VERSION 5.8 ;
BUSBITCHARS "[]" ;
DIVIDERCHAR "/" ;
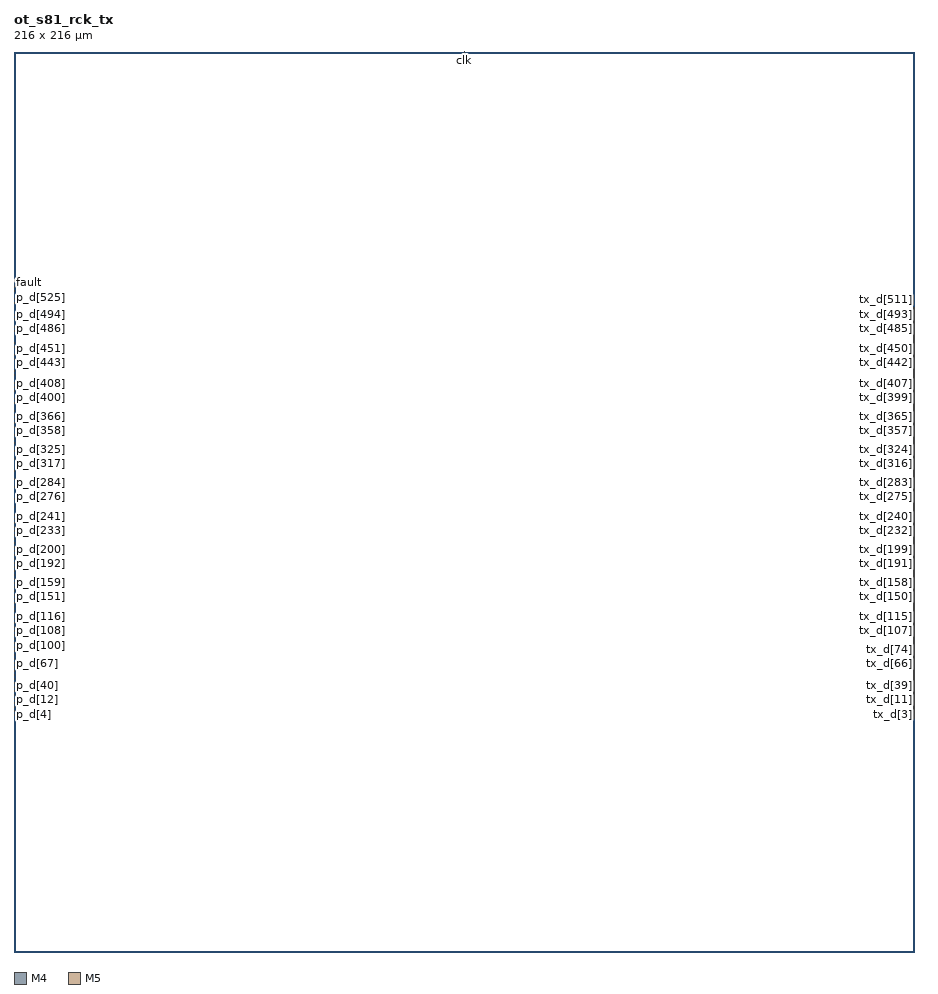
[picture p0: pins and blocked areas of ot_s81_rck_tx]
MACRO ot_s81_rck_tx
 CLASS BLOCK ;
 ORIGIN 0 0 ;
 SIZE 216.0 BY 216.0 ;
 SYMMETRY X Y ;
 PIN rst_n
  DIRECTION INPUT ;
  USE SIGNAL ;
  PORT
   LAYER M4 ;
   RECT 215.916 56.112 216.000 56.136 ;
  END
 END rst_n
 PIN tx_v
  DIRECTION INPUT ;
  USE SIGNAL ;
  PORT
   LAYER M4 ;
   RECT 215.916 56.304 216.000 56.328 ;
  END
 END tx_v
 PIN tx_d[0]
  DIRECTION INPUT ;
  USE SIGNAL ;
  PORT
   LAYER M4 ;
   RECT 215.916 56.496 216.000 56.520 ;
  END
 END tx_d[0]
 PIN tx_d[1]
  DIRECTION INPUT ;
  USE SIGNAL ;
  PORT
   LAYER M4 ;
   RECT 215.916 56.688 216.000 56.712 ;
  END
 END tx_d[1]
 PIN tx_d[2]
  DIRECTION INPUT ;
  USE SIGNAL ;
  PORT
   LAYER M4 ;
   RECT 215.916 56.880 216.000 56.904 ;
  END
 END tx_d[2]
 PIN tx_d[3]
  DIRECTION INPUT ;
  USE SIGNAL ;
  PORT
   LAYER M4 ;
   RECT 215.916 57.072 216.000 57.096 ;
  END
 END tx_d[3]
 PIN tx_d[4]
  DIRECTION INPUT ;
  USE SIGNAL ;
  PORT
   LAYER M4 ;
   RECT 215.916 57.264 216.000 57.288 ;
  END
 END tx_d[4]
 PIN tx_d[5]
  DIRECTION INPUT ;
  USE SIGNAL ;
  PORT
   LAYER M4 ;
   RECT 215.916 57.456 216.000 57.480 ;
  END
 END tx_d[5]
 PIN tx_d[6]
  DIRECTION INPUT ;
  USE SIGNAL ;
  PORT
   LAYER M4 ;
   RECT 215.916 57.648 216.000 57.672 ;
  END
 END tx_d[6]
 PIN tx_d[7]
  DIRECTION INPUT ;
  USE SIGNAL ;
  PORT
   LAYER M4 ;
   RECT 215.916 57.840 216.000 57.864 ;
  END
 END tx_d[7]
 PIN tx_d[8]
  DIRECTION INPUT ;
  USE SIGNAL ;
  PORT
   LAYER M4 ;
   RECT 215.916 58.032 216.000 58.056 ;
  END
 END tx_d[8]
 PIN tx_d[9]
  DIRECTION INPUT ;
  USE SIGNAL ;
  PORT
   LAYER M4 ;
   RECT 215.916 58.224 216.000 58.248 ;
  END
 END tx_d[9]
 PIN tx_d[10]
  DIRECTION INPUT ;
  USE SIGNAL ;
  PORT
   LAYER M4 ;
   RECT 215.916 58.416 216.000 58.440 ;
  END
 END tx_d[10]
 PIN tx_d[11]
  DIRECTION INPUT ;
  USE SIGNAL ;
  PORT
   LAYER M4 ;
   RECT 215.916 58.608 216.000 58.632 ;
  END
 END tx_d[11]
 PIN tx_d[12]
  DIRECTION INPUT ;
  USE SIGNAL ;
  PORT
   LAYER M4 ;
   RECT 215.916 58.800 216.000 58.824 ;
  END
 END tx_d[12]
 PIN tx_d[13]
  DIRECTION INPUT ;
  USE SIGNAL ;
  PORT
   LAYER M4 ;
   RECT 215.916 58.992 216.000 59.016 ;
  END
 END tx_d[13]
 PIN tx_d[14]
  DIRECTION INPUT ;
  USE SIGNAL ;
  PORT
   LAYER M4 ;
   RECT 215.916 59.184 216.000 59.208 ;
  END
 END tx_d[14]
 PIN tx_d[15]
  DIRECTION INPUT ;
  USE SIGNAL ;
  PORT
   LAYER M4 ;
   RECT 215.916 59.376 216.000 59.400 ;
  END
 END tx_d[15]
 PIN tx_d[16]
  DIRECTION INPUT ;
  USE SIGNAL ;
  PORT
   LAYER M4 ;
   RECT 215.916 59.568 216.000 59.592 ;
  END
 END tx_d[16]
 PIN tx_d[17]
  DIRECTION INPUT ;
  USE SIGNAL ;
  PORT
   LAYER M4 ;
   RECT 215.916 59.760 216.000 59.784 ;
  END
 END tx_d[17]
 PIN tx_d[18]
  DIRECTION INPUT ;
  USE SIGNAL ;
  PORT
   LAYER M4 ;
   RECT 215.916 59.952 216.000 59.976 ;
  END
 END tx_d[18]
 PIN tx_d[19]
  DIRECTION INPUT ;
  USE SIGNAL ;
  PORT
   LAYER M4 ;
   RECT 215.916 60.144 216.000 60.168 ;
  END
 END tx_d[19]
 PIN tx_d[20]
  DIRECTION INPUT ;
  USE SIGNAL ;
  PORT
   LAYER M4 ;
   RECT 215.916 60.336 216.000 60.360 ;
  END
 END tx_d[20]
 PIN tx_d[21]
  DIRECTION INPUT ;
  USE SIGNAL ;
  PORT
   LAYER M4 ;
   RECT 215.916 60.528 216.000 60.552 ;
  END
 END tx_d[21]
 PIN tx_d[22]
  DIRECTION INPUT ;
  USE SIGNAL ;
  PORT
   LAYER M4 ;
   RECT 215.916 60.720 216.000 60.744 ;
  END
 END tx_d[22]
 PIN tx_d[23]
  DIRECTION INPUT ;
  USE SIGNAL ;
  PORT
   LAYER M4 ;
   RECT 215.916 60.912 216.000 60.936 ;
  END
 END tx_d[23]
 PIN tx_d[24]
  DIRECTION INPUT ;
  USE SIGNAL ;
  PORT
   LAYER M4 ;
   RECT 215.916 61.104 216.000 61.128 ;
  END
 END tx_d[24]
 PIN tx_d[25]
  DIRECTION INPUT ;
  USE SIGNAL ;
  PORT
   LAYER M4 ;
   RECT 215.916 61.296 216.000 61.320 ;
  END
 END tx_d[25]
 PIN tx_d[26]
  DIRECTION INPUT ;
  USE SIGNAL ;
  PORT
   LAYER M4 ;
   RECT 215.916 61.488 216.000 61.512 ;
  END
 END tx_d[26]
 PIN tx_d[27]
  DIRECTION INPUT ;
  USE SIGNAL ;
  PORT
   LAYER M4 ;
   RECT 215.916 61.680 216.000 61.704 ;
  END
 END tx_d[27]
 PIN tx_d[28]
  DIRECTION INPUT ;
  USE SIGNAL ;
  PORT
   LAYER M4 ;
   RECT 215.916 61.872 216.000 61.896 ;
  END
 END tx_d[28]
 PIN tx_d[29]
  DIRECTION INPUT ;
  USE SIGNAL ;
  PORT
   LAYER M4 ;
   RECT 215.916 62.064 216.000 62.088 ;
  END
 END tx_d[29]
 PIN tx_d[30]
  DIRECTION INPUT ;
  USE SIGNAL ;
  PORT
   LAYER M4 ;
   RECT 215.916 62.256 216.000 62.280 ;
  END
 END tx_d[30]
 PIN tx_d[31]
  DIRECTION INPUT ;
  USE SIGNAL ;
  PORT
   LAYER M4 ;
   RECT 215.916 62.448 216.000 62.472 ;
  END
 END tx_d[31]
 PIN tx_d[32]
  DIRECTION INPUT ;
  USE SIGNAL ;
  PORT
   LAYER M4 ;
   RECT 215.916 62.640 216.000 62.664 ;
  END
 END tx_d[32]
 PIN tx_d[33]
  DIRECTION INPUT ;
  USE SIGNAL ;
  PORT
   LAYER M4 ;
   RECT 215.916 62.832 216.000 62.856 ;
  END
 END tx_d[33]
 PIN tx_d[34]
  DIRECTION INPUT ;
  USE SIGNAL ;
  PORT
   LAYER M4 ;
   RECT 215.916 63.024 216.000 63.048 ;
  END
 END tx_d[34]
 PIN tx_d[35]
  DIRECTION INPUT ;
  USE SIGNAL ;
  PORT
   LAYER M4 ;
   RECT 215.916 63.216 216.000 63.240 ;
  END
 END tx_d[35]
 PIN tx_d[36]
  DIRECTION INPUT ;
  USE SIGNAL ;
  PORT
   LAYER M4 ;
   RECT 215.916 63.408 216.000 63.432 ;
  END
 END tx_d[36]
 PIN tx_d[37]
  DIRECTION INPUT ;
  USE SIGNAL ;
  PORT
   LAYER M4 ;
   RECT 215.916 63.600 216.000 63.624 ;
  END
 END tx_d[37]
 PIN tx_d[38]
  DIRECTION INPUT ;
  USE SIGNAL ;
  PORT
   LAYER M4 ;
   RECT 215.916 63.792 216.000 63.816 ;
  END
 END tx_d[38]
 PIN tx_d[39]
  DIRECTION INPUT ;
  USE SIGNAL ;
  PORT
   LAYER M4 ;
   RECT 215.916 63.984 216.000 64.008 ;
  END
 END tx_d[39]
 PIN tx_d[40]
  DIRECTION INPUT ;
  USE SIGNAL ;
  PORT
   LAYER M4 ;
   RECT 215.916 64.176 216.000 64.200 ;
  END
 END tx_d[40]
 PIN tx_d[41]
  DIRECTION INPUT ;
  USE SIGNAL ;
  PORT
   LAYER M4 ;
   RECT 215.916 64.368 216.000 64.392 ;
  END
 END tx_d[41]
 PIN tx_d[42]
  DIRECTION INPUT ;
  USE SIGNAL ;
  PORT
   LAYER M4 ;
   RECT 215.916 64.560 216.000 64.584 ;
  END
 END tx_d[42]
 PIN tx_d[43]
  DIRECTION INPUT ;
  USE SIGNAL ;
  PORT
   LAYER M4 ;
   RECT 215.916 64.752 216.000 64.776 ;
  END
 END tx_d[43]
 PIN tx_d[44]
  DIRECTION INPUT ;
  USE SIGNAL ;
  PORT
   LAYER M4 ;
   RECT 215.916 64.944 216.000 64.968 ;
  END
 END tx_d[44]
 PIN tx_d[45]
  DIRECTION INPUT ;
  USE SIGNAL ;
  PORT
   LAYER M4 ;
   RECT 215.916 65.136 216.000 65.160 ;
  END
 END tx_d[45]
 PIN tx_d[46]
  DIRECTION INPUT ;
  USE SIGNAL ;
  PORT
   LAYER M4 ;
   RECT 215.916 65.328 216.000 65.352 ;
  END
 END tx_d[46]
 PIN tx_d[47]
  DIRECTION INPUT ;
  USE SIGNAL ;
  PORT
   LAYER M4 ;
   RECT 215.916 65.520 216.000 65.544 ;
  END
 END tx_d[47]
 PIN tx_d[48]
  DIRECTION INPUT ;
  USE SIGNAL ;
  PORT
   LAYER M4 ;
   RECT 215.916 65.712 216.000 65.736 ;
  END
 END tx_d[48]
 PIN tx_d[49]
  DIRECTION INPUT ;
  USE SIGNAL ;
  PORT
   LAYER M4 ;
   RECT 215.916 65.904 216.000 65.928 ;
  END
 END tx_d[49]
 PIN tx_d[50]
  DIRECTION INPUT ;
  USE SIGNAL ;
  PORT
   LAYER M4 ;
   RECT 215.916 66.096 216.000 66.120 ;
  END
 END tx_d[50]
 PIN tx_d[51]
  DIRECTION INPUT ;
  USE SIGNAL ;
  PORT
   LAYER M4 ;
   RECT 215.916 66.288 216.000 66.312 ;
  END
 END tx_d[51]
 PIN tx_d[52]
  DIRECTION INPUT ;
  USE SIGNAL ;
  PORT
   LAYER M4 ;
   RECT 215.916 66.480 216.000 66.504 ;
  END
 END tx_d[52]
 PIN tx_d[53]
  DIRECTION INPUT ;
  USE SIGNAL ;
  PORT
   LAYER M4 ;
   RECT 215.916 66.672 216.000 66.696 ;
  END
 END tx_d[53]
 PIN tx_d[54]
  DIRECTION INPUT ;
  USE SIGNAL ;
  PORT
   LAYER M4 ;
   RECT 215.916 66.864 216.000 66.888 ;
  END
 END tx_d[54]
 PIN tx_d[55]
  DIRECTION INPUT ;
  USE SIGNAL ;
  PORT
   LAYER M4 ;
   RECT 215.916 67.056 216.000 67.080 ;
  END
 END tx_d[55]
 PIN tx_d[56]
  DIRECTION INPUT ;
  USE SIGNAL ;
  PORT
   LAYER M4 ;
   RECT 215.916 67.248 216.000 67.272 ;
  END
 END tx_d[56]
 PIN tx_d[57]
  DIRECTION INPUT ;
  USE SIGNAL ;
  PORT
   LAYER M4 ;
   RECT 215.916 67.440 216.000 67.464 ;
  END
 END tx_d[57]
 PIN tx_d[58]
  DIRECTION INPUT ;
  USE SIGNAL ;
  PORT
   LAYER M4 ;
   RECT 215.916 67.632 216.000 67.656 ;
  END
 END tx_d[58]
 PIN tx_d[59]
  DIRECTION INPUT ;
  USE SIGNAL ;
  PORT
   LAYER M4 ;
   RECT 215.916 67.824 216.000 67.848 ;
  END
 END tx_d[59]
 PIN tx_d[60]
  DIRECTION INPUT ;
  USE SIGNAL ;
  PORT
   LAYER M4 ;
   RECT 215.916 68.016 216.000 68.040 ;
  END
 END tx_d[60]
 PIN tx_d[61]
  DIRECTION INPUT ;
  USE SIGNAL ;
  PORT
   LAYER M4 ;
   RECT 215.916 68.208 216.000 68.232 ;
  END
 END tx_d[61]
 PIN tx_d[62]
  DIRECTION INPUT ;
  USE SIGNAL ;
  PORT
   LAYER M4 ;
   RECT 215.916 68.400 216.000 68.424 ;
  END
 END tx_d[62]
 PIN tx_d[63]
  DIRECTION INPUT ;
  USE SIGNAL ;
  PORT
   LAYER M4 ;
   RECT 215.916 68.592 216.000 68.616 ;
  END
 END tx_d[63]
 PIN tx_d[64]
  DIRECTION INPUT ;
  USE SIGNAL ;
  PORT
   LAYER M4 ;
   RECT 215.916 68.784 216.000 68.808 ;
  END
 END tx_d[64]
 PIN tx_d[65]
  DIRECTION INPUT ;
  USE SIGNAL ;
  PORT
   LAYER M4 ;
   RECT 215.916 68.976 216.000 69.000 ;
  END
 END tx_d[65]
 PIN tx_d[66]
  DIRECTION INPUT ;
  USE SIGNAL ;
  PORT
   LAYER M4 ;
   RECT 215.916 69.168 216.000 69.192 ;
  END
 END tx_d[66]
 PIN tx_d[67]
  DIRECTION INPUT ;
  USE SIGNAL ;
  PORT
   LAYER M4 ;
   RECT 215.916 69.360 216.000 69.384 ;
  END
 END tx_d[67]
 PIN tx_d[68]
  DIRECTION INPUT ;
  USE SIGNAL ;
  PORT
   LAYER M4 ;
   RECT 215.916 69.552 216.000 69.576 ;
  END
 END tx_d[68]
 PIN tx_d[69]
  DIRECTION INPUT ;
  USE SIGNAL ;
  PORT
   LAYER M4 ;
   RECT 215.916 69.744 216.000 69.768 ;
  END
 END tx_d[69]
 PIN tx_d[70]
  DIRECTION INPUT ;
  USE SIGNAL ;
  PORT
   LAYER M4 ;
   RECT 215.916 69.936 216.000 69.960 ;
  END
 END tx_d[70]
 PIN tx_d[71]
  DIRECTION INPUT ;
  USE SIGNAL ;
  PORT
   LAYER M4 ;
   RECT 215.916 70.128 216.000 70.152 ;
  END
 END tx_d[71]
 PIN tx_d[72]
  DIRECTION INPUT ;
  USE SIGNAL ;
  PORT
   LAYER M4 ;
   RECT 215.916 70.320 216.000 70.344 ;
  END
 END tx_d[72]
 PIN tx_d[73]
  DIRECTION INPUT ;
  USE SIGNAL ;
  PORT
   LAYER M4 ;
   RECT 215.916 70.512 216.000 70.536 ;
  END
 END tx_d[73]
 PIN tx_d[74]
  DIRECTION INPUT ;
  USE SIGNAL ;
  PORT
   LAYER M4 ;
   RECT 215.916 70.704 216.000 70.728 ;
  END
 END tx_d[74]
 PIN tx_d[75]
  DIRECTION INPUT ;
  USE SIGNAL ;
  PORT
   LAYER M4 ;
   RECT 215.916 70.896 216.000 70.920 ;
  END
 END tx_d[75]
 PIN tx_d[76]
  DIRECTION INPUT ;
  USE SIGNAL ;
  PORT
   LAYER M4 ;
   RECT 215.916 71.088 216.000 71.112 ;
  END
 END tx_d[76]
 PIN tx_d[77]
  DIRECTION INPUT ;
  USE SIGNAL ;
  PORT
   LAYER M4 ;
   RECT 215.916 71.280 216.000 71.304 ;
  END
 END tx_d[77]
 PIN tx_d[78]
  DIRECTION INPUT ;
  USE SIGNAL ;
  PORT
   LAYER M4 ;
   RECT 215.916 71.472 216.000 71.496 ;
  END
 END tx_d[78]
 PIN tx_d[79]
  DIRECTION INPUT ;
  USE SIGNAL ;
  PORT
   LAYER M4 ;
   RECT 215.916 71.664 216.000 71.688 ;
  END
 END tx_d[79]
 PIN tx_d[80]
  DIRECTION INPUT ;
  USE SIGNAL ;
  PORT
   LAYER M4 ;
   RECT 215.916 71.856 216.000 71.880 ;
  END
 END tx_d[80]
 PIN tx_d[81]
  DIRECTION INPUT ;
  USE SIGNAL ;
  PORT
   LAYER M4 ;
   RECT 215.916 72.048 216.000 72.072 ;
  END
 END tx_d[81]
 PIN tx_d[82]
  DIRECTION INPUT ;
  USE SIGNAL ;
  PORT
   LAYER M4 ;
   RECT 215.916 72.240 216.000 72.264 ;
  END
 END tx_d[82]
 PIN tx_d[83]
  DIRECTION INPUT ;
  USE SIGNAL ;
  PORT
   LAYER M4 ;
   RECT 215.916 72.432 216.000 72.456 ;
  END
 END tx_d[83]
 PIN tx_d[84]
  DIRECTION INPUT ;
  USE SIGNAL ;
  PORT
   LAYER M4 ;
   RECT 215.916 72.624 216.000 72.648 ;
  END
 END tx_d[84]
 PIN tx_d[85]
  DIRECTION INPUT ;
  USE SIGNAL ;
  PORT
   LAYER M4 ;
   RECT 215.916 72.816 216.000 72.840 ;
  END
 END tx_d[85]
 PIN tx_d[86]
  DIRECTION INPUT ;
  USE SIGNAL ;
  PORT
   LAYER M4 ;
   RECT 215.916 73.008 216.000 73.032 ;
  END
 END tx_d[86]
 PIN tx_d[87]
  DIRECTION INPUT ;
  USE SIGNAL ;
  PORT
   LAYER M4 ;
   RECT 215.916 73.200 216.000 73.224 ;
  END
 END tx_d[87]
 PIN tx_d[88]
  DIRECTION INPUT ;
  USE SIGNAL ;
  PORT
   LAYER M4 ;
   RECT 215.916 73.392 216.000 73.416 ;
  END
 END tx_d[88]
 PIN tx_d[89]
  DIRECTION INPUT ;
  USE SIGNAL ;
  PORT
   LAYER M4 ;
   RECT 215.916 73.584 216.000 73.608 ;
  END
 END tx_d[89]
 PIN tx_d[90]
  DIRECTION INPUT ;
  USE SIGNAL ;
  PORT
   LAYER M4 ;
   RECT 215.916 73.776 216.000 73.800 ;
  END
 END tx_d[90]
 PIN tx_d[91]
  DIRECTION INPUT ;
  USE SIGNAL ;
  PORT
   LAYER M4 ;
   RECT 215.916 73.968 216.000 73.992 ;
  END
 END tx_d[91]
 PIN tx_d[92]
  DIRECTION INPUT ;
  USE SIGNAL ;
  PORT
   LAYER M4 ;
   RECT 215.916 74.160 216.000 74.184 ;
  END
 END tx_d[92]
 PIN tx_d[93]
  DIRECTION INPUT ;
  USE SIGNAL ;
  PORT
   LAYER M4 ;
   RECT 215.916 74.352 216.000 74.376 ;
  END
 END tx_d[93]
 PIN tx_d[94]
  DIRECTION INPUT ;
  USE SIGNAL ;
  PORT
   LAYER M4 ;
   RECT 215.916 74.544 216.000 74.568 ;
  END
 END tx_d[94]
 PIN tx_d[95]
  DIRECTION INPUT ;
  USE SIGNAL ;
  PORT
   LAYER M4 ;
   RECT 215.916 74.736 216.000 74.760 ;
  END
 END tx_d[95]
 PIN tx_d[96]
  DIRECTION INPUT ;
  USE SIGNAL ;
  PORT
   LAYER M4 ;
   RECT 215.916 74.928 216.000 74.952 ;
  END
 END tx_d[96]
 PIN tx_d[97]
  DIRECTION INPUT ;
  USE SIGNAL ;
  PORT
   LAYER M4 ;
   RECT 215.916 75.120 216.000 75.144 ;
  END
 END tx_d[97]
 PIN tx_d[98]
  DIRECTION INPUT ;
  USE SIGNAL ;
  PORT
   LAYER M4 ;
   RECT 215.916 75.312 216.000 75.336 ;
  END
 END tx_d[98]
 PIN tx_d[99]
  DIRECTION INPUT ;
  USE SIGNAL ;
  PORT
   LAYER M4 ;
   RECT 215.916 75.504 216.000 75.528 ;
  END
 END tx_d[99]
 PIN tx_d[100]
  DIRECTION INPUT ;
  USE SIGNAL ;
  PORT
   LAYER M4 ;
   RECT 215.916 75.696 216.000 75.720 ;
  END
 END tx_d[100]
 PIN tx_d[101]
  DIRECTION INPUT ;
  USE SIGNAL ;
  PORT
   LAYER M4 ;
   RECT 215.916 75.888 216.000 75.912 ;
  END
 END tx_d[101]
 PIN tx_d[102]
  DIRECTION INPUT ;
  USE SIGNAL ;
  PORT
   LAYER M4 ;
   RECT 215.916 76.080 216.000 76.104 ;
  END
 END tx_d[102]
 PIN tx_d[103]
  DIRECTION INPUT ;
  USE SIGNAL ;
  PORT
   LAYER M4 ;
   RECT 215.916 76.272 216.000 76.296 ;
  END
 END tx_d[103]
 PIN tx_d[104]
  DIRECTION INPUT ;
  USE SIGNAL ;
  PORT
   LAYER M4 ;
   RECT 215.916 76.464 216.000 76.488 ;
  END
 END tx_d[104]
 PIN tx_d[105]
  DIRECTION INPUT ;
  USE SIGNAL ;
  PORT
   LAYER M4 ;
   RECT 215.916 76.656 216.000 76.680 ;
  END
 END tx_d[105]
 PIN tx_d[106]
  DIRECTION INPUT ;
  USE SIGNAL ;
  PORT
   LAYER M4 ;
   RECT 215.916 76.848 216.000 76.872 ;
  END
 END tx_d[106]
 PIN tx_d[107]
  DIRECTION INPUT ;
  USE SIGNAL ;
  PORT
   LAYER M4 ;
   RECT 215.916 77.040 216.000 77.064 ;
  END
 END tx_d[107]
 PIN tx_d[108]
  DIRECTION INPUT ;
  USE SIGNAL ;
  PORT
   LAYER M4 ;
   RECT 215.916 77.232 216.000 77.256 ;
  END
 END tx_d[108]
 PIN tx_d[109]
  DIRECTION INPUT ;
  USE SIGNAL ;
  PORT
   LAYER M4 ;
   RECT 215.916 77.424 216.000 77.448 ;
  END
 END tx_d[109]
 PIN tx_d[110]
  DIRECTION INPUT ;
  USE SIGNAL ;
  PORT
   LAYER M4 ;
   RECT 215.916 77.616 216.000 77.640 ;
  END
 END tx_d[110]
 PIN tx_d[111]
  DIRECTION INPUT ;
  USE SIGNAL ;
  PORT
   LAYER M4 ;
   RECT 215.916 77.808 216.000 77.832 ;
  END
 END tx_d[111]
 PIN tx_d[112]
  DIRECTION INPUT ;
  USE SIGNAL ;
  PORT
   LAYER M4 ;
   RECT 215.916 78.000 216.000 78.024 ;
  END
 END tx_d[112]
 PIN tx_d[113]
  DIRECTION INPUT ;
  USE SIGNAL ;
  PORT
   LAYER M4 ;
   RECT 215.916 78.192 216.000 78.216 ;
  END
 END tx_d[113]
 PIN tx_d[114]
  DIRECTION INPUT ;
  USE SIGNAL ;
  PORT
   LAYER M4 ;
   RECT 215.916 78.384 216.000 78.408 ;
  END
 END tx_d[114]
 PIN tx_d[115]
  DIRECTION INPUT ;
  USE SIGNAL ;
  PORT
   LAYER M4 ;
   RECT 215.916 78.576 216.000 78.600 ;
  END
 END tx_d[115]
 PIN tx_d[116]
  DIRECTION INPUT ;
  USE SIGNAL ;
  PORT
   LAYER M4 ;
   RECT 215.916 78.768 216.000 78.792 ;
  END
 END tx_d[116]
 PIN tx_d[117]
  DIRECTION INPUT ;
  USE SIGNAL ;
  PORT
   LAYER M4 ;
   RECT 215.916 78.960 216.000 78.984 ;
  END
 END tx_d[117]
 PIN tx_d[118]
  DIRECTION INPUT ;
  USE SIGNAL ;
  PORT
   LAYER M4 ;
   RECT 215.916 79.152 216.000 79.176 ;
  END
 END tx_d[118]
 PIN tx_d[119]
  DIRECTION INPUT ;
  USE SIGNAL ;
  PORT
   LAYER M4 ;
   RECT 215.916 79.344 216.000 79.368 ;
  END
 END tx_d[119]
 PIN tx_d[120]
  DIRECTION INPUT ;
  USE SIGNAL ;
  PORT
   LAYER M4 ;
   RECT 215.916 79.536 216.000 79.560 ;
  END
 END tx_d[120]
 PIN tx_d[121]
  DIRECTION INPUT ;
  USE SIGNAL ;
  PORT
   LAYER M4 ;
   RECT 215.916 79.728 216.000 79.752 ;
  END
 END tx_d[121]
 PIN tx_d[122]
  DIRECTION INPUT ;
  USE SIGNAL ;
  PORT
   LAYER M4 ;
   RECT 215.916 79.920 216.000 79.944 ;
  END
 END tx_d[122]
 PIN tx_d[123]
  DIRECTION INPUT ;
  USE SIGNAL ;
  PORT
   LAYER M4 ;
   RECT 215.916 80.112 216.000 80.136 ;
  END
 END tx_d[123]
 PIN tx_d[124]
  DIRECTION INPUT ;
  USE SIGNAL ;
  PORT
   LAYER M4 ;
   RECT 215.916 80.304 216.000 80.328 ;
  END
 END tx_d[124]
 PIN tx_d[125]
  DIRECTION INPUT ;
  USE SIGNAL ;
  PORT
   LAYER M4 ;
   RECT 215.916 80.496 216.000 80.520 ;
  END
 END tx_d[125]
 PIN tx_d[126]
  DIRECTION INPUT ;
  USE SIGNAL ;
  PORT
   LAYER M4 ;
   RECT 215.916 80.688 216.000 80.712 ;
  END
 END tx_d[126]
 PIN tx_d[127]
  DIRECTION INPUT ;
  USE SIGNAL ;
  PORT
   LAYER M4 ;
   RECT 215.916 80.880 216.000 80.904 ;
  END
 END tx_d[127]
 PIN tx_d[128]
  DIRECTION INPUT ;
  USE SIGNAL ;
  PORT
   LAYER M4 ;
   RECT 215.916 81.072 216.000 81.096 ;
  END
 END tx_d[128]
 PIN tx_d[129]
  DIRECTION INPUT ;
  USE SIGNAL ;
  PORT
   LAYER M4 ;
   RECT 215.916 81.264 216.000 81.288 ;
  END
 END tx_d[129]
 PIN tx_d[130]
  DIRECTION INPUT ;
  USE SIGNAL ;
  PORT
   LAYER M4 ;
   RECT 215.916 81.456 216.000 81.480 ;
  END
 END tx_d[130]
 PIN tx_d[131]
  DIRECTION INPUT ;
  USE SIGNAL ;
  PORT
   LAYER M4 ;
   RECT 215.916 81.648 216.000 81.672 ;
  END
 END tx_d[131]
 PIN tx_d[132]
  DIRECTION INPUT ;
  USE SIGNAL ;
  PORT
   LAYER M4 ;
   RECT 215.916 81.840 216.000 81.864 ;
  END
 END tx_d[132]
 PIN tx_d[133]
  DIRECTION INPUT ;
  USE SIGNAL ;
  PORT
   LAYER M4 ;
   RECT 215.916 82.032 216.000 82.056 ;
  END
 END tx_d[133]
 PIN tx_d[134]
  DIRECTION INPUT ;
  USE SIGNAL ;
  PORT
   LAYER M4 ;
   RECT 215.916 82.224 216.000 82.248 ;
  END
 END tx_d[134]
 PIN tx_d[135]
  DIRECTION INPUT ;
  USE SIGNAL ;
  PORT
   LAYER M4 ;
   RECT 215.916 82.416 216.000 82.440 ;
  END
 END tx_d[135]
 PIN tx_d[136]
  DIRECTION INPUT ;
  USE SIGNAL ;
  PORT
   LAYER M4 ;
   RECT 215.916 82.608 216.000 82.632 ;
  END
 END tx_d[136]
 PIN tx_d[137]
  DIRECTION INPUT ;
  USE SIGNAL ;
  PORT
   LAYER M4 ;
   RECT 215.916 82.800 216.000 82.824 ;
  END
 END tx_d[137]
 PIN tx_d[138]
  DIRECTION INPUT ;
  USE SIGNAL ;
  PORT
   LAYER M4 ;
   RECT 215.916 82.992 216.000 83.016 ;
  END
 END tx_d[138]
 PIN tx_d[139]
  DIRECTION INPUT ;
  USE SIGNAL ;
  PORT
   LAYER M4 ;
   RECT 215.916 83.184 216.000 83.208 ;
  END
 END tx_d[139]
 PIN tx_d[140]
  DIRECTION INPUT ;
  USE SIGNAL ;
  PORT
   LAYER M4 ;
   RECT 215.916 83.376 216.000 83.400 ;
  END
 END tx_d[140]
 PIN tx_d[141]
  DIRECTION INPUT ;
  USE SIGNAL ;
  PORT
   LAYER M4 ;
   RECT 215.916 83.568 216.000 83.592 ;
  END
 END tx_d[141]
 PIN tx_d[142]
  DIRECTION INPUT ;
  USE SIGNAL ;
  PORT
   LAYER M4 ;
   RECT 215.916 83.760 216.000 83.784 ;
  END
 END tx_d[142]
 PIN tx_d[143]
  DIRECTION INPUT ;
  USE SIGNAL ;
  PORT
   LAYER M4 ;
   RECT 215.916 83.952 216.000 83.976 ;
  END
 END tx_d[143]
 PIN tx_d[144]
  DIRECTION INPUT ;
  USE SIGNAL ;
  PORT
   LAYER M4 ;
   RECT 215.916 84.144 216.000 84.168 ;
  END
 END tx_d[144]
 PIN tx_d[145]
  DIRECTION INPUT ;
  USE SIGNAL ;
  PORT
   LAYER M4 ;
   RECT 215.916 84.336 216.000 84.360 ;
  END
 END tx_d[145]
 PIN tx_d[146]
  DIRECTION INPUT ;
  USE SIGNAL ;
  PORT
   LAYER M4 ;
   RECT 215.916 84.528 216.000 84.552 ;
  END
 END tx_d[146]
 PIN tx_d[147]
  DIRECTION INPUT ;
  USE SIGNAL ;
  PORT
   LAYER M4 ;
   RECT 215.916 84.720 216.000 84.744 ;
  END
 END tx_d[147]
 PIN tx_d[148]
  DIRECTION INPUT ;
  USE SIGNAL ;
  PORT
   LAYER M4 ;
   RECT 215.916 84.912 216.000 84.936 ;
  END
 END tx_d[148]
 PIN tx_d[149]
  DIRECTION INPUT ;
  USE SIGNAL ;
  PORT
   LAYER M4 ;
   RECT 215.916 85.104 216.000 85.128 ;
  END
 END tx_d[149]
 PIN tx_d[150]
  DIRECTION INPUT ;
  USE SIGNAL ;
  PORT
   LAYER M4 ;
   RECT 215.916 85.296 216.000 85.320 ;
  END
 END tx_d[150]
 PIN tx_d[151]
  DIRECTION INPUT ;
  USE SIGNAL ;
  PORT
   LAYER M4 ;
   RECT 215.916 85.488 216.000 85.512 ;
  END
 END tx_d[151]
 PIN tx_d[152]
  DIRECTION INPUT ;
  USE SIGNAL ;
  PORT
   LAYER M4 ;
   RECT 215.916 85.680 216.000 85.704 ;
  END
 END tx_d[152]
 PIN tx_d[153]
  DIRECTION INPUT ;
  USE SIGNAL ;
  PORT
   LAYER M4 ;
   RECT 215.916 85.872 216.000 85.896 ;
  END
 END tx_d[153]
 PIN tx_d[154]
  DIRECTION INPUT ;
  USE SIGNAL ;
  PORT
   LAYER M4 ;
   RECT 215.916 86.064 216.000 86.088 ;
  END
 END tx_d[154]
 PIN tx_d[155]
  DIRECTION INPUT ;
  USE SIGNAL ;
  PORT
   LAYER M4 ;
   RECT 215.916 86.256 216.000 86.280 ;
  END
 END tx_d[155]
 PIN tx_d[156]
  DIRECTION INPUT ;
  USE SIGNAL ;
  PORT
   LAYER M4 ;
   RECT 215.916 86.448 216.000 86.472 ;
  END
 END tx_d[156]
 PIN tx_d[157]
  DIRECTION INPUT ;
  USE SIGNAL ;
  PORT
   LAYER M4 ;
   RECT 215.916 86.640 216.000 86.664 ;
  END
 END tx_d[157]
 PIN tx_d[158]
  DIRECTION INPUT ;
  USE SIGNAL ;
  PORT
   LAYER M4 ;
   RECT 215.916 86.832 216.000 86.856 ;
  END
 END tx_d[158]
 PIN tx_d[159]
  DIRECTION INPUT ;
  USE SIGNAL ;
  PORT
   LAYER M4 ;
   RECT 215.916 87.024 216.000 87.048 ;
  END
 END tx_d[159]
 PIN tx_d[160]
  DIRECTION INPUT ;
  USE SIGNAL ;
  PORT
   LAYER M4 ;
   RECT 215.916 87.216 216.000 87.240 ;
  END
 END tx_d[160]
 PIN tx_d[161]
  DIRECTION INPUT ;
  USE SIGNAL ;
  PORT
   LAYER M4 ;
   RECT 215.916 87.408 216.000 87.432 ;
  END
 END tx_d[161]
 PIN tx_d[162]
  DIRECTION INPUT ;
  USE SIGNAL ;
  PORT
   LAYER M4 ;
   RECT 215.916 87.600 216.000 87.624 ;
  END
 END tx_d[162]
 PIN tx_d[163]
  DIRECTION INPUT ;
  USE SIGNAL ;
  PORT
   LAYER M4 ;
   RECT 215.916 87.792 216.000 87.816 ;
  END
 END tx_d[163]
 PIN tx_d[164]
  DIRECTION INPUT ;
  USE SIGNAL ;
  PORT
   LAYER M4 ;
   RECT 215.916 87.984 216.000 88.008 ;
  END
 END tx_d[164]
 PIN tx_d[165]
  DIRECTION INPUT ;
  USE SIGNAL ;
  PORT
   LAYER M4 ;
   RECT 215.916 88.176 216.000 88.200 ;
  END
 END tx_d[165]
 PIN tx_d[166]
  DIRECTION INPUT ;
  USE SIGNAL ;
  PORT
   LAYER M4 ;
   RECT 215.916 88.368 216.000 88.392 ;
  END
 END tx_d[166]
 PIN tx_d[167]
  DIRECTION INPUT ;
  USE SIGNAL ;
  PORT
   LAYER M4 ;
   RECT 215.916 88.560 216.000 88.584 ;
  END
 END tx_d[167]
 PIN tx_d[168]
  DIRECTION INPUT ;
  USE SIGNAL ;
  PORT
   LAYER M4 ;
   RECT 215.916 88.752 216.000 88.776 ;
  END
 END tx_d[168]
 PIN tx_d[169]
  DIRECTION INPUT ;
  USE SIGNAL ;
  PORT
   LAYER M4 ;
   RECT 215.916 88.944 216.000 88.968 ;
  END
 END tx_d[169]
 PIN tx_d[170]
  DIRECTION INPUT ;
  USE SIGNAL ;
  PORT
   LAYER M4 ;
   RECT 215.916 89.136 216.000 89.160 ;
  END
 END tx_d[170]
 PIN tx_d[171]
  DIRECTION INPUT ;
  USE SIGNAL ;
  PORT
   LAYER M4 ;
   RECT 215.916 89.328 216.000 89.352 ;
  END
 END tx_d[171]
 PIN tx_d[172]
  DIRECTION INPUT ;
  USE SIGNAL ;
  PORT
   LAYER M4 ;
   RECT 215.916 89.520 216.000 89.544 ;
  END
 END tx_d[172]
 PIN tx_d[173]
  DIRECTION INPUT ;
  USE SIGNAL ;
  PORT
   LAYER M4 ;
   RECT 215.916 89.712 216.000 89.736 ;
  END
 END tx_d[173]
 PIN tx_d[174]
  DIRECTION INPUT ;
  USE SIGNAL ;
  PORT
   LAYER M4 ;
   RECT 215.916 89.904 216.000 89.928 ;
  END
 END tx_d[174]
 PIN tx_d[175]
  DIRECTION INPUT ;
  USE SIGNAL ;
  PORT
   LAYER M4 ;
   RECT 215.916 90.096 216.000 90.120 ;
  END
 END tx_d[175]
 PIN tx_d[176]
  DIRECTION INPUT ;
  USE SIGNAL ;
  PORT
   LAYER M4 ;
   RECT 215.916 90.288 216.000 90.312 ;
  END
 END tx_d[176]
 PIN tx_d[177]
  DIRECTION INPUT ;
  USE SIGNAL ;
  PORT
   LAYER M4 ;
   RECT 215.916 90.480 216.000 90.504 ;
  END
 END tx_d[177]
 PIN tx_d[178]
  DIRECTION INPUT ;
  USE SIGNAL ;
  PORT
   LAYER M4 ;
   RECT 215.916 90.672 216.000 90.696 ;
  END
 END tx_d[178]
 PIN tx_d[179]
  DIRECTION INPUT ;
  USE SIGNAL ;
  PORT
   LAYER M4 ;
   RECT 215.916 90.864 216.000 90.888 ;
  END
 END tx_d[179]
 PIN tx_d[180]
  DIRECTION INPUT ;
  USE SIGNAL ;
  PORT
   LAYER M4 ;
   RECT 215.916 91.056 216.000 91.080 ;
  END
 END tx_d[180]
 PIN tx_d[181]
  DIRECTION INPUT ;
  USE SIGNAL ;
  PORT
   LAYER M4 ;
   RECT 215.916 91.248 216.000 91.272 ;
  END
 END tx_d[181]
 PIN tx_d[182]
  DIRECTION INPUT ;
  USE SIGNAL ;
  PORT
   LAYER M4 ;
   RECT 215.916 91.440 216.000 91.464 ;
  END
 END tx_d[182]
 PIN tx_d[183]
  DIRECTION INPUT ;
  USE SIGNAL ;
  PORT
   LAYER M4 ;
   RECT 215.916 91.632 216.000 91.656 ;
  END
 END tx_d[183]
 PIN tx_d[184]
  DIRECTION INPUT ;
  USE SIGNAL ;
  PORT
   LAYER M4 ;
   RECT 215.916 91.824 216.000 91.848 ;
  END
 END tx_d[184]
 PIN tx_d[185]
  DIRECTION INPUT ;
  USE SIGNAL ;
  PORT
   LAYER M4 ;
   RECT 215.916 92.016 216.000 92.040 ;
  END
 END tx_d[185]
 PIN tx_d[186]
  DIRECTION INPUT ;
  USE SIGNAL ;
  PORT
   LAYER M4 ;
   RECT 215.916 92.208 216.000 92.232 ;
  END
 END tx_d[186]
 PIN tx_d[187]
  DIRECTION INPUT ;
  USE SIGNAL ;
  PORT
   LAYER M4 ;
   RECT 215.916 92.400 216.000 92.424 ;
  END
 END tx_d[187]
 PIN tx_d[188]
  DIRECTION INPUT ;
  USE SIGNAL ;
  PORT
   LAYER M4 ;
   RECT 215.916 92.592 216.000 92.616 ;
  END
 END tx_d[188]
 PIN tx_d[189]
  DIRECTION INPUT ;
  USE SIGNAL ;
  PORT
   LAYER M4 ;
   RECT 215.916 92.784 216.000 92.808 ;
  END
 END tx_d[189]
 PIN tx_d[190]
  DIRECTION INPUT ;
  USE SIGNAL ;
  PORT
   LAYER M4 ;
   RECT 215.916 92.976 216.000 93.000 ;
  END
 END tx_d[190]
 PIN tx_d[191]
  DIRECTION INPUT ;
  USE SIGNAL ;
  PORT
   LAYER M4 ;
   RECT 215.916 93.168 216.000 93.192 ;
  END
 END tx_d[191]
 PIN tx_d[192]
  DIRECTION INPUT ;
  USE SIGNAL ;
  PORT
   LAYER M4 ;
   RECT 215.916 93.360 216.000 93.384 ;
  END
 END tx_d[192]
 PIN tx_d[193]
  DIRECTION INPUT ;
  USE SIGNAL ;
  PORT
   LAYER M4 ;
   RECT 215.916 93.552 216.000 93.576 ;
  END
 END tx_d[193]
 PIN tx_d[194]
  DIRECTION INPUT ;
  USE SIGNAL ;
  PORT
   LAYER M4 ;
   RECT 215.916 93.744 216.000 93.768 ;
  END
 END tx_d[194]
 PIN tx_d[195]
  DIRECTION INPUT ;
  USE SIGNAL ;
  PORT
   LAYER M4 ;
   RECT 215.916 93.936 216.000 93.960 ;
  END
 END tx_d[195]
 PIN tx_d[196]
  DIRECTION INPUT ;
  USE SIGNAL ;
  PORT
   LAYER M4 ;
   RECT 215.916 94.128 216.000 94.152 ;
  END
 END tx_d[196]
 PIN tx_d[197]
  DIRECTION INPUT ;
  USE SIGNAL ;
  PORT
   LAYER M4 ;
   RECT 215.916 94.320 216.000 94.344 ;
  END
 END tx_d[197]
 PIN tx_d[198]
  DIRECTION INPUT ;
  USE SIGNAL ;
  PORT
   LAYER M4 ;
   RECT 215.916 94.512 216.000 94.536 ;
  END
 END tx_d[198]
 PIN tx_d[199]
  DIRECTION INPUT ;
  USE SIGNAL ;
  PORT
   LAYER M4 ;
   RECT 215.916 94.704 216.000 94.728 ;
  END
 END tx_d[199]
 PIN tx_d[200]
  DIRECTION INPUT ;
  USE SIGNAL ;
  PORT
   LAYER M4 ;
   RECT 215.916 94.896 216.000 94.920 ;
  END
 END tx_d[200]
 PIN tx_d[201]
  DIRECTION INPUT ;
  USE SIGNAL ;
  PORT
   LAYER M4 ;
   RECT 215.916 95.088 216.000 95.112 ;
  END
 END tx_d[201]
 PIN tx_d[202]
  DIRECTION INPUT ;
  USE SIGNAL ;
  PORT
   LAYER M4 ;
   RECT 215.916 95.280 216.000 95.304 ;
  END
 END tx_d[202]
 PIN tx_d[203]
  DIRECTION INPUT ;
  USE SIGNAL ;
  PORT
   LAYER M4 ;
   RECT 215.916 95.472 216.000 95.496 ;
  END
 END tx_d[203]
 PIN tx_d[204]
  DIRECTION INPUT ;
  USE SIGNAL ;
  PORT
   LAYER M4 ;
   RECT 215.916 95.664 216.000 95.688 ;
  END
 END tx_d[204]
 PIN tx_d[205]
  DIRECTION INPUT ;
  USE SIGNAL ;
  PORT
   LAYER M4 ;
   RECT 215.916 95.856 216.000 95.880 ;
  END
 END tx_d[205]
 PIN tx_d[206]
  DIRECTION INPUT ;
  USE SIGNAL ;
  PORT
   LAYER M4 ;
   RECT 215.916 96.048 216.000 96.072 ;
  END
 END tx_d[206]
 PIN tx_d[207]
  DIRECTION INPUT ;
  USE SIGNAL ;
  PORT
   LAYER M4 ;
   RECT 215.916 96.240 216.000 96.264 ;
  END
 END tx_d[207]
 PIN tx_d[208]
  DIRECTION INPUT ;
  USE SIGNAL ;
  PORT
   LAYER M4 ;
   RECT 215.916 96.432 216.000 96.456 ;
  END
 END tx_d[208]
 PIN tx_d[209]
  DIRECTION INPUT ;
  USE SIGNAL ;
  PORT
   LAYER M4 ;
   RECT 215.916 96.624 216.000 96.648 ;
  END
 END tx_d[209]
 PIN tx_d[210]
  DIRECTION INPUT ;
  USE SIGNAL ;
  PORT
   LAYER M4 ;
   RECT 215.916 96.816 216.000 96.840 ;
  END
 END tx_d[210]
 PIN tx_d[211]
  DIRECTION INPUT ;
  USE SIGNAL ;
  PORT
   LAYER M4 ;
   RECT 215.916 97.008 216.000 97.032 ;
  END
 END tx_d[211]
 PIN tx_d[212]
  DIRECTION INPUT ;
  USE SIGNAL ;
  PORT
   LAYER M4 ;
   RECT 215.916 97.200 216.000 97.224 ;
  END
 END tx_d[212]
 PIN tx_d[213]
  DIRECTION INPUT ;
  USE SIGNAL ;
  PORT
   LAYER M4 ;
   RECT 215.916 97.392 216.000 97.416 ;
  END
 END tx_d[213]
 PIN tx_d[214]
  DIRECTION INPUT ;
  USE SIGNAL ;
  PORT
   LAYER M4 ;
   RECT 215.916 97.584 216.000 97.608 ;
  END
 END tx_d[214]
 PIN tx_d[215]
  DIRECTION INPUT ;
  USE SIGNAL ;
  PORT
   LAYER M4 ;
   RECT 215.916 97.776 216.000 97.800 ;
  END
 END tx_d[215]
 PIN tx_d[216]
  DIRECTION INPUT ;
  USE SIGNAL ;
  PORT
   LAYER M4 ;
   RECT 215.916 97.968 216.000 97.992 ;
  END
 END tx_d[216]
 PIN tx_d[217]
  DIRECTION INPUT ;
  USE SIGNAL ;
  PORT
   LAYER M4 ;
   RECT 215.916 98.160 216.000 98.184 ;
  END
 END tx_d[217]
 PIN tx_d[218]
  DIRECTION INPUT ;
  USE SIGNAL ;
  PORT
   LAYER M4 ;
   RECT 215.916 98.352 216.000 98.376 ;
  END
 END tx_d[218]
 PIN tx_d[219]
  DIRECTION INPUT ;
  USE SIGNAL ;
  PORT
   LAYER M4 ;
   RECT 215.916 98.544 216.000 98.568 ;
  END
 END tx_d[219]
 PIN tx_d[220]
  DIRECTION INPUT ;
  USE SIGNAL ;
  PORT
   LAYER M4 ;
   RECT 215.916 98.736 216.000 98.760 ;
  END
 END tx_d[220]
 PIN tx_d[221]
  DIRECTION INPUT ;
  USE SIGNAL ;
  PORT
   LAYER M4 ;
   RECT 215.916 98.928 216.000 98.952 ;
  END
 END tx_d[221]
 PIN tx_d[222]
  DIRECTION INPUT ;
  USE SIGNAL ;
  PORT
   LAYER M4 ;
   RECT 215.916 99.120 216.000 99.144 ;
  END
 END tx_d[222]
 PIN tx_d[223]
  DIRECTION INPUT ;
  USE SIGNAL ;
  PORT
   LAYER M4 ;
   RECT 215.916 99.312 216.000 99.336 ;
  END
 END tx_d[223]
 PIN tx_d[224]
  DIRECTION INPUT ;
  USE SIGNAL ;
  PORT
   LAYER M4 ;
   RECT 215.916 99.504 216.000 99.528 ;
  END
 END tx_d[224]
 PIN tx_d[225]
  DIRECTION INPUT ;
  USE SIGNAL ;
  PORT
   LAYER M4 ;
   RECT 215.916 99.696 216.000 99.720 ;
  END
 END tx_d[225]
 PIN tx_d[226]
  DIRECTION INPUT ;
  USE SIGNAL ;
  PORT
   LAYER M4 ;
   RECT 215.916 99.888 216.000 99.912 ;
  END
 END tx_d[226]
 PIN tx_d[227]
  DIRECTION INPUT ;
  USE SIGNAL ;
  PORT
   LAYER M4 ;
   RECT 215.916 100.080 216.000 100.104 ;
  END
 END tx_d[227]
 PIN tx_d[228]
  DIRECTION INPUT ;
  USE SIGNAL ;
  PORT
   LAYER M4 ;
   RECT 215.916 100.272 216.000 100.296 ;
  END
 END tx_d[228]
 PIN tx_d[229]
  DIRECTION INPUT ;
  USE SIGNAL ;
  PORT
   LAYER M4 ;
   RECT 215.916 100.464 216.000 100.488 ;
  END
 END tx_d[229]
 PIN tx_d[230]
  DIRECTION INPUT ;
  USE SIGNAL ;
  PORT
   LAYER M4 ;
   RECT 215.916 100.656 216.000 100.680 ;
  END
 END tx_d[230]
 PIN tx_d[231]
  DIRECTION INPUT ;
  USE SIGNAL ;
  PORT
   LAYER M4 ;
   RECT 215.916 100.848 216.000 100.872 ;
  END
 END tx_d[231]
 PIN tx_d[232]
  DIRECTION INPUT ;
  USE SIGNAL ;
  PORT
   LAYER M4 ;
   RECT 215.916 101.040 216.000 101.064 ;
  END
 END tx_d[232]
 PIN tx_d[233]
  DIRECTION INPUT ;
  USE SIGNAL ;
  PORT
   LAYER M4 ;
   RECT 215.916 101.232 216.000 101.256 ;
  END
 END tx_d[233]
 PIN tx_d[234]
  DIRECTION INPUT ;
  USE SIGNAL ;
  PORT
   LAYER M4 ;
   RECT 215.916 101.424 216.000 101.448 ;
  END
 END tx_d[234]
 PIN tx_d[235]
  DIRECTION INPUT ;
  USE SIGNAL ;
  PORT
   LAYER M4 ;
   RECT 215.916 101.616 216.000 101.640 ;
  END
 END tx_d[235]
 PIN tx_d[236]
  DIRECTION INPUT ;
  USE SIGNAL ;
  PORT
   LAYER M4 ;
   RECT 215.916 101.808 216.000 101.832 ;
  END
 END tx_d[236]
 PIN tx_d[237]
  DIRECTION INPUT ;
  USE SIGNAL ;
  PORT
   LAYER M4 ;
   RECT 215.916 102.000 216.000 102.024 ;
  END
 END tx_d[237]
 PIN tx_d[238]
  DIRECTION INPUT ;
  USE SIGNAL ;
  PORT
   LAYER M4 ;
   RECT 215.916 102.192 216.000 102.216 ;
  END
 END tx_d[238]
 PIN tx_d[239]
  DIRECTION INPUT ;
  USE SIGNAL ;
  PORT
   LAYER M4 ;
   RECT 215.916 102.384 216.000 102.408 ;
  END
 END tx_d[239]
 PIN tx_d[240]
  DIRECTION INPUT ;
  USE SIGNAL ;
  PORT
   LAYER M4 ;
   RECT 215.916 102.576 216.000 102.600 ;
  END
 END tx_d[240]
 PIN tx_d[241]
  DIRECTION INPUT ;
  USE SIGNAL ;
  PORT
   LAYER M4 ;
   RECT 215.916 102.768 216.000 102.792 ;
  END
 END tx_d[241]
 PIN tx_d[242]
  DIRECTION INPUT ;
  USE SIGNAL ;
  PORT
   LAYER M4 ;
   RECT 215.916 102.960 216.000 102.984 ;
  END
 END tx_d[242]
 PIN tx_d[243]
  DIRECTION INPUT ;
  USE SIGNAL ;
  PORT
   LAYER M4 ;
   RECT 215.916 103.152 216.000 103.176 ;
  END
 END tx_d[243]
 PIN tx_d[244]
  DIRECTION INPUT ;
  USE SIGNAL ;
  PORT
   LAYER M4 ;
   RECT 215.916 103.344 216.000 103.368 ;
  END
 END tx_d[244]
 PIN tx_d[245]
  DIRECTION INPUT ;
  USE SIGNAL ;
  PORT
   LAYER M4 ;
   RECT 215.916 103.536 216.000 103.560 ;
  END
 END tx_d[245]
 PIN tx_d[246]
  DIRECTION INPUT ;
  USE SIGNAL ;
  PORT
   LAYER M4 ;
   RECT 215.916 103.728 216.000 103.752 ;
  END
 END tx_d[246]
 PIN tx_d[247]
  DIRECTION INPUT ;
  USE SIGNAL ;
  PORT
   LAYER M4 ;
   RECT 215.916 103.920 216.000 103.944 ;
  END
 END tx_d[247]
 PIN tx_d[248]
  DIRECTION INPUT ;
  USE SIGNAL ;
  PORT
   LAYER M4 ;
   RECT 215.916 104.112 216.000 104.136 ;
  END
 END tx_d[248]
 PIN tx_d[249]
  DIRECTION INPUT ;
  USE SIGNAL ;
  PORT
   LAYER M4 ;
   RECT 215.916 104.304 216.000 104.328 ;
  END
 END tx_d[249]
 PIN tx_d[250]
  DIRECTION INPUT ;
  USE SIGNAL ;
  PORT
   LAYER M4 ;
   RECT 215.916 104.496 216.000 104.520 ;
  END
 END tx_d[250]
 PIN tx_d[251]
  DIRECTION INPUT ;
  USE SIGNAL ;
  PORT
   LAYER M4 ;
   RECT 215.916 104.688 216.000 104.712 ;
  END
 END tx_d[251]
 PIN tx_d[252]
  DIRECTION INPUT ;
  USE SIGNAL ;
  PORT
   LAYER M4 ;
   RECT 215.916 104.880 216.000 104.904 ;
  END
 END tx_d[252]
 PIN tx_d[253]
  DIRECTION INPUT ;
  USE SIGNAL ;
  PORT
   LAYER M4 ;
   RECT 215.916 105.072 216.000 105.096 ;
  END
 END tx_d[253]
 PIN tx_d[254]
  DIRECTION INPUT ;
  USE SIGNAL ;
  PORT
   LAYER M4 ;
   RECT 215.916 105.264 216.000 105.288 ;
  END
 END tx_d[254]
 PIN tx_d[255]
  DIRECTION INPUT ;
  USE SIGNAL ;
  PORT
   LAYER M4 ;
   RECT 215.916 105.456 216.000 105.480 ;
  END
 END tx_d[255]
 PIN tx_d[256]
  DIRECTION INPUT ;
  USE SIGNAL ;
  PORT
   LAYER M4 ;
   RECT 215.916 105.648 216.000 105.672 ;
  END
 END tx_d[256]
 PIN tx_d[257]
  DIRECTION INPUT ;
  USE SIGNAL ;
  PORT
   LAYER M4 ;
   RECT 215.916 105.840 216.000 105.864 ;
  END
 END tx_d[257]
 PIN tx_d[258]
  DIRECTION INPUT ;
  USE SIGNAL ;
  PORT
   LAYER M4 ;
   RECT 215.916 106.032 216.000 106.056 ;
  END
 END tx_d[258]
 PIN tx_d[259]
  DIRECTION INPUT ;
  USE SIGNAL ;
  PORT
   LAYER M4 ;
   RECT 215.916 106.224 216.000 106.248 ;
  END
 END tx_d[259]
 PIN tx_d[260]
  DIRECTION INPUT ;
  USE SIGNAL ;
  PORT
   LAYER M4 ;
   RECT 215.916 106.416 216.000 106.440 ;
  END
 END tx_d[260]
 PIN tx_d[261]
  DIRECTION INPUT ;
  USE SIGNAL ;
  PORT
   LAYER M4 ;
   RECT 215.916 106.608 216.000 106.632 ;
  END
 END tx_d[261]
 PIN tx_d[262]
  DIRECTION INPUT ;
  USE SIGNAL ;
  PORT
   LAYER M4 ;
   RECT 215.916 106.800 216.000 106.824 ;
  END
 END tx_d[262]
 PIN tx_d[263]
  DIRECTION INPUT ;
  USE SIGNAL ;
  PORT
   LAYER M4 ;
   RECT 215.916 106.992 216.000 107.016 ;
  END
 END tx_d[263]
 PIN tx_d[264]
  DIRECTION INPUT ;
  USE SIGNAL ;
  PORT
   LAYER M4 ;
   RECT 215.916 107.184 216.000 107.208 ;
  END
 END tx_d[264]
 PIN tx_d[265]
  DIRECTION INPUT ;
  USE SIGNAL ;
  PORT
   LAYER M4 ;
   RECT 215.916 107.376 216.000 107.400 ;
  END
 END tx_d[265]
 PIN tx_d[266]
  DIRECTION INPUT ;
  USE SIGNAL ;
  PORT
   LAYER M4 ;
   RECT 215.916 107.568 216.000 107.592 ;
  END
 END tx_d[266]
 PIN tx_d[267]
  DIRECTION INPUT ;
  USE SIGNAL ;
  PORT
   LAYER M4 ;
   RECT 215.916 107.760 216.000 107.784 ;
  END
 END tx_d[267]
 PIN tx_d[268]
  DIRECTION INPUT ;
  USE SIGNAL ;
  PORT
   LAYER M4 ;
   RECT 215.916 107.952 216.000 107.976 ;
  END
 END tx_d[268]
 PIN tx_d[269]
  DIRECTION INPUT ;
  USE SIGNAL ;
  PORT
   LAYER M4 ;
   RECT 215.916 108.144 216.000 108.168 ;
  END
 END tx_d[269]
 PIN tx_d[270]
  DIRECTION INPUT ;
  USE SIGNAL ;
  PORT
   LAYER M4 ;
   RECT 215.916 108.336 216.000 108.360 ;
  END
 END tx_d[270]
 PIN tx_d[271]
  DIRECTION INPUT ;
  USE SIGNAL ;
  PORT
   LAYER M4 ;
   RECT 215.916 108.528 216.000 108.552 ;
  END
 END tx_d[271]
 PIN tx_d[272]
  DIRECTION INPUT ;
  USE SIGNAL ;
  PORT
   LAYER M4 ;
   RECT 215.916 108.720 216.000 108.744 ;
  END
 END tx_d[272]
 PIN tx_d[273]
  DIRECTION INPUT ;
  USE SIGNAL ;
  PORT
   LAYER M4 ;
   RECT 215.916 108.912 216.000 108.936 ;
  END
 END tx_d[273]
 PIN tx_d[274]
  DIRECTION INPUT ;
  USE SIGNAL ;
  PORT
   LAYER M4 ;
   RECT 215.916 109.104 216.000 109.128 ;
  END
 END tx_d[274]
 PIN tx_d[275]
  DIRECTION INPUT ;
  USE SIGNAL ;
  PORT
   LAYER M4 ;
   RECT 215.916 109.296 216.000 109.320 ;
  END
 END tx_d[275]
 PIN tx_d[276]
  DIRECTION INPUT ;
  USE SIGNAL ;
  PORT
   LAYER M4 ;
   RECT 215.916 109.488 216.000 109.512 ;
  END
 END tx_d[276]
 PIN tx_d[277]
  DIRECTION INPUT ;
  USE SIGNAL ;
  PORT
   LAYER M4 ;
   RECT 215.916 109.680 216.000 109.704 ;
  END
 END tx_d[277]
 PIN tx_d[278]
  DIRECTION INPUT ;
  USE SIGNAL ;
  PORT
   LAYER M4 ;
   RECT 215.916 109.872 216.000 109.896 ;
  END
 END tx_d[278]
 PIN tx_d[279]
  DIRECTION INPUT ;
  USE SIGNAL ;
  PORT
   LAYER M4 ;
   RECT 215.916 110.064 216.000 110.088 ;
  END
 END tx_d[279]
 PIN tx_d[280]
  DIRECTION INPUT ;
  USE SIGNAL ;
  PORT
   LAYER M4 ;
   RECT 215.916 110.256 216.000 110.280 ;
  END
 END tx_d[280]
 PIN tx_d[281]
  DIRECTION INPUT ;
  USE SIGNAL ;
  PORT
   LAYER M4 ;
   RECT 215.916 110.448 216.000 110.472 ;
  END
 END tx_d[281]
 PIN tx_d[282]
  DIRECTION INPUT ;
  USE SIGNAL ;
  PORT
   LAYER M4 ;
   RECT 215.916 110.640 216.000 110.664 ;
  END
 END tx_d[282]
 PIN tx_d[283]
  DIRECTION INPUT ;
  USE SIGNAL ;
  PORT
   LAYER M4 ;
   RECT 215.916 110.832 216.000 110.856 ;
  END
 END tx_d[283]
 PIN tx_d[284]
  DIRECTION INPUT ;
  USE SIGNAL ;
  PORT
   LAYER M4 ;
   RECT 215.916 111.024 216.000 111.048 ;
  END
 END tx_d[284]
 PIN tx_d[285]
  DIRECTION INPUT ;
  USE SIGNAL ;
  PORT
   LAYER M4 ;
   RECT 215.916 111.216 216.000 111.240 ;
  END
 END tx_d[285]
 PIN tx_d[286]
  DIRECTION INPUT ;
  USE SIGNAL ;
  PORT
   LAYER M4 ;
   RECT 215.916 111.408 216.000 111.432 ;
  END
 END tx_d[286]
 PIN tx_d[287]
  DIRECTION INPUT ;
  USE SIGNAL ;
  PORT
   LAYER M4 ;
   RECT 215.916 111.600 216.000 111.624 ;
  END
 END tx_d[287]
 PIN tx_d[288]
  DIRECTION INPUT ;
  USE SIGNAL ;
  PORT
   LAYER M4 ;
   RECT 215.916 111.792 216.000 111.816 ;
  END
 END tx_d[288]
 PIN tx_d[289]
  DIRECTION INPUT ;
  USE SIGNAL ;
  PORT
   LAYER M4 ;
   RECT 215.916 111.984 216.000 112.008 ;
  END
 END tx_d[289]
 PIN tx_d[290]
  DIRECTION INPUT ;
  USE SIGNAL ;
  PORT
   LAYER M4 ;
   RECT 215.916 112.176 216.000 112.200 ;
  END
 END tx_d[290]
 PIN tx_d[291]
  DIRECTION INPUT ;
  USE SIGNAL ;
  PORT
   LAYER M4 ;
   RECT 215.916 112.368 216.000 112.392 ;
  END
 END tx_d[291]
 PIN tx_d[292]
  DIRECTION INPUT ;
  USE SIGNAL ;
  PORT
   LAYER M4 ;
   RECT 215.916 112.560 216.000 112.584 ;
  END
 END tx_d[292]
 PIN tx_d[293]
  DIRECTION INPUT ;
  USE SIGNAL ;
  PORT
   LAYER M4 ;
   RECT 215.916 112.752 216.000 112.776 ;
  END
 END tx_d[293]
 PIN tx_d[294]
  DIRECTION INPUT ;
  USE SIGNAL ;
  PORT
   LAYER M4 ;
   RECT 215.916 112.944 216.000 112.968 ;
  END
 END tx_d[294]
 PIN tx_d[295]
  DIRECTION INPUT ;
  USE SIGNAL ;
  PORT
   LAYER M4 ;
   RECT 215.916 113.136 216.000 113.160 ;
  END
 END tx_d[295]
 PIN tx_d[296]
  DIRECTION INPUT ;
  USE SIGNAL ;
  PORT
   LAYER M4 ;
   RECT 215.916 113.328 216.000 113.352 ;
  END
 END tx_d[296]
 PIN tx_d[297]
  DIRECTION INPUT ;
  USE SIGNAL ;
  PORT
   LAYER M4 ;
   RECT 215.916 113.520 216.000 113.544 ;
  END
 END tx_d[297]
 PIN tx_d[298]
  DIRECTION INPUT ;
  USE SIGNAL ;
  PORT
   LAYER M4 ;
   RECT 215.916 113.712 216.000 113.736 ;
  END
 END tx_d[298]
 PIN tx_d[299]
  DIRECTION INPUT ;
  USE SIGNAL ;
  PORT
   LAYER M4 ;
   RECT 215.916 113.904 216.000 113.928 ;
  END
 END tx_d[299]
 PIN tx_d[300]
  DIRECTION INPUT ;
  USE SIGNAL ;
  PORT
   LAYER M4 ;
   RECT 215.916 114.096 216.000 114.120 ;
  END
 END tx_d[300]
 PIN tx_d[301]
  DIRECTION INPUT ;
  USE SIGNAL ;
  PORT
   LAYER M4 ;
   RECT 215.916 114.288 216.000 114.312 ;
  END
 END tx_d[301]
 PIN tx_d[302]
  DIRECTION INPUT ;
  USE SIGNAL ;
  PORT
   LAYER M4 ;
   RECT 215.916 114.480 216.000 114.504 ;
  END
 END tx_d[302]
 PIN tx_d[303]
  DIRECTION INPUT ;
  USE SIGNAL ;
  PORT
   LAYER M4 ;
   RECT 215.916 114.672 216.000 114.696 ;
  END
 END tx_d[303]
 PIN tx_d[304]
  DIRECTION INPUT ;
  USE SIGNAL ;
  PORT
   LAYER M4 ;
   RECT 215.916 114.864 216.000 114.888 ;
  END
 END tx_d[304]
 PIN tx_d[305]
  DIRECTION INPUT ;
  USE SIGNAL ;
  PORT
   LAYER M4 ;
   RECT 215.916 115.056 216.000 115.080 ;
  END
 END tx_d[305]
 PIN tx_d[306]
  DIRECTION INPUT ;
  USE SIGNAL ;
  PORT
   LAYER M4 ;
   RECT 215.916 115.248 216.000 115.272 ;
  END
 END tx_d[306]
 PIN tx_d[307]
  DIRECTION INPUT ;
  USE SIGNAL ;
  PORT
   LAYER M4 ;
   RECT 215.916 115.440 216.000 115.464 ;
  END
 END tx_d[307]
 PIN tx_d[308]
  DIRECTION INPUT ;
  USE SIGNAL ;
  PORT
   LAYER M4 ;
   RECT 215.916 115.632 216.000 115.656 ;
  END
 END tx_d[308]
 PIN tx_d[309]
  DIRECTION INPUT ;
  USE SIGNAL ;
  PORT
   LAYER M4 ;
   RECT 215.916 115.824 216.000 115.848 ;
  END
 END tx_d[309]
 PIN tx_d[310]
  DIRECTION INPUT ;
  USE SIGNAL ;
  PORT
   LAYER M4 ;
   RECT 215.916 116.016 216.000 116.040 ;
  END
 END tx_d[310]
 PIN tx_d[311]
  DIRECTION INPUT ;
  USE SIGNAL ;
  PORT
   LAYER M4 ;
   RECT 215.916 116.208 216.000 116.232 ;
  END
 END tx_d[311]
 PIN tx_d[312]
  DIRECTION INPUT ;
  USE SIGNAL ;
  PORT
   LAYER M4 ;
   RECT 215.916 116.400 216.000 116.424 ;
  END
 END tx_d[312]
 PIN tx_d[313]
  DIRECTION INPUT ;
  USE SIGNAL ;
  PORT
   LAYER M4 ;
   RECT 215.916 116.592 216.000 116.616 ;
  END
 END tx_d[313]
 PIN tx_d[314]
  DIRECTION INPUT ;
  USE SIGNAL ;
  PORT
   LAYER M4 ;
   RECT 215.916 116.784 216.000 116.808 ;
  END
 END tx_d[314]
 PIN tx_d[315]
  DIRECTION INPUT ;
  USE SIGNAL ;
  PORT
   LAYER M4 ;
   RECT 215.916 116.976 216.000 117.000 ;
  END
 END tx_d[315]
 PIN tx_d[316]
  DIRECTION INPUT ;
  USE SIGNAL ;
  PORT
   LAYER M4 ;
   RECT 215.916 117.168 216.000 117.192 ;
  END
 END tx_d[316]
 PIN tx_d[317]
  DIRECTION INPUT ;
  USE SIGNAL ;
  PORT
   LAYER M4 ;
   RECT 215.916 117.360 216.000 117.384 ;
  END
 END tx_d[317]
 PIN tx_d[318]
  DIRECTION INPUT ;
  USE SIGNAL ;
  PORT
   LAYER M4 ;
   RECT 215.916 117.552 216.000 117.576 ;
  END
 END tx_d[318]
 PIN tx_d[319]
  DIRECTION INPUT ;
  USE SIGNAL ;
  PORT
   LAYER M4 ;
   RECT 215.916 117.744 216.000 117.768 ;
  END
 END tx_d[319]
 PIN tx_d[320]
  DIRECTION INPUT ;
  USE SIGNAL ;
  PORT
   LAYER M4 ;
   RECT 215.916 117.936 216.000 117.960 ;
  END
 END tx_d[320]
 PIN tx_d[321]
  DIRECTION INPUT ;
  USE SIGNAL ;
  PORT
   LAYER M4 ;
   RECT 215.916 118.128 216.000 118.152 ;
  END
 END tx_d[321]
 PIN tx_d[322]
  DIRECTION INPUT ;
  USE SIGNAL ;
  PORT
   LAYER M4 ;
   RECT 215.916 118.320 216.000 118.344 ;
  END
 END tx_d[322]
 PIN tx_d[323]
  DIRECTION INPUT ;
  USE SIGNAL ;
  PORT
   LAYER M4 ;
   RECT 215.916 118.512 216.000 118.536 ;
  END
 END tx_d[323]
 PIN tx_d[324]
  DIRECTION INPUT ;
  USE SIGNAL ;
  PORT
   LAYER M4 ;
   RECT 215.916 118.704 216.000 118.728 ;
  END
 END tx_d[324]
 PIN tx_d[325]
  DIRECTION INPUT ;
  USE SIGNAL ;
  PORT
   LAYER M4 ;
   RECT 215.916 118.896 216.000 118.920 ;
  END
 END tx_d[325]
 PIN tx_d[326]
  DIRECTION INPUT ;
  USE SIGNAL ;
  PORT
   LAYER M4 ;
   RECT 215.916 119.088 216.000 119.112 ;
  END
 END tx_d[326]
 PIN tx_d[327]
  DIRECTION INPUT ;
  USE SIGNAL ;
  PORT
   LAYER M4 ;
   RECT 215.916 119.280 216.000 119.304 ;
  END
 END tx_d[327]
 PIN tx_d[328]
  DIRECTION INPUT ;
  USE SIGNAL ;
  PORT
   LAYER M4 ;
   RECT 215.916 119.472 216.000 119.496 ;
  END
 END tx_d[328]
 PIN tx_d[329]
  DIRECTION INPUT ;
  USE SIGNAL ;
  PORT
   LAYER M4 ;
   RECT 215.916 119.664 216.000 119.688 ;
  END
 END tx_d[329]
 PIN tx_d[330]
  DIRECTION INPUT ;
  USE SIGNAL ;
  PORT
   LAYER M4 ;
   RECT 215.916 119.856 216.000 119.880 ;
  END
 END tx_d[330]
 PIN tx_d[331]
  DIRECTION INPUT ;
  USE SIGNAL ;
  PORT
   LAYER M4 ;
   RECT 215.916 120.048 216.000 120.072 ;
  END
 END tx_d[331]
 PIN tx_d[332]
  DIRECTION INPUT ;
  USE SIGNAL ;
  PORT
   LAYER M4 ;
   RECT 215.916 120.240 216.000 120.264 ;
  END
 END tx_d[332]
 PIN tx_d[333]
  DIRECTION INPUT ;
  USE SIGNAL ;
  PORT
   LAYER M4 ;
   RECT 215.916 120.432 216.000 120.456 ;
  END
 END tx_d[333]
 PIN tx_d[334]
  DIRECTION INPUT ;
  USE SIGNAL ;
  PORT
   LAYER M4 ;
   RECT 215.916 120.624 216.000 120.648 ;
  END
 END tx_d[334]
 PIN tx_d[335]
  DIRECTION INPUT ;
  USE SIGNAL ;
  PORT
   LAYER M4 ;
   RECT 215.916 120.816 216.000 120.840 ;
  END
 END tx_d[335]
 PIN tx_d[336]
  DIRECTION INPUT ;
  USE SIGNAL ;
  PORT
   LAYER M4 ;
   RECT 215.916 121.008 216.000 121.032 ;
  END
 END tx_d[336]
 PIN tx_d[337]
  DIRECTION INPUT ;
  USE SIGNAL ;
  PORT
   LAYER M4 ;
   RECT 215.916 121.200 216.000 121.224 ;
  END
 END tx_d[337]
 PIN tx_d[338]
  DIRECTION INPUT ;
  USE SIGNAL ;
  PORT
   LAYER M4 ;
   RECT 215.916 121.392 216.000 121.416 ;
  END
 END tx_d[338]
 PIN tx_d[339]
  DIRECTION INPUT ;
  USE SIGNAL ;
  PORT
   LAYER M4 ;
   RECT 215.916 121.584 216.000 121.608 ;
  END
 END tx_d[339]
 PIN tx_d[340]
  DIRECTION INPUT ;
  USE SIGNAL ;
  PORT
   LAYER M4 ;
   RECT 215.916 121.776 216.000 121.800 ;
  END
 END tx_d[340]
 PIN tx_d[341]
  DIRECTION INPUT ;
  USE SIGNAL ;
  PORT
   LAYER M4 ;
   RECT 215.916 121.968 216.000 121.992 ;
  END
 END tx_d[341]
 PIN tx_d[342]
  DIRECTION INPUT ;
  USE SIGNAL ;
  PORT
   LAYER M4 ;
   RECT 215.916 122.160 216.000 122.184 ;
  END
 END tx_d[342]
 PIN tx_d[343]
  DIRECTION INPUT ;
  USE SIGNAL ;
  PORT
   LAYER M4 ;
   RECT 215.916 122.352 216.000 122.376 ;
  END
 END tx_d[343]
 PIN tx_d[344]
  DIRECTION INPUT ;
  USE SIGNAL ;
  PORT
   LAYER M4 ;
   RECT 215.916 122.544 216.000 122.568 ;
  END
 END tx_d[344]
 PIN tx_d[345]
  DIRECTION INPUT ;
  USE SIGNAL ;
  PORT
   LAYER M4 ;
   RECT 215.916 122.736 216.000 122.760 ;
  END
 END tx_d[345]
 PIN tx_d[346]
  DIRECTION INPUT ;
  USE SIGNAL ;
  PORT
   LAYER M4 ;
   RECT 215.916 122.928 216.000 122.952 ;
  END
 END tx_d[346]
 PIN tx_d[347]
  DIRECTION INPUT ;
  USE SIGNAL ;
  PORT
   LAYER M4 ;
   RECT 215.916 123.120 216.000 123.144 ;
  END
 END tx_d[347]
 PIN tx_d[348]
  DIRECTION INPUT ;
  USE SIGNAL ;
  PORT
   LAYER M4 ;
   RECT 215.916 123.312 216.000 123.336 ;
  END
 END tx_d[348]
 PIN tx_d[349]
  DIRECTION INPUT ;
  USE SIGNAL ;
  PORT
   LAYER M4 ;
   RECT 215.916 123.504 216.000 123.528 ;
  END
 END tx_d[349]
 PIN tx_d[350]
  DIRECTION INPUT ;
  USE SIGNAL ;
  PORT
   LAYER M4 ;
   RECT 215.916 123.696 216.000 123.720 ;
  END
 END tx_d[350]
 PIN tx_d[351]
  DIRECTION INPUT ;
  USE SIGNAL ;
  PORT
   LAYER M4 ;
   RECT 215.916 123.888 216.000 123.912 ;
  END
 END tx_d[351]
 PIN tx_d[352]
  DIRECTION INPUT ;
  USE SIGNAL ;
  PORT
   LAYER M4 ;
   RECT 215.916 124.080 216.000 124.104 ;
  END
 END tx_d[352]
 PIN tx_d[353]
  DIRECTION INPUT ;
  USE SIGNAL ;
  PORT
   LAYER M4 ;
   RECT 215.916 124.272 216.000 124.296 ;
  END
 END tx_d[353]
 PIN tx_d[354]
  DIRECTION INPUT ;
  USE SIGNAL ;
  PORT
   LAYER M4 ;
   RECT 215.916 124.464 216.000 124.488 ;
  END
 END tx_d[354]
 PIN tx_d[355]
  DIRECTION INPUT ;
  USE SIGNAL ;
  PORT
   LAYER M4 ;
   RECT 215.916 124.656 216.000 124.680 ;
  END
 END tx_d[355]
 PIN tx_d[356]
  DIRECTION INPUT ;
  USE SIGNAL ;
  PORT
   LAYER M4 ;
   RECT 215.916 124.848 216.000 124.872 ;
  END
 END tx_d[356]
 PIN tx_d[357]
  DIRECTION INPUT ;
  USE SIGNAL ;
  PORT
   LAYER M4 ;
   RECT 215.916 125.040 216.000 125.064 ;
  END
 END tx_d[357]
 PIN tx_d[358]
  DIRECTION INPUT ;
  USE SIGNAL ;
  PORT
   LAYER M4 ;
   RECT 215.916 125.232 216.000 125.256 ;
  END
 END tx_d[358]
 PIN tx_d[359]
  DIRECTION INPUT ;
  USE SIGNAL ;
  PORT
   LAYER M4 ;
   RECT 215.916 125.424 216.000 125.448 ;
  END
 END tx_d[359]
 PIN tx_d[360]
  DIRECTION INPUT ;
  USE SIGNAL ;
  PORT
   LAYER M4 ;
   RECT 215.916 125.616 216.000 125.640 ;
  END
 END tx_d[360]
 PIN tx_d[361]
  DIRECTION INPUT ;
  USE SIGNAL ;
  PORT
   LAYER M4 ;
   RECT 215.916 125.808 216.000 125.832 ;
  END
 END tx_d[361]
 PIN tx_d[362]
  DIRECTION INPUT ;
  USE SIGNAL ;
  PORT
   LAYER M4 ;
   RECT 215.916 126.000 216.000 126.024 ;
  END
 END tx_d[362]
 PIN tx_d[363]
  DIRECTION INPUT ;
  USE SIGNAL ;
  PORT
   LAYER M4 ;
   RECT 215.916 126.192 216.000 126.216 ;
  END
 END tx_d[363]
 PIN tx_d[364]
  DIRECTION INPUT ;
  USE SIGNAL ;
  PORT
   LAYER M4 ;
   RECT 215.916 126.384 216.000 126.408 ;
  END
 END tx_d[364]
 PIN tx_d[365]
  DIRECTION INPUT ;
  USE SIGNAL ;
  PORT
   LAYER M4 ;
   RECT 215.916 126.576 216.000 126.600 ;
  END
 END tx_d[365]
 PIN tx_d[366]
  DIRECTION INPUT ;
  USE SIGNAL ;
  PORT
   LAYER M4 ;
   RECT 215.916 126.768 216.000 126.792 ;
  END
 END tx_d[366]
 PIN tx_d[367]
  DIRECTION INPUT ;
  USE SIGNAL ;
  PORT
   LAYER M4 ;
   RECT 215.916 126.960 216.000 126.984 ;
  END
 END tx_d[367]
 PIN tx_d[368]
  DIRECTION INPUT ;
  USE SIGNAL ;
  PORT
   LAYER M4 ;
   RECT 215.916 127.152 216.000 127.176 ;
  END
 END tx_d[368]
 PIN tx_d[369]
  DIRECTION INPUT ;
  USE SIGNAL ;
  PORT
   LAYER M4 ;
   RECT 215.916 127.344 216.000 127.368 ;
  END
 END tx_d[369]
 PIN tx_d[370]
  DIRECTION INPUT ;
  USE SIGNAL ;
  PORT
   LAYER M4 ;
   RECT 215.916 127.536 216.000 127.560 ;
  END
 END tx_d[370]
 PIN tx_d[371]
  DIRECTION INPUT ;
  USE SIGNAL ;
  PORT
   LAYER M4 ;
   RECT 215.916 127.728 216.000 127.752 ;
  END
 END tx_d[371]
 PIN tx_d[372]
  DIRECTION INPUT ;
  USE SIGNAL ;
  PORT
   LAYER M4 ;
   RECT 215.916 127.920 216.000 127.944 ;
  END
 END tx_d[372]
 PIN tx_d[373]
  DIRECTION INPUT ;
  USE SIGNAL ;
  PORT
   LAYER M4 ;
   RECT 215.916 128.112 216.000 128.136 ;
  END
 END tx_d[373]
 PIN tx_d[374]
  DIRECTION INPUT ;
  USE SIGNAL ;
  PORT
   LAYER M4 ;
   RECT 215.916 128.304 216.000 128.328 ;
  END
 END tx_d[374]
 PIN tx_d[375]
  DIRECTION INPUT ;
  USE SIGNAL ;
  PORT
   LAYER M4 ;
   RECT 215.916 128.496 216.000 128.520 ;
  END
 END tx_d[375]
 PIN tx_d[376]
  DIRECTION INPUT ;
  USE SIGNAL ;
  PORT
   LAYER M4 ;
   RECT 215.916 128.688 216.000 128.712 ;
  END
 END tx_d[376]
 PIN tx_d[377]
  DIRECTION INPUT ;
  USE SIGNAL ;
  PORT
   LAYER M4 ;
   RECT 215.916 128.880 216.000 128.904 ;
  END
 END tx_d[377]
 PIN tx_d[378]
  DIRECTION INPUT ;
  USE SIGNAL ;
  PORT
   LAYER M4 ;
   RECT 215.916 129.072 216.000 129.096 ;
  END
 END tx_d[378]
 PIN tx_d[379]
  DIRECTION INPUT ;
  USE SIGNAL ;
  PORT
   LAYER M4 ;
   RECT 215.916 129.264 216.000 129.288 ;
  END
 END tx_d[379]
 PIN tx_d[380]
  DIRECTION INPUT ;
  USE SIGNAL ;
  PORT
   LAYER M4 ;
   RECT 215.916 129.456 216.000 129.480 ;
  END
 END tx_d[380]
 PIN tx_d[381]
  DIRECTION INPUT ;
  USE SIGNAL ;
  PORT
   LAYER M4 ;
   RECT 215.916 129.648 216.000 129.672 ;
  END
 END tx_d[381]
 PIN tx_d[382]
  DIRECTION INPUT ;
  USE SIGNAL ;
  PORT
   LAYER M4 ;
   RECT 215.916 129.840 216.000 129.864 ;
  END
 END tx_d[382]
 PIN tx_d[383]
  DIRECTION INPUT ;
  USE SIGNAL ;
  PORT
   LAYER M4 ;
   RECT 215.916 130.032 216.000 130.056 ;
  END
 END tx_d[383]
 PIN tx_d[384]
  DIRECTION INPUT ;
  USE SIGNAL ;
  PORT
   LAYER M4 ;
   RECT 215.916 130.224 216.000 130.248 ;
  END
 END tx_d[384]
 PIN tx_d[385]
  DIRECTION INPUT ;
  USE SIGNAL ;
  PORT
   LAYER M4 ;
   RECT 215.916 130.416 216.000 130.440 ;
  END
 END tx_d[385]
 PIN tx_d[386]
  DIRECTION INPUT ;
  USE SIGNAL ;
  PORT
   LAYER M4 ;
   RECT 215.916 130.608 216.000 130.632 ;
  END
 END tx_d[386]
 PIN tx_d[387]
  DIRECTION INPUT ;
  USE SIGNAL ;
  PORT
   LAYER M4 ;
   RECT 215.916 130.800 216.000 130.824 ;
  END
 END tx_d[387]
 PIN tx_d[388]
  DIRECTION INPUT ;
  USE SIGNAL ;
  PORT
   LAYER M4 ;
   RECT 215.916 130.992 216.000 131.016 ;
  END
 END tx_d[388]
 PIN tx_d[389]
  DIRECTION INPUT ;
  USE SIGNAL ;
  PORT
   LAYER M4 ;
   RECT 215.916 131.184 216.000 131.208 ;
  END
 END tx_d[389]
 PIN tx_d[390]
  DIRECTION INPUT ;
  USE SIGNAL ;
  PORT
   LAYER M4 ;
   RECT 215.916 131.376 216.000 131.400 ;
  END
 END tx_d[390]
 PIN tx_d[391]
  DIRECTION INPUT ;
  USE SIGNAL ;
  PORT
   LAYER M4 ;
   RECT 215.916 131.568 216.000 131.592 ;
  END
 END tx_d[391]
 PIN tx_d[392]
  DIRECTION INPUT ;
  USE SIGNAL ;
  PORT
   LAYER M4 ;
   RECT 215.916 131.760 216.000 131.784 ;
  END
 END tx_d[392]
 PIN tx_d[393]
  DIRECTION INPUT ;
  USE SIGNAL ;
  PORT
   LAYER M4 ;
   RECT 215.916 131.952 216.000 131.976 ;
  END
 END tx_d[393]
 PIN tx_d[394]
  DIRECTION INPUT ;
  USE SIGNAL ;
  PORT
   LAYER M4 ;
   RECT 215.916 132.144 216.000 132.168 ;
  END
 END tx_d[394]
 PIN tx_d[395]
  DIRECTION INPUT ;
  USE SIGNAL ;
  PORT
   LAYER M4 ;
   RECT 215.916 132.336 216.000 132.360 ;
  END
 END tx_d[395]
 PIN tx_d[396]
  DIRECTION INPUT ;
  USE SIGNAL ;
  PORT
   LAYER M4 ;
   RECT 215.916 132.528 216.000 132.552 ;
  END
 END tx_d[396]
 PIN tx_d[397]
  DIRECTION INPUT ;
  USE SIGNAL ;
  PORT
   LAYER M4 ;
   RECT 215.916 132.720 216.000 132.744 ;
  END
 END tx_d[397]
 PIN tx_d[398]
  DIRECTION INPUT ;
  USE SIGNAL ;
  PORT
   LAYER M4 ;
   RECT 215.916 132.912 216.000 132.936 ;
  END
 END tx_d[398]
 PIN tx_d[399]
  DIRECTION INPUT ;
  USE SIGNAL ;
  PORT
   LAYER M4 ;
   RECT 215.916 133.104 216.000 133.128 ;
  END
 END tx_d[399]
 PIN tx_d[400]
  DIRECTION INPUT ;
  USE SIGNAL ;
  PORT
   LAYER M4 ;
   RECT 215.916 133.296 216.000 133.320 ;
  END
 END tx_d[400]
 PIN tx_d[401]
  DIRECTION INPUT ;
  USE SIGNAL ;
  PORT
   LAYER M4 ;
   RECT 215.916 133.488 216.000 133.512 ;
  END
 END tx_d[401]
 PIN tx_d[402]
  DIRECTION INPUT ;
  USE SIGNAL ;
  PORT
   LAYER M4 ;
   RECT 215.916 133.680 216.000 133.704 ;
  END
 END tx_d[402]
 PIN tx_d[403]
  DIRECTION INPUT ;
  USE SIGNAL ;
  PORT
   LAYER M4 ;
   RECT 215.916 133.872 216.000 133.896 ;
  END
 END tx_d[403]
 PIN tx_d[404]
  DIRECTION INPUT ;
  USE SIGNAL ;
  PORT
   LAYER M4 ;
   RECT 215.916 134.064 216.000 134.088 ;
  END
 END tx_d[404]
 PIN tx_d[405]
  DIRECTION INPUT ;
  USE SIGNAL ;
  PORT
   LAYER M4 ;
   RECT 215.916 134.256 216.000 134.280 ;
  END
 END tx_d[405]
 PIN tx_d[406]
  DIRECTION INPUT ;
  USE SIGNAL ;
  PORT
   LAYER M4 ;
   RECT 215.916 134.448 216.000 134.472 ;
  END
 END tx_d[406]
 PIN tx_d[407]
  DIRECTION INPUT ;
  USE SIGNAL ;
  PORT
   LAYER M4 ;
   RECT 215.916 134.640 216.000 134.664 ;
  END
 END tx_d[407]
 PIN tx_d[408]
  DIRECTION INPUT ;
  USE SIGNAL ;
  PORT
   LAYER M4 ;
   RECT 215.916 134.832 216.000 134.856 ;
  END
 END tx_d[408]
 PIN tx_d[409]
  DIRECTION INPUT ;
  USE SIGNAL ;
  PORT
   LAYER M4 ;
   RECT 215.916 135.024 216.000 135.048 ;
  END
 END tx_d[409]
 PIN tx_d[410]
  DIRECTION INPUT ;
  USE SIGNAL ;
  PORT
   LAYER M4 ;
   RECT 215.916 135.216 216.000 135.240 ;
  END
 END tx_d[410]
 PIN tx_d[411]
  DIRECTION INPUT ;
  USE SIGNAL ;
  PORT
   LAYER M4 ;
   RECT 215.916 135.408 216.000 135.432 ;
  END
 END tx_d[411]
 PIN tx_d[412]
  DIRECTION INPUT ;
  USE SIGNAL ;
  PORT
   LAYER M4 ;
   RECT 215.916 135.600 216.000 135.624 ;
  END
 END tx_d[412]
 PIN tx_d[413]
  DIRECTION INPUT ;
  USE SIGNAL ;
  PORT
   LAYER M4 ;
   RECT 215.916 135.792 216.000 135.816 ;
  END
 END tx_d[413]
 PIN tx_d[414]
  DIRECTION INPUT ;
  USE SIGNAL ;
  PORT
   LAYER M4 ;
   RECT 215.916 135.984 216.000 136.008 ;
  END
 END tx_d[414]
 PIN tx_d[415]
  DIRECTION INPUT ;
  USE SIGNAL ;
  PORT
   LAYER M4 ;
   RECT 215.916 136.176 216.000 136.200 ;
  END
 END tx_d[415]
 PIN tx_d[416]
  DIRECTION INPUT ;
  USE SIGNAL ;
  PORT
   LAYER M4 ;
   RECT 215.916 136.368 216.000 136.392 ;
  END
 END tx_d[416]
 PIN tx_d[417]
  DIRECTION INPUT ;
  USE SIGNAL ;
  PORT
   LAYER M4 ;
   RECT 215.916 136.560 216.000 136.584 ;
  END
 END tx_d[417]
 PIN tx_d[418]
  DIRECTION INPUT ;
  USE SIGNAL ;
  PORT
   LAYER M4 ;
   RECT 215.916 136.752 216.000 136.776 ;
  END
 END tx_d[418]
 PIN tx_d[419]
  DIRECTION INPUT ;
  USE SIGNAL ;
  PORT
   LAYER M4 ;
   RECT 215.916 136.944 216.000 136.968 ;
  END
 END tx_d[419]
 PIN tx_d[420]
  DIRECTION INPUT ;
  USE SIGNAL ;
  PORT
   LAYER M4 ;
   RECT 215.916 137.136 216.000 137.160 ;
  END
 END tx_d[420]
 PIN tx_d[421]
  DIRECTION INPUT ;
  USE SIGNAL ;
  PORT
   LAYER M4 ;
   RECT 215.916 137.328 216.000 137.352 ;
  END
 END tx_d[421]
 PIN tx_d[422]
  DIRECTION INPUT ;
  USE SIGNAL ;
  PORT
   LAYER M4 ;
   RECT 215.916 137.520 216.000 137.544 ;
  END
 END tx_d[422]
 PIN tx_d[423]
  DIRECTION INPUT ;
  USE SIGNAL ;
  PORT
   LAYER M4 ;
   RECT 215.916 137.712 216.000 137.736 ;
  END
 END tx_d[423]
 PIN tx_d[424]
  DIRECTION INPUT ;
  USE SIGNAL ;
  PORT
   LAYER M4 ;
   RECT 215.916 137.904 216.000 137.928 ;
  END
 END tx_d[424]
 PIN tx_d[425]
  DIRECTION INPUT ;
  USE SIGNAL ;
  PORT
   LAYER M4 ;
   RECT 215.916 138.096 216.000 138.120 ;
  END
 END tx_d[425]
 PIN tx_d[426]
  DIRECTION INPUT ;
  USE SIGNAL ;
  PORT
   LAYER M4 ;
   RECT 215.916 138.288 216.000 138.312 ;
  END
 END tx_d[426]
 PIN tx_d[427]
  DIRECTION INPUT ;
  USE SIGNAL ;
  PORT
   LAYER M4 ;
   RECT 215.916 138.480 216.000 138.504 ;
  END
 END tx_d[427]
 PIN tx_d[428]
  DIRECTION INPUT ;
  USE SIGNAL ;
  PORT
   LAYER M4 ;
   RECT 215.916 138.672 216.000 138.696 ;
  END
 END tx_d[428]
 PIN tx_d[429]
  DIRECTION INPUT ;
  USE SIGNAL ;
  PORT
   LAYER M4 ;
   RECT 215.916 138.864 216.000 138.888 ;
  END
 END tx_d[429]
 PIN tx_d[430]
  DIRECTION INPUT ;
  USE SIGNAL ;
  PORT
   LAYER M4 ;
   RECT 215.916 139.056 216.000 139.080 ;
  END
 END tx_d[430]
 PIN tx_d[431]
  DIRECTION INPUT ;
  USE SIGNAL ;
  PORT
   LAYER M4 ;
   RECT 215.916 139.248 216.000 139.272 ;
  END
 END tx_d[431]
 PIN tx_d[432]
  DIRECTION INPUT ;
  USE SIGNAL ;
  PORT
   LAYER M4 ;
   RECT 215.916 139.440 216.000 139.464 ;
  END
 END tx_d[432]
 PIN tx_d[433]
  DIRECTION INPUT ;
  USE SIGNAL ;
  PORT
   LAYER M4 ;
   RECT 215.916 139.632 216.000 139.656 ;
  END
 END tx_d[433]
 PIN tx_d[434]
  DIRECTION INPUT ;
  USE SIGNAL ;
  PORT
   LAYER M4 ;
   RECT 215.916 139.824 216.000 139.848 ;
  END
 END tx_d[434]
 PIN tx_d[435]
  DIRECTION INPUT ;
  USE SIGNAL ;
  PORT
   LAYER M4 ;
   RECT 215.916 140.016 216.000 140.040 ;
  END
 END tx_d[435]
 PIN tx_d[436]
  DIRECTION INPUT ;
  USE SIGNAL ;
  PORT
   LAYER M4 ;
   RECT 215.916 140.208 216.000 140.232 ;
  END
 END tx_d[436]
 PIN tx_d[437]
  DIRECTION INPUT ;
  USE SIGNAL ;
  PORT
   LAYER M4 ;
   RECT 215.916 140.400 216.000 140.424 ;
  END
 END tx_d[437]
 PIN tx_d[438]
  DIRECTION INPUT ;
  USE SIGNAL ;
  PORT
   LAYER M4 ;
   RECT 215.916 140.592 216.000 140.616 ;
  END
 END tx_d[438]
 PIN tx_d[439]
  DIRECTION INPUT ;
  USE SIGNAL ;
  PORT
   LAYER M4 ;
   RECT 215.916 140.784 216.000 140.808 ;
  END
 END tx_d[439]
 PIN tx_d[440]
  DIRECTION INPUT ;
  USE SIGNAL ;
  PORT
   LAYER M4 ;
   RECT 215.916 140.976 216.000 141.000 ;
  END
 END tx_d[440]
 PIN tx_d[441]
  DIRECTION INPUT ;
  USE SIGNAL ;
  PORT
   LAYER M4 ;
   RECT 215.916 141.168 216.000 141.192 ;
  END
 END tx_d[441]
 PIN tx_d[442]
  DIRECTION INPUT ;
  USE SIGNAL ;
  PORT
   LAYER M4 ;
   RECT 215.916 141.360 216.000 141.384 ;
  END
 END tx_d[442]
 PIN tx_d[443]
  DIRECTION INPUT ;
  USE SIGNAL ;
  PORT
   LAYER M4 ;
   RECT 215.916 141.552 216.000 141.576 ;
  END
 END tx_d[443]
 PIN tx_d[444]
  DIRECTION INPUT ;
  USE SIGNAL ;
  PORT
   LAYER M4 ;
   RECT 215.916 141.744 216.000 141.768 ;
  END
 END tx_d[444]
 PIN tx_d[445]
  DIRECTION INPUT ;
  USE SIGNAL ;
  PORT
   LAYER M4 ;
   RECT 215.916 141.936 216.000 141.960 ;
  END
 END tx_d[445]
 PIN tx_d[446]
  DIRECTION INPUT ;
  USE SIGNAL ;
  PORT
   LAYER M4 ;
   RECT 215.916 142.128 216.000 142.152 ;
  END
 END tx_d[446]
 PIN tx_d[447]
  DIRECTION INPUT ;
  USE SIGNAL ;
  PORT
   LAYER M4 ;
   RECT 215.916 142.320 216.000 142.344 ;
  END
 END tx_d[447]
 PIN tx_d[448]
  DIRECTION INPUT ;
  USE SIGNAL ;
  PORT
   LAYER M4 ;
   RECT 215.916 142.512 216.000 142.536 ;
  END
 END tx_d[448]
 PIN tx_d[449]
  DIRECTION INPUT ;
  USE SIGNAL ;
  PORT
   LAYER M4 ;
   RECT 215.916 142.704 216.000 142.728 ;
  END
 END tx_d[449]
 PIN tx_d[450]
  DIRECTION INPUT ;
  USE SIGNAL ;
  PORT
   LAYER M4 ;
   RECT 215.916 142.896 216.000 142.920 ;
  END
 END tx_d[450]
 PIN tx_d[451]
  DIRECTION INPUT ;
  USE SIGNAL ;
  PORT
   LAYER M4 ;
   RECT 215.916 143.088 216.000 143.112 ;
  END
 END tx_d[451]
 PIN tx_d[452]
  DIRECTION INPUT ;
  USE SIGNAL ;
  PORT
   LAYER M4 ;
   RECT 215.916 143.280 216.000 143.304 ;
  END
 END tx_d[452]
 PIN tx_d[453]
  DIRECTION INPUT ;
  USE SIGNAL ;
  PORT
   LAYER M4 ;
   RECT 215.916 143.472 216.000 143.496 ;
  END
 END tx_d[453]
 PIN tx_d[454]
  DIRECTION INPUT ;
  USE SIGNAL ;
  PORT
   LAYER M4 ;
   RECT 215.916 143.664 216.000 143.688 ;
  END
 END tx_d[454]
 PIN tx_d[455]
  DIRECTION INPUT ;
  USE SIGNAL ;
  PORT
   LAYER M4 ;
   RECT 215.916 143.856 216.000 143.880 ;
  END
 END tx_d[455]
 PIN tx_d[456]
  DIRECTION INPUT ;
  USE SIGNAL ;
  PORT
   LAYER M4 ;
   RECT 215.916 144.048 216.000 144.072 ;
  END
 END tx_d[456]
 PIN tx_d[457]
  DIRECTION INPUT ;
  USE SIGNAL ;
  PORT
   LAYER M4 ;
   RECT 215.916 144.240 216.000 144.264 ;
  END
 END tx_d[457]
 PIN tx_d[458]
  DIRECTION INPUT ;
  USE SIGNAL ;
  PORT
   LAYER M4 ;
   RECT 215.916 144.432 216.000 144.456 ;
  END
 END tx_d[458]
 PIN tx_d[459]
  DIRECTION INPUT ;
  USE SIGNAL ;
  PORT
   LAYER M4 ;
   RECT 215.916 144.624 216.000 144.648 ;
  END
 END tx_d[459]
 PIN tx_d[460]
  DIRECTION INPUT ;
  USE SIGNAL ;
  PORT
   LAYER M4 ;
   RECT 215.916 144.816 216.000 144.840 ;
  END
 END tx_d[460]
 PIN tx_d[461]
  DIRECTION INPUT ;
  USE SIGNAL ;
  PORT
   LAYER M4 ;
   RECT 215.916 145.008 216.000 145.032 ;
  END
 END tx_d[461]
 PIN tx_d[462]
  DIRECTION INPUT ;
  USE SIGNAL ;
  PORT
   LAYER M4 ;
   RECT 215.916 145.200 216.000 145.224 ;
  END
 END tx_d[462]
 PIN tx_d[463]
  DIRECTION INPUT ;
  USE SIGNAL ;
  PORT
   LAYER M4 ;
   RECT 215.916 145.392 216.000 145.416 ;
  END
 END tx_d[463]
 PIN tx_d[464]
  DIRECTION INPUT ;
  USE SIGNAL ;
  PORT
   LAYER M4 ;
   RECT 215.916 145.584 216.000 145.608 ;
  END
 END tx_d[464]
 PIN tx_d[465]
  DIRECTION INPUT ;
  USE SIGNAL ;
  PORT
   LAYER M4 ;
   RECT 215.916 145.776 216.000 145.800 ;
  END
 END tx_d[465]
 PIN tx_d[466]
  DIRECTION INPUT ;
  USE SIGNAL ;
  PORT
   LAYER M4 ;
   RECT 215.916 145.968 216.000 145.992 ;
  END
 END tx_d[466]
 PIN tx_d[467]
  DIRECTION INPUT ;
  USE SIGNAL ;
  PORT
   LAYER M4 ;
   RECT 215.916 146.160 216.000 146.184 ;
  END
 END tx_d[467]
 PIN tx_d[468]
  DIRECTION INPUT ;
  USE SIGNAL ;
  PORT
   LAYER M4 ;
   RECT 215.916 146.352 216.000 146.376 ;
  END
 END tx_d[468]
 PIN tx_d[469]
  DIRECTION INPUT ;
  USE SIGNAL ;
  PORT
   LAYER M4 ;
   RECT 215.916 146.544 216.000 146.568 ;
  END
 END tx_d[469]
 PIN tx_d[470]
  DIRECTION INPUT ;
  USE SIGNAL ;
  PORT
   LAYER M4 ;
   RECT 215.916 146.736 216.000 146.760 ;
  END
 END tx_d[470]
 PIN tx_d[471]
  DIRECTION INPUT ;
  USE SIGNAL ;
  PORT
   LAYER M4 ;
   RECT 215.916 146.928 216.000 146.952 ;
  END
 END tx_d[471]
 PIN tx_d[472]
  DIRECTION INPUT ;
  USE SIGNAL ;
  PORT
   LAYER M4 ;
   RECT 215.916 147.120 216.000 147.144 ;
  END
 END tx_d[472]
 PIN tx_d[473]
  DIRECTION INPUT ;
  USE SIGNAL ;
  PORT
   LAYER M4 ;
   RECT 215.916 147.312 216.000 147.336 ;
  END
 END tx_d[473]
 PIN tx_d[474]
  DIRECTION INPUT ;
  USE SIGNAL ;
  PORT
   LAYER M4 ;
   RECT 215.916 147.504 216.000 147.528 ;
  END
 END tx_d[474]
 PIN tx_d[475]
  DIRECTION INPUT ;
  USE SIGNAL ;
  PORT
   LAYER M4 ;
   RECT 215.916 147.696 216.000 147.720 ;
  END
 END tx_d[475]
 PIN tx_d[476]
  DIRECTION INPUT ;
  USE SIGNAL ;
  PORT
   LAYER M4 ;
   RECT 215.916 147.888 216.000 147.912 ;
  END
 END tx_d[476]
 PIN tx_d[477]
  DIRECTION INPUT ;
  USE SIGNAL ;
  PORT
   LAYER M4 ;
   RECT 215.916 148.080 216.000 148.104 ;
  END
 END tx_d[477]
 PIN tx_d[478]
  DIRECTION INPUT ;
  USE SIGNAL ;
  PORT
   LAYER M4 ;
   RECT 215.916 148.272 216.000 148.296 ;
  END
 END tx_d[478]
 PIN tx_d[479]
  DIRECTION INPUT ;
  USE SIGNAL ;
  PORT
   LAYER M4 ;
   RECT 215.916 148.464 216.000 148.488 ;
  END
 END tx_d[479]
 PIN tx_d[480]
  DIRECTION INPUT ;
  USE SIGNAL ;
  PORT
   LAYER M4 ;
   RECT 215.916 148.656 216.000 148.680 ;
  END
 END tx_d[480]
 PIN tx_d[481]
  DIRECTION INPUT ;
  USE SIGNAL ;
  PORT
   LAYER M4 ;
   RECT 215.916 148.848 216.000 148.872 ;
  END
 END tx_d[481]
 PIN tx_d[482]
  DIRECTION INPUT ;
  USE SIGNAL ;
  PORT
   LAYER M4 ;
   RECT 215.916 149.040 216.000 149.064 ;
  END
 END tx_d[482]
 PIN tx_d[483]
  DIRECTION INPUT ;
  USE SIGNAL ;
  PORT
   LAYER M4 ;
   RECT 215.916 149.232 216.000 149.256 ;
  END
 END tx_d[483]
 PIN tx_d[484]
  DIRECTION INPUT ;
  USE SIGNAL ;
  PORT
   LAYER M4 ;
   RECT 215.916 149.424 216.000 149.448 ;
  END
 END tx_d[484]
 PIN tx_d[485]
  DIRECTION INPUT ;
  USE SIGNAL ;
  PORT
   LAYER M4 ;
   RECT 215.916 149.616 216.000 149.640 ;
  END
 END tx_d[485]
 PIN tx_d[486]
  DIRECTION INPUT ;
  USE SIGNAL ;
  PORT
   LAYER M4 ;
   RECT 215.916 149.808 216.000 149.832 ;
  END
 END tx_d[486]
 PIN tx_d[487]
  DIRECTION INPUT ;
  USE SIGNAL ;
  PORT
   LAYER M4 ;
   RECT 215.916 150.000 216.000 150.024 ;
  END
 END tx_d[487]
 PIN tx_d[488]
  DIRECTION INPUT ;
  USE SIGNAL ;
  PORT
   LAYER M4 ;
   RECT 215.916 150.192 216.000 150.216 ;
  END
 END tx_d[488]
 PIN tx_d[489]
  DIRECTION INPUT ;
  USE SIGNAL ;
  PORT
   LAYER M4 ;
   RECT 215.916 150.384 216.000 150.408 ;
  END
 END tx_d[489]
 PIN tx_d[490]
  DIRECTION INPUT ;
  USE SIGNAL ;
  PORT
   LAYER M4 ;
   RECT 215.916 150.576 216.000 150.600 ;
  END
 END tx_d[490]
 PIN tx_d[491]
  DIRECTION INPUT ;
  USE SIGNAL ;
  PORT
   LAYER M4 ;
   RECT 215.916 150.768 216.000 150.792 ;
  END
 END tx_d[491]
 PIN tx_d[492]
  DIRECTION INPUT ;
  USE SIGNAL ;
  PORT
   LAYER M4 ;
   RECT 215.916 150.960 216.000 150.984 ;
  END
 END tx_d[492]
 PIN tx_d[493]
  DIRECTION INPUT ;
  USE SIGNAL ;
  PORT
   LAYER M4 ;
   RECT 215.916 151.152 216.000 151.176 ;
  END
 END tx_d[493]
 PIN tx_d[494]
  DIRECTION INPUT ;
  USE SIGNAL ;
  PORT
   LAYER M4 ;
   RECT 215.916 151.344 216.000 151.368 ;
  END
 END tx_d[494]
 PIN tx_d[495]
  DIRECTION INPUT ;
  USE SIGNAL ;
  PORT
   LAYER M4 ;
   RECT 215.916 151.536 216.000 151.560 ;
  END
 END tx_d[495]
 PIN tx_d[496]
  DIRECTION INPUT ;
  USE SIGNAL ;
  PORT
   LAYER M4 ;
   RECT 215.916 151.728 216.000 151.752 ;
  END
 END tx_d[496]
 PIN tx_d[497]
  DIRECTION INPUT ;
  USE SIGNAL ;
  PORT
   LAYER M4 ;
   RECT 215.916 151.920 216.000 151.944 ;
  END
 END tx_d[497]
 PIN tx_d[498]
  DIRECTION INPUT ;
  USE SIGNAL ;
  PORT
   LAYER M4 ;
   RECT 215.916 152.112 216.000 152.136 ;
  END
 END tx_d[498]
 PIN tx_d[499]
  DIRECTION INPUT ;
  USE SIGNAL ;
  PORT
   LAYER M4 ;
   RECT 215.916 152.304 216.000 152.328 ;
  END
 END tx_d[499]
 PIN tx_d[500]
  DIRECTION INPUT ;
  USE SIGNAL ;
  PORT
   LAYER M4 ;
   RECT 215.916 152.496 216.000 152.520 ;
  END
 END tx_d[500]
 PIN tx_d[501]
  DIRECTION INPUT ;
  USE SIGNAL ;
  PORT
   LAYER M4 ;
   RECT 215.916 152.688 216.000 152.712 ;
  END
 END tx_d[501]
 PIN tx_d[502]
  DIRECTION INPUT ;
  USE SIGNAL ;
  PORT
   LAYER M4 ;
   RECT 215.916 152.880 216.000 152.904 ;
  END
 END tx_d[502]
 PIN tx_d[503]
  DIRECTION INPUT ;
  USE SIGNAL ;
  PORT
   LAYER M4 ;
   RECT 215.916 153.072 216.000 153.096 ;
  END
 END tx_d[503]
 PIN tx_d[504]
  DIRECTION INPUT ;
  USE SIGNAL ;
  PORT
   LAYER M4 ;
   RECT 215.916 153.264 216.000 153.288 ;
  END
 END tx_d[504]
 PIN tx_d[505]
  DIRECTION INPUT ;
  USE SIGNAL ;
  PORT
   LAYER M4 ;
   RECT 215.916 153.456 216.000 153.480 ;
  END
 END tx_d[505]
 PIN tx_d[506]
  DIRECTION INPUT ;
  USE SIGNAL ;
  PORT
   LAYER M4 ;
   RECT 215.916 153.648 216.000 153.672 ;
  END
 END tx_d[506]
 PIN tx_d[507]
  DIRECTION INPUT ;
  USE SIGNAL ;
  PORT
   LAYER M4 ;
   RECT 215.916 153.840 216.000 153.864 ;
  END
 END tx_d[507]
 PIN tx_d[508]
  DIRECTION INPUT ;
  USE SIGNAL ;
  PORT
   LAYER M4 ;
   RECT 215.916 154.032 216.000 154.056 ;
  END
 END tx_d[508]
 PIN tx_d[509]
  DIRECTION INPUT ;
  USE SIGNAL ;
  PORT
   LAYER M4 ;
   RECT 215.916 154.224 216.000 154.248 ;
  END
 END tx_d[509]
 PIN tx_d[510]
  DIRECTION INPUT ;
  USE SIGNAL ;
  PORT
   LAYER M4 ;
   RECT 215.916 154.416 216.000 154.440 ;
  END
 END tx_d[510]
 PIN tx_d[511]
  DIRECTION INPUT ;
  USE SIGNAL ;
  PORT
   LAYER M4 ;
   RECT 215.916 154.608 216.000 154.632 ;
  END
 END tx_d[511]
 PIN p_v
  DIRECTION OUTPUT ;
  USE SIGNAL ;
  PORT
   LAYER M4 ;
   RECT 0.000 56.112 0.084 56.136 ;
  END
 END p_v
 PIN p_d[0]
  DIRECTION OUTPUT ;
  USE SIGNAL ;
  PORT
   LAYER M4 ;
   RECT 0.000 56.304 0.084 56.328 ;
  END
 END p_d[0]
 PIN p_d[1]
  DIRECTION OUTPUT ;
  USE SIGNAL ;
  PORT
   LAYER M4 ;
   RECT 0.000 56.496 0.084 56.520 ;
  END
 END p_d[1]
 PIN p_d[2]
  DIRECTION OUTPUT ;
  USE SIGNAL ;
  PORT
   LAYER M4 ;
   RECT 0.000 56.688 0.084 56.712 ;
  END
 END p_d[2]
 PIN p_d[3]
  DIRECTION OUTPUT ;
  USE SIGNAL ;
  PORT
   LAYER M4 ;
   RECT 0.000 56.880 0.084 56.904 ;
  END
 END p_d[3]
 PIN p_d[4]
  DIRECTION OUTPUT ;
  USE SIGNAL ;
  PORT
   LAYER M4 ;
   RECT 0.000 57.072 0.084 57.096 ;
  END
 END p_d[4]
 PIN p_d[5]
  DIRECTION OUTPUT ;
  USE SIGNAL ;
  PORT
   LAYER M4 ;
   RECT 0.000 57.264 0.084 57.288 ;
  END
 END p_d[5]
 PIN p_d[6]
  DIRECTION OUTPUT ;
  USE SIGNAL ;
  PORT
   LAYER M4 ;
   RECT 0.000 57.456 0.084 57.480 ;
  END
 END p_d[6]
 PIN p_d[7]
  DIRECTION OUTPUT ;
  USE SIGNAL ;
  PORT
   LAYER M4 ;
   RECT 0.000 57.648 0.084 57.672 ;
  END
 END p_d[7]
 PIN p_d[8]
  DIRECTION OUTPUT ;
  USE SIGNAL ;
  PORT
   LAYER M4 ;
   RECT 0.000 57.840 0.084 57.864 ;
  END
 END p_d[8]
 PIN p_d[9]
  DIRECTION OUTPUT ;
  USE SIGNAL ;
  PORT
   LAYER M4 ;
   RECT 0.000 58.032 0.084 58.056 ;
  END
 END p_d[9]
 PIN p_d[10]
  DIRECTION OUTPUT ;
  USE SIGNAL ;
  PORT
   LAYER M4 ;
   RECT 0.000 58.224 0.084 58.248 ;
  END
 END p_d[10]
 PIN p_d[11]
  DIRECTION OUTPUT ;
  USE SIGNAL ;
  PORT
   LAYER M4 ;
   RECT 0.000 58.416 0.084 58.440 ;
  END
 END p_d[11]
 PIN p_d[12]
  DIRECTION OUTPUT ;
  USE SIGNAL ;
  PORT
   LAYER M4 ;
   RECT 0.000 58.608 0.084 58.632 ;
  END
 END p_d[12]
 PIN p_d[13]
  DIRECTION OUTPUT ;
  USE SIGNAL ;
  PORT
   LAYER M4 ;
   RECT 0.000 58.800 0.084 58.824 ;
  END
 END p_d[13]
 PIN p_d[14]
  DIRECTION OUTPUT ;
  USE SIGNAL ;
  PORT
   LAYER M4 ;
   RECT 0.000 58.992 0.084 59.016 ;
  END
 END p_d[14]
 PIN p_d[15]
  DIRECTION OUTPUT ;
  USE SIGNAL ;
  PORT
   LAYER M4 ;
   RECT 0.000 59.184 0.084 59.208 ;
  END
 END p_d[15]
 PIN p_d[16]
  DIRECTION OUTPUT ;
  USE SIGNAL ;
  PORT
   LAYER M4 ;
   RECT 0.000 59.376 0.084 59.400 ;
  END
 END p_d[16]
 PIN p_d[17]
  DIRECTION OUTPUT ;
  USE SIGNAL ;
  PORT
   LAYER M4 ;
   RECT 0.000 59.568 0.084 59.592 ;
  END
 END p_d[17]
 PIN p_d[18]
  DIRECTION OUTPUT ;
  USE SIGNAL ;
  PORT
   LAYER M4 ;
   RECT 0.000 59.760 0.084 59.784 ;
  END
 END p_d[18]
 PIN p_d[19]
  DIRECTION OUTPUT ;
  USE SIGNAL ;
  PORT
   LAYER M4 ;
   RECT 0.000 59.952 0.084 59.976 ;
  END
 END p_d[19]
 PIN p_d[20]
  DIRECTION OUTPUT ;
  USE SIGNAL ;
  PORT
   LAYER M4 ;
   RECT 0.000 60.144 0.084 60.168 ;
  END
 END p_d[20]
 PIN p_d[21]
  DIRECTION OUTPUT ;
  USE SIGNAL ;
  PORT
   LAYER M4 ;
   RECT 0.000 60.336 0.084 60.360 ;
  END
 END p_d[21]
 PIN p_d[22]
  DIRECTION OUTPUT ;
  USE SIGNAL ;
  PORT
   LAYER M4 ;
   RECT 0.000 60.528 0.084 60.552 ;
  END
 END p_d[22]
 PIN p_d[23]
  DIRECTION OUTPUT ;
  USE SIGNAL ;
  PORT
   LAYER M4 ;
   RECT 0.000 60.720 0.084 60.744 ;
  END
 END p_d[23]
 PIN p_d[24]
  DIRECTION OUTPUT ;
  USE SIGNAL ;
  PORT
   LAYER M4 ;
   RECT 0.000 60.912 0.084 60.936 ;
  END
 END p_d[24]
 PIN p_d[25]
  DIRECTION OUTPUT ;
  USE SIGNAL ;
  PORT
   LAYER M4 ;
   RECT 0.000 61.104 0.084 61.128 ;
  END
 END p_d[25]
 PIN p_d[26]
  DIRECTION OUTPUT ;
  USE SIGNAL ;
  PORT
   LAYER M4 ;
   RECT 0.000 61.296 0.084 61.320 ;
  END
 END p_d[26]
 PIN p_d[27]
  DIRECTION OUTPUT ;
  USE SIGNAL ;
  PORT
   LAYER M4 ;
   RECT 0.000 61.488 0.084 61.512 ;
  END
 END p_d[27]
 PIN p_d[28]
  DIRECTION OUTPUT ;
  USE SIGNAL ;
  PORT
   LAYER M4 ;
   RECT 0.000 61.680 0.084 61.704 ;
  END
 END p_d[28]
 PIN p_d[29]
  DIRECTION OUTPUT ;
  USE SIGNAL ;
  PORT
   LAYER M4 ;
   RECT 0.000 61.872 0.084 61.896 ;
  END
 END p_d[29]
 PIN p_d[30]
  DIRECTION OUTPUT ;
  USE SIGNAL ;
  PORT
   LAYER M4 ;
   RECT 0.000 62.064 0.084 62.088 ;
  END
 END p_d[30]
 PIN p_d[31]
  DIRECTION OUTPUT ;
  USE SIGNAL ;
  PORT
   LAYER M4 ;
   RECT 0.000 62.256 0.084 62.280 ;
  END
 END p_d[31]
 PIN p_d[32]
  DIRECTION OUTPUT ;
  USE SIGNAL ;
  PORT
   LAYER M4 ;
   RECT 0.000 62.448 0.084 62.472 ;
  END
 END p_d[32]
 PIN p_d[33]
  DIRECTION OUTPUT ;
  USE SIGNAL ;
  PORT
   LAYER M4 ;
   RECT 0.000 62.640 0.084 62.664 ;
  END
 END p_d[33]
 PIN p_d[34]
  DIRECTION OUTPUT ;
  USE SIGNAL ;
  PORT
   LAYER M4 ;
   RECT 0.000 62.832 0.084 62.856 ;
  END
 END p_d[34]
 PIN p_d[35]
  DIRECTION OUTPUT ;
  USE SIGNAL ;
  PORT
   LAYER M4 ;
   RECT 0.000 63.024 0.084 63.048 ;
  END
 END p_d[35]
 PIN p_d[36]
  DIRECTION OUTPUT ;
  USE SIGNAL ;
  PORT
   LAYER M4 ;
   RECT 0.000 63.216 0.084 63.240 ;
  END
 END p_d[36]
 PIN p_d[37]
  DIRECTION OUTPUT ;
  USE SIGNAL ;
  PORT
   LAYER M4 ;
   RECT 0.000 63.408 0.084 63.432 ;
  END
 END p_d[37]
 PIN p_d[38]
  DIRECTION OUTPUT ;
  USE SIGNAL ;
  PORT
   LAYER M4 ;
   RECT 0.000 63.600 0.084 63.624 ;
  END
 END p_d[38]
 PIN p_d[39]
  DIRECTION OUTPUT ;
  USE SIGNAL ;
  PORT
   LAYER M4 ;
   RECT 0.000 63.792 0.084 63.816 ;
  END
 END p_d[39]
 PIN p_d[40]
  DIRECTION OUTPUT ;
  USE SIGNAL ;
  PORT
   LAYER M4 ;
   RECT 0.000 63.984 0.084 64.008 ;
  END
 END p_d[40]
 PIN p_d[41]
  DIRECTION OUTPUT ;
  USE SIGNAL ;
  PORT
   LAYER M4 ;
   RECT 0.000 64.176 0.084 64.200 ;
  END
 END p_d[41]
 PIN p_d[42]
  DIRECTION OUTPUT ;
  USE SIGNAL ;
  PORT
   LAYER M4 ;
   RECT 0.000 64.368 0.084 64.392 ;
  END
 END p_d[42]
 PIN p_d[43]
  DIRECTION OUTPUT ;
  USE SIGNAL ;
  PORT
   LAYER M4 ;
   RECT 0.000 64.560 0.084 64.584 ;
  END
 END p_d[43]
 PIN p_d[44]
  DIRECTION OUTPUT ;
  USE SIGNAL ;
  PORT
   LAYER M4 ;
   RECT 0.000 64.752 0.084 64.776 ;
  END
 END p_d[44]
 PIN p_d[45]
  DIRECTION OUTPUT ;
  USE SIGNAL ;
  PORT
   LAYER M4 ;
   RECT 0.000 64.944 0.084 64.968 ;
  END
 END p_d[45]
 PIN p_d[46]
  DIRECTION OUTPUT ;
  USE SIGNAL ;
  PORT
   LAYER M4 ;
   RECT 0.000 65.136 0.084 65.160 ;
  END
 END p_d[46]
 PIN p_d[47]
  DIRECTION OUTPUT ;
  USE SIGNAL ;
  PORT
   LAYER M4 ;
   RECT 0.000 65.328 0.084 65.352 ;
  END
 END p_d[47]
 PIN p_d[48]
  DIRECTION OUTPUT ;
  USE SIGNAL ;
  PORT
   LAYER M4 ;
   RECT 0.000 65.520 0.084 65.544 ;
  END
 END p_d[48]
 PIN p_d[49]
  DIRECTION OUTPUT ;
  USE SIGNAL ;
  PORT
   LAYER M4 ;
   RECT 0.000 65.712 0.084 65.736 ;
  END
 END p_d[49]
 PIN p_d[50]
  DIRECTION OUTPUT ;
  USE SIGNAL ;
  PORT
   LAYER M4 ;
   RECT 0.000 65.904 0.084 65.928 ;
  END
 END p_d[50]
 PIN p_d[51]
  DIRECTION OUTPUT ;
  USE SIGNAL ;
  PORT
   LAYER M4 ;
   RECT 0.000 66.096 0.084 66.120 ;
  END
 END p_d[51]
 PIN p_d[52]
  DIRECTION OUTPUT ;
  USE SIGNAL ;
  PORT
   LAYER M4 ;
   RECT 0.000 66.288 0.084 66.312 ;
  END
 END p_d[52]
 PIN p_d[53]
  DIRECTION OUTPUT ;
  USE SIGNAL ;
  PORT
   LAYER M4 ;
   RECT 0.000 66.480 0.084 66.504 ;
  END
 END p_d[53]
 PIN p_d[54]
  DIRECTION OUTPUT ;
  USE SIGNAL ;
  PORT
   LAYER M4 ;
   RECT 0.000 66.672 0.084 66.696 ;
  END
 END p_d[54]
 PIN p_d[55]
  DIRECTION OUTPUT ;
  USE SIGNAL ;
  PORT
   LAYER M4 ;
   RECT 0.000 66.864 0.084 66.888 ;
  END
 END p_d[55]
 PIN p_d[56]
  DIRECTION OUTPUT ;
  USE SIGNAL ;
  PORT
   LAYER M4 ;
   RECT 0.000 67.056 0.084 67.080 ;
  END
 END p_d[56]
 PIN p_d[57]
  DIRECTION OUTPUT ;
  USE SIGNAL ;
  PORT
   LAYER M4 ;
   RECT 0.000 67.248 0.084 67.272 ;
  END
 END p_d[57]
 PIN p_d[58]
  DIRECTION OUTPUT ;
  USE SIGNAL ;
  PORT
   LAYER M4 ;
   RECT 0.000 67.440 0.084 67.464 ;
  END
 END p_d[58]
 PIN p_d[59]
  DIRECTION OUTPUT ;
  USE SIGNAL ;
  PORT
   LAYER M4 ;
   RECT 0.000 67.632 0.084 67.656 ;
  END
 END p_d[59]
 PIN p_d[60]
  DIRECTION OUTPUT ;
  USE SIGNAL ;
  PORT
   LAYER M4 ;
   RECT 0.000 67.824 0.084 67.848 ;
  END
 END p_d[60]
 PIN p_d[61]
  DIRECTION OUTPUT ;
  USE SIGNAL ;
  PORT
   LAYER M4 ;
   RECT 0.000 68.016 0.084 68.040 ;
  END
 END p_d[61]
 PIN p_d[62]
  DIRECTION OUTPUT ;
  USE SIGNAL ;
  PORT
   LAYER M4 ;
   RECT 0.000 68.208 0.084 68.232 ;
  END
 END p_d[62]
 PIN p_d[63]
  DIRECTION OUTPUT ;
  USE SIGNAL ;
  PORT
   LAYER M4 ;
   RECT 0.000 68.400 0.084 68.424 ;
  END
 END p_d[63]
 PIN p_d[64]
  DIRECTION OUTPUT ;
  USE SIGNAL ;
  PORT
   LAYER M4 ;
   RECT 0.000 68.592 0.084 68.616 ;
  END
 END p_d[64]
 PIN p_d[65]
  DIRECTION OUTPUT ;
  USE SIGNAL ;
  PORT
   LAYER M4 ;
   RECT 0.000 68.784 0.084 68.808 ;
  END
 END p_d[65]
 PIN p_d[66]
  DIRECTION OUTPUT ;
  USE SIGNAL ;
  PORT
   LAYER M4 ;
   RECT 0.000 68.976 0.084 69.000 ;
  END
 END p_d[66]
 PIN p_d[67]
  DIRECTION OUTPUT ;
  USE SIGNAL ;
  PORT
   LAYER M4 ;
   RECT 0.000 69.168 0.084 69.192 ;
  END
 END p_d[67]
 PIN p_d[68]
  DIRECTION OUTPUT ;
  USE SIGNAL ;
  PORT
   LAYER M4 ;
   RECT 0.000 69.360 0.084 69.384 ;
  END
 END p_d[68]
 PIN p_d[69]
  DIRECTION OUTPUT ;
  USE SIGNAL ;
  PORT
   LAYER M4 ;
   RECT 0.000 69.552 0.084 69.576 ;
  END
 END p_d[69]
 PIN p_d[70]
  DIRECTION OUTPUT ;
  USE SIGNAL ;
  PORT
   LAYER M4 ;
   RECT 0.000 69.744 0.084 69.768 ;
  END
 END p_d[70]
 PIN p_d[71]
  DIRECTION OUTPUT ;
  USE SIGNAL ;
  PORT
   LAYER M4 ;
   RECT 0.000 69.936 0.084 69.960 ;
  END
 END p_d[71]
 PIN p_d[72]
  DIRECTION OUTPUT ;
  USE SIGNAL ;
  PORT
   LAYER M4 ;
   RECT 0.000 70.128 0.084 70.152 ;
  END
 END p_d[72]
 PIN p_d[73]
  DIRECTION OUTPUT ;
  USE SIGNAL ;
  PORT
   LAYER M4 ;
   RECT 0.000 70.320 0.084 70.344 ;
  END
 END p_d[73]
 PIN p_d[74]
  DIRECTION OUTPUT ;
  USE SIGNAL ;
  PORT
   LAYER M4 ;
   RECT 0.000 70.512 0.084 70.536 ;
  END
 END p_d[74]
 PIN p_d[75]
  DIRECTION OUTPUT ;
  USE SIGNAL ;
  PORT
   LAYER M4 ;
   RECT 0.000 70.704 0.084 70.728 ;
  END
 END p_d[75]
 PIN p_d[76]
  DIRECTION OUTPUT ;
  USE SIGNAL ;
  PORT
   LAYER M4 ;
   RECT 0.000 70.896 0.084 70.920 ;
  END
 END p_d[76]
 PIN p_d[77]
  DIRECTION OUTPUT ;
  USE SIGNAL ;
  PORT
   LAYER M4 ;
   RECT 0.000 71.088 0.084 71.112 ;
  END
 END p_d[77]
 PIN p_d[78]
  DIRECTION OUTPUT ;
  USE SIGNAL ;
  PORT
   LAYER M4 ;
   RECT 0.000 71.280 0.084 71.304 ;
  END
 END p_d[78]
 PIN p_d[79]
  DIRECTION OUTPUT ;
  USE SIGNAL ;
  PORT
   LAYER M4 ;
   RECT 0.000 71.472 0.084 71.496 ;
  END
 END p_d[79]
 PIN p_d[80]
  DIRECTION OUTPUT ;
  USE SIGNAL ;
  PORT
   LAYER M4 ;
   RECT 0.000 71.664 0.084 71.688 ;
  END
 END p_d[80]
 PIN p_d[81]
  DIRECTION OUTPUT ;
  USE SIGNAL ;
  PORT
   LAYER M4 ;
   RECT 0.000 71.856 0.084 71.880 ;
  END
 END p_d[81]
 PIN p_d[82]
  DIRECTION OUTPUT ;
  USE SIGNAL ;
  PORT
   LAYER M4 ;
   RECT 0.000 72.048 0.084 72.072 ;
  END
 END p_d[82]
 PIN p_d[83]
  DIRECTION OUTPUT ;
  USE SIGNAL ;
  PORT
   LAYER M4 ;
   RECT 0.000 72.240 0.084 72.264 ;
  END
 END p_d[83]
 PIN p_d[84]
  DIRECTION OUTPUT ;
  USE SIGNAL ;
  PORT
   LAYER M4 ;
   RECT 0.000 72.432 0.084 72.456 ;
  END
 END p_d[84]
 PIN p_d[85]
  DIRECTION OUTPUT ;
  USE SIGNAL ;
  PORT
   LAYER M4 ;
   RECT 0.000 72.624 0.084 72.648 ;
  END
 END p_d[85]
 PIN p_d[86]
  DIRECTION OUTPUT ;
  USE SIGNAL ;
  PORT
   LAYER M4 ;
   RECT 0.000 72.816 0.084 72.840 ;
  END
 END p_d[86]
 PIN p_d[87]
  DIRECTION OUTPUT ;
  USE SIGNAL ;
  PORT
   LAYER M4 ;
   RECT 0.000 73.008 0.084 73.032 ;
  END
 END p_d[87]
 PIN p_d[88]
  DIRECTION OUTPUT ;
  USE SIGNAL ;
  PORT
   LAYER M4 ;
   RECT 0.000 73.200 0.084 73.224 ;
  END
 END p_d[88]
 PIN p_d[89]
  DIRECTION OUTPUT ;
  USE SIGNAL ;
  PORT
   LAYER M4 ;
   RECT 0.000 73.392 0.084 73.416 ;
  END
 END p_d[89]
 PIN p_d[90]
  DIRECTION OUTPUT ;
  USE SIGNAL ;
  PORT
   LAYER M4 ;
   RECT 0.000 73.584 0.084 73.608 ;
  END
 END p_d[90]
 PIN p_d[91]
  DIRECTION OUTPUT ;
  USE SIGNAL ;
  PORT
   LAYER M4 ;
   RECT 0.000 73.776 0.084 73.800 ;
  END
 END p_d[91]
 PIN p_d[92]
  DIRECTION OUTPUT ;
  USE SIGNAL ;
  PORT
   LAYER M4 ;
   RECT 0.000 73.968 0.084 73.992 ;
  END
 END p_d[92]
 PIN p_d[93]
  DIRECTION OUTPUT ;
  USE SIGNAL ;
  PORT
   LAYER M4 ;
   RECT 0.000 74.160 0.084 74.184 ;
  END
 END p_d[93]
 PIN p_d[94]
  DIRECTION OUTPUT ;
  USE SIGNAL ;
  PORT
   LAYER M4 ;
   RECT 0.000 74.352 0.084 74.376 ;
  END
 END p_d[94]
 PIN p_d[95]
  DIRECTION OUTPUT ;
  USE SIGNAL ;
  PORT
   LAYER M4 ;
   RECT 0.000 74.544 0.084 74.568 ;
  END
 END p_d[95]
 PIN p_d[96]
  DIRECTION OUTPUT ;
  USE SIGNAL ;
  PORT
   LAYER M4 ;
   RECT 0.000 74.736 0.084 74.760 ;
  END
 END p_d[96]
 PIN p_d[97]
  DIRECTION OUTPUT ;
  USE SIGNAL ;
  PORT
   LAYER M4 ;
   RECT 0.000 74.928 0.084 74.952 ;
  END
 END p_d[97]
 PIN p_d[98]
  DIRECTION OUTPUT ;
  USE SIGNAL ;
  PORT
   LAYER M4 ;
   RECT 0.000 75.120 0.084 75.144 ;
  END
 END p_d[98]
 PIN p_d[99]
  DIRECTION OUTPUT ;
  USE SIGNAL ;
  PORT
   LAYER M4 ;
   RECT 0.000 75.312 0.084 75.336 ;
  END
 END p_d[99]
 PIN p_d[100]
  DIRECTION OUTPUT ;
  USE SIGNAL ;
  PORT
   LAYER M4 ;
   RECT 0.000 75.504 0.084 75.528 ;
  END
 END p_d[100]
 PIN p_d[101]
  DIRECTION OUTPUT ;
  USE SIGNAL ;
  PORT
   LAYER M4 ;
   RECT 0.000 75.696 0.084 75.720 ;
  END
 END p_d[101]
 PIN p_d[102]
  DIRECTION OUTPUT ;
  USE SIGNAL ;
  PORT
   LAYER M4 ;
   RECT 0.000 75.888 0.084 75.912 ;
  END
 END p_d[102]
 PIN p_d[103]
  DIRECTION OUTPUT ;
  USE SIGNAL ;
  PORT
   LAYER M4 ;
   RECT 0.000 76.080 0.084 76.104 ;
  END
 END p_d[103]
 PIN p_d[104]
  DIRECTION OUTPUT ;
  USE SIGNAL ;
  PORT
   LAYER M4 ;
   RECT 0.000 76.272 0.084 76.296 ;
  END
 END p_d[104]
 PIN p_d[105]
  DIRECTION OUTPUT ;
  USE SIGNAL ;
  PORT
   LAYER M4 ;
   RECT 0.000 76.464 0.084 76.488 ;
  END
 END p_d[105]
 PIN p_d[106]
  DIRECTION OUTPUT ;
  USE SIGNAL ;
  PORT
   LAYER M4 ;
   RECT 0.000 76.656 0.084 76.680 ;
  END
 END p_d[106]
 PIN p_d[107]
  DIRECTION OUTPUT ;
  USE SIGNAL ;
  PORT
   LAYER M4 ;
   RECT 0.000 76.848 0.084 76.872 ;
  END
 END p_d[107]
 PIN p_d[108]
  DIRECTION OUTPUT ;
  USE SIGNAL ;
  PORT
   LAYER M4 ;
   RECT 0.000 77.040 0.084 77.064 ;
  END
 END p_d[108]
 PIN p_d[109]
  DIRECTION OUTPUT ;
  USE SIGNAL ;
  PORT
   LAYER M4 ;
   RECT 0.000 77.232 0.084 77.256 ;
  END
 END p_d[109]
 PIN p_d[110]
  DIRECTION OUTPUT ;
  USE SIGNAL ;
  PORT
   LAYER M4 ;
   RECT 0.000 77.424 0.084 77.448 ;
  END
 END p_d[110]
 PIN p_d[111]
  DIRECTION OUTPUT ;
  USE SIGNAL ;
  PORT
   LAYER M4 ;
   RECT 0.000 77.616 0.084 77.640 ;
  END
 END p_d[111]
 PIN p_d[112]
  DIRECTION OUTPUT ;
  USE SIGNAL ;
  PORT
   LAYER M4 ;
   RECT 0.000 77.808 0.084 77.832 ;
  END
 END p_d[112]
 PIN p_d[113]
  DIRECTION OUTPUT ;
  USE SIGNAL ;
  PORT
   LAYER M4 ;
   RECT 0.000 78.000 0.084 78.024 ;
  END
 END p_d[113]
 PIN p_d[114]
  DIRECTION OUTPUT ;
  USE SIGNAL ;
  PORT
   LAYER M4 ;
   RECT 0.000 78.192 0.084 78.216 ;
  END
 END p_d[114]
 PIN p_d[115]
  DIRECTION OUTPUT ;
  USE SIGNAL ;
  PORT
   LAYER M4 ;
   RECT 0.000 78.384 0.084 78.408 ;
  END
 END p_d[115]
 PIN p_d[116]
  DIRECTION OUTPUT ;
  USE SIGNAL ;
  PORT
   LAYER M4 ;
   RECT 0.000 78.576 0.084 78.600 ;
  END
 END p_d[116]
 PIN p_d[117]
  DIRECTION OUTPUT ;
  USE SIGNAL ;
  PORT
   LAYER M4 ;
   RECT 0.000 78.768 0.084 78.792 ;
  END
 END p_d[117]
 PIN p_d[118]
  DIRECTION OUTPUT ;
  USE SIGNAL ;
  PORT
   LAYER M4 ;
   RECT 0.000 78.960 0.084 78.984 ;
  END
 END p_d[118]
 PIN p_d[119]
  DIRECTION OUTPUT ;
  USE SIGNAL ;
  PORT
   LAYER M4 ;
   RECT 0.000 79.152 0.084 79.176 ;
  END
 END p_d[119]
 PIN p_d[120]
  DIRECTION OUTPUT ;
  USE SIGNAL ;
  PORT
   LAYER M4 ;
   RECT 0.000 79.344 0.084 79.368 ;
  END
 END p_d[120]
 PIN p_d[121]
  DIRECTION OUTPUT ;
  USE SIGNAL ;
  PORT
   LAYER M4 ;
   RECT 0.000 79.536 0.084 79.560 ;
  END
 END p_d[121]
 PIN p_d[122]
  DIRECTION OUTPUT ;
  USE SIGNAL ;
  PORT
   LAYER M4 ;
   RECT 0.000 79.728 0.084 79.752 ;
  END
 END p_d[122]
 PIN p_d[123]
  DIRECTION OUTPUT ;
  USE SIGNAL ;
  PORT
   LAYER M4 ;
   RECT 0.000 79.920 0.084 79.944 ;
  END
 END p_d[123]
 PIN p_d[124]
  DIRECTION OUTPUT ;
  USE SIGNAL ;
  PORT
   LAYER M4 ;
   RECT 0.000 80.112 0.084 80.136 ;
  END
 END p_d[124]
 PIN p_d[125]
  DIRECTION OUTPUT ;
  USE SIGNAL ;
  PORT
   LAYER M4 ;
   RECT 0.000 80.304 0.084 80.328 ;
  END
 END p_d[125]
 PIN p_d[126]
  DIRECTION OUTPUT ;
  USE SIGNAL ;
  PORT
   LAYER M4 ;
   RECT 0.000 80.496 0.084 80.520 ;
  END
 END p_d[126]
 PIN p_d[127]
  DIRECTION OUTPUT ;
  USE SIGNAL ;
  PORT
   LAYER M4 ;
   RECT 0.000 80.688 0.084 80.712 ;
  END
 END p_d[127]
 PIN p_d[128]
  DIRECTION OUTPUT ;
  USE SIGNAL ;
  PORT
   LAYER M4 ;
   RECT 0.000 80.880 0.084 80.904 ;
  END
 END p_d[128]
 PIN p_d[129]
  DIRECTION OUTPUT ;
  USE SIGNAL ;
  PORT
   LAYER M4 ;
   RECT 0.000 81.072 0.084 81.096 ;
  END
 END p_d[129]
 PIN p_d[130]
  DIRECTION OUTPUT ;
  USE SIGNAL ;
  PORT
   LAYER M4 ;
   RECT 0.000 81.264 0.084 81.288 ;
  END
 END p_d[130]
 PIN p_d[131]
  DIRECTION OUTPUT ;
  USE SIGNAL ;
  PORT
   LAYER M4 ;
   RECT 0.000 81.456 0.084 81.480 ;
  END
 END p_d[131]
 PIN p_d[132]
  DIRECTION OUTPUT ;
  USE SIGNAL ;
  PORT
   LAYER M4 ;
   RECT 0.000 81.648 0.084 81.672 ;
  END
 END p_d[132]
 PIN p_d[133]
  DIRECTION OUTPUT ;
  USE SIGNAL ;
  PORT
   LAYER M4 ;
   RECT 0.000 81.840 0.084 81.864 ;
  END
 END p_d[133]
 PIN p_d[134]
  DIRECTION OUTPUT ;
  USE SIGNAL ;
  PORT
   LAYER M4 ;
   RECT 0.000 82.032 0.084 82.056 ;
  END
 END p_d[134]
 PIN p_d[135]
  DIRECTION OUTPUT ;
  USE SIGNAL ;
  PORT
   LAYER M4 ;
   RECT 0.000 82.224 0.084 82.248 ;
  END
 END p_d[135]
 PIN p_d[136]
  DIRECTION OUTPUT ;
  USE SIGNAL ;
  PORT
   LAYER M4 ;
   RECT 0.000 82.416 0.084 82.440 ;
  END
 END p_d[136]
 PIN p_d[137]
  DIRECTION OUTPUT ;
  USE SIGNAL ;
  PORT
   LAYER M4 ;
   RECT 0.000 82.608 0.084 82.632 ;
  END
 END p_d[137]
 PIN p_d[138]
  DIRECTION OUTPUT ;
  USE SIGNAL ;
  PORT
   LAYER M4 ;
   RECT 0.000 82.800 0.084 82.824 ;
  END
 END p_d[138]
 PIN p_d[139]
  DIRECTION OUTPUT ;
  USE SIGNAL ;
  PORT
   LAYER M4 ;
   RECT 0.000 82.992 0.084 83.016 ;
  END
 END p_d[139]
 PIN p_d[140]
  DIRECTION OUTPUT ;
  USE SIGNAL ;
  PORT
   LAYER M4 ;
   RECT 0.000 83.184 0.084 83.208 ;
  END
 END p_d[140]
 PIN p_d[141]
  DIRECTION OUTPUT ;
  USE SIGNAL ;
  PORT
   LAYER M4 ;
   RECT 0.000 83.376 0.084 83.400 ;
  END
 END p_d[141]
 PIN p_d[142]
  DIRECTION OUTPUT ;
  USE SIGNAL ;
  PORT
   LAYER M4 ;
   RECT 0.000 83.568 0.084 83.592 ;
  END
 END p_d[142]
 PIN p_d[143]
  DIRECTION OUTPUT ;
  USE SIGNAL ;
  PORT
   LAYER M4 ;
   RECT 0.000 83.760 0.084 83.784 ;
  END
 END p_d[143]
 PIN p_d[144]
  DIRECTION OUTPUT ;
  USE SIGNAL ;
  PORT
   LAYER M4 ;
   RECT 0.000 83.952 0.084 83.976 ;
  END
 END p_d[144]
 PIN p_d[145]
  DIRECTION OUTPUT ;
  USE SIGNAL ;
  PORT
   LAYER M4 ;
   RECT 0.000 84.144 0.084 84.168 ;
  END
 END p_d[145]
 PIN p_d[146]
  DIRECTION OUTPUT ;
  USE SIGNAL ;
  PORT
   LAYER M4 ;
   RECT 0.000 84.336 0.084 84.360 ;
  END
 END p_d[146]
 PIN p_d[147]
  DIRECTION OUTPUT ;
  USE SIGNAL ;
  PORT
   LAYER M4 ;
   RECT 0.000 84.528 0.084 84.552 ;
  END
 END p_d[147]
 PIN p_d[148]
  DIRECTION OUTPUT ;
  USE SIGNAL ;
  PORT
   LAYER M4 ;
   RECT 0.000 84.720 0.084 84.744 ;
  END
 END p_d[148]
 PIN p_d[149]
  DIRECTION OUTPUT ;
  USE SIGNAL ;
  PORT
   LAYER M4 ;
   RECT 0.000 84.912 0.084 84.936 ;
  END
 END p_d[149]
 PIN p_d[150]
  DIRECTION OUTPUT ;
  USE SIGNAL ;
  PORT
   LAYER M4 ;
   RECT 0.000 85.104 0.084 85.128 ;
  END
 END p_d[150]
 PIN p_d[151]
  DIRECTION OUTPUT ;
  USE SIGNAL ;
  PORT
   LAYER M4 ;
   RECT 0.000 85.296 0.084 85.320 ;
  END
 END p_d[151]
 PIN p_d[152]
  DIRECTION OUTPUT ;
  USE SIGNAL ;
  PORT
   LAYER M4 ;
   RECT 0.000 85.488 0.084 85.512 ;
  END
 END p_d[152]
 PIN p_d[153]
  DIRECTION OUTPUT ;
  USE SIGNAL ;
  PORT
   LAYER M4 ;
   RECT 0.000 85.680 0.084 85.704 ;
  END
 END p_d[153]
 PIN p_d[154]
  DIRECTION OUTPUT ;
  USE SIGNAL ;
  PORT
   LAYER M4 ;
   RECT 0.000 85.872 0.084 85.896 ;
  END
 END p_d[154]
 PIN p_d[155]
  DIRECTION OUTPUT ;
  USE SIGNAL ;
  PORT
   LAYER M4 ;
   RECT 0.000 86.064 0.084 86.088 ;
  END
 END p_d[155]
 PIN p_d[156]
  DIRECTION OUTPUT ;
  USE SIGNAL ;
  PORT
   LAYER M4 ;
   RECT 0.000 86.256 0.084 86.280 ;
  END
 END p_d[156]
 PIN p_d[157]
  DIRECTION OUTPUT ;
  USE SIGNAL ;
  PORT
   LAYER M4 ;
   RECT 0.000 86.448 0.084 86.472 ;
  END
 END p_d[157]
 PIN p_d[158]
  DIRECTION OUTPUT ;
  USE SIGNAL ;
  PORT
   LAYER M4 ;
   RECT 0.000 86.640 0.084 86.664 ;
  END
 END p_d[158]
 PIN p_d[159]
  DIRECTION OUTPUT ;
  USE SIGNAL ;
  PORT
   LAYER M4 ;
   RECT 0.000 86.832 0.084 86.856 ;
  END
 END p_d[159]
 PIN p_d[160]
  DIRECTION OUTPUT ;
  USE SIGNAL ;
  PORT
   LAYER M4 ;
   RECT 0.000 87.024 0.084 87.048 ;
  END
 END p_d[160]
 PIN p_d[161]
  DIRECTION OUTPUT ;
  USE SIGNAL ;
  PORT
   LAYER M4 ;
   RECT 0.000 87.216 0.084 87.240 ;
  END
 END p_d[161]
 PIN p_d[162]
  DIRECTION OUTPUT ;
  USE SIGNAL ;
  PORT
   LAYER M4 ;
   RECT 0.000 87.408 0.084 87.432 ;
  END
 END p_d[162]
 PIN p_d[163]
  DIRECTION OUTPUT ;
  USE SIGNAL ;
  PORT
   LAYER M4 ;
   RECT 0.000 87.600 0.084 87.624 ;
  END
 END p_d[163]
 PIN p_d[164]
  DIRECTION OUTPUT ;
  USE SIGNAL ;
  PORT
   LAYER M4 ;
   RECT 0.000 87.792 0.084 87.816 ;
  END
 END p_d[164]
 PIN p_d[165]
  DIRECTION OUTPUT ;
  USE SIGNAL ;
  PORT
   LAYER M4 ;
   RECT 0.000 87.984 0.084 88.008 ;
  END
 END p_d[165]
 PIN p_d[166]
  DIRECTION OUTPUT ;
  USE SIGNAL ;
  PORT
   LAYER M4 ;
   RECT 0.000 88.176 0.084 88.200 ;
  END
 END p_d[166]
 PIN p_d[167]
  DIRECTION OUTPUT ;
  USE SIGNAL ;
  PORT
   LAYER M4 ;
   RECT 0.000 88.368 0.084 88.392 ;
  END
 END p_d[167]
 PIN p_d[168]
  DIRECTION OUTPUT ;
  USE SIGNAL ;
  PORT
   LAYER M4 ;
   RECT 0.000 88.560 0.084 88.584 ;
  END
 END p_d[168]
 PIN p_d[169]
  DIRECTION OUTPUT ;
  USE SIGNAL ;
  PORT
   LAYER M4 ;
   RECT 0.000 88.752 0.084 88.776 ;
  END
 END p_d[169]
 PIN p_d[170]
  DIRECTION OUTPUT ;
  USE SIGNAL ;
  PORT
   LAYER M4 ;
   RECT 0.000 88.944 0.084 88.968 ;
  END
 END p_d[170]
 PIN p_d[171]
  DIRECTION OUTPUT ;
  USE SIGNAL ;
  PORT
   LAYER M4 ;
   RECT 0.000 89.136 0.084 89.160 ;
  END
 END p_d[171]
 PIN p_d[172]
  DIRECTION OUTPUT ;
  USE SIGNAL ;
  PORT
   LAYER M4 ;
   RECT 0.000 89.328 0.084 89.352 ;
  END
 END p_d[172]
 PIN p_d[173]
  DIRECTION OUTPUT ;
  USE SIGNAL ;
  PORT
   LAYER M4 ;
   RECT 0.000 89.520 0.084 89.544 ;
  END
 END p_d[173]
 PIN p_d[174]
  DIRECTION OUTPUT ;
  USE SIGNAL ;
  PORT
   LAYER M4 ;
   RECT 0.000 89.712 0.084 89.736 ;
  END
 END p_d[174]
 PIN p_d[175]
  DIRECTION OUTPUT ;
  USE SIGNAL ;
  PORT
   LAYER M4 ;
   RECT 0.000 89.904 0.084 89.928 ;
  END
 END p_d[175]
 PIN p_d[176]
  DIRECTION OUTPUT ;
  USE SIGNAL ;
  PORT
   LAYER M4 ;
   RECT 0.000 90.096 0.084 90.120 ;
  END
 END p_d[176]
 PIN p_d[177]
  DIRECTION OUTPUT ;
  USE SIGNAL ;
  PORT
   LAYER M4 ;
   RECT 0.000 90.288 0.084 90.312 ;
  END
 END p_d[177]
 PIN p_d[178]
  DIRECTION OUTPUT ;
  USE SIGNAL ;
  PORT
   LAYER M4 ;
   RECT 0.000 90.480 0.084 90.504 ;
  END
 END p_d[178]
 PIN p_d[179]
  DIRECTION OUTPUT ;
  USE SIGNAL ;
  PORT
   LAYER M4 ;
   RECT 0.000 90.672 0.084 90.696 ;
  END
 END p_d[179]
 PIN p_d[180]
  DIRECTION OUTPUT ;
  USE SIGNAL ;
  PORT
   LAYER M4 ;
   RECT 0.000 90.864 0.084 90.888 ;
  END
 END p_d[180]
 PIN p_d[181]
  DIRECTION OUTPUT ;
  USE SIGNAL ;
  PORT
   LAYER M4 ;
   RECT 0.000 91.056 0.084 91.080 ;
  END
 END p_d[181]
 PIN p_d[182]
  DIRECTION OUTPUT ;
  USE SIGNAL ;
  PORT
   LAYER M4 ;
   RECT 0.000 91.248 0.084 91.272 ;
  END
 END p_d[182]
 PIN p_d[183]
  DIRECTION OUTPUT ;
  USE SIGNAL ;
  PORT
   LAYER M4 ;
   RECT 0.000 91.440 0.084 91.464 ;
  END
 END p_d[183]
 PIN p_d[184]
  DIRECTION OUTPUT ;
  USE SIGNAL ;
  PORT
   LAYER M4 ;
   RECT 0.000 91.632 0.084 91.656 ;
  END
 END p_d[184]
 PIN p_d[185]
  DIRECTION OUTPUT ;
  USE SIGNAL ;
  PORT
   LAYER M4 ;
   RECT 0.000 91.824 0.084 91.848 ;
  END
 END p_d[185]
 PIN p_d[186]
  DIRECTION OUTPUT ;
  USE SIGNAL ;
  PORT
   LAYER M4 ;
   RECT 0.000 92.016 0.084 92.040 ;
  END
 END p_d[186]
 PIN p_d[187]
  DIRECTION OUTPUT ;
  USE SIGNAL ;
  PORT
   LAYER M4 ;
   RECT 0.000 92.208 0.084 92.232 ;
  END
 END p_d[187]
 PIN p_d[188]
  DIRECTION OUTPUT ;
  USE SIGNAL ;
  PORT
   LAYER M4 ;
   RECT 0.000 92.400 0.084 92.424 ;
  END
 END p_d[188]
 PIN p_d[189]
  DIRECTION OUTPUT ;
  USE SIGNAL ;
  PORT
   LAYER M4 ;
   RECT 0.000 92.592 0.084 92.616 ;
  END
 END p_d[189]
 PIN p_d[190]
  DIRECTION OUTPUT ;
  USE SIGNAL ;
  PORT
   LAYER M4 ;
   RECT 0.000 92.784 0.084 92.808 ;
  END
 END p_d[190]
 PIN p_d[191]
  DIRECTION OUTPUT ;
  USE SIGNAL ;
  PORT
   LAYER M4 ;
   RECT 0.000 92.976 0.084 93.000 ;
  END
 END p_d[191]
 PIN p_d[192]
  DIRECTION OUTPUT ;
  USE SIGNAL ;
  PORT
   LAYER M4 ;
   RECT 0.000 93.168 0.084 93.192 ;
  END
 END p_d[192]
 PIN p_d[193]
  DIRECTION OUTPUT ;
  USE SIGNAL ;
  PORT
   LAYER M4 ;
   RECT 0.000 93.360 0.084 93.384 ;
  END
 END p_d[193]
 PIN p_d[194]
  DIRECTION OUTPUT ;
  USE SIGNAL ;
  PORT
   LAYER M4 ;
   RECT 0.000 93.552 0.084 93.576 ;
  END
 END p_d[194]
 PIN p_d[195]
  DIRECTION OUTPUT ;
  USE SIGNAL ;
  PORT
   LAYER M4 ;
   RECT 0.000 93.744 0.084 93.768 ;
  END
 END p_d[195]
 PIN p_d[196]
  DIRECTION OUTPUT ;
  USE SIGNAL ;
  PORT
   LAYER M4 ;
   RECT 0.000 93.936 0.084 93.960 ;
  END
 END p_d[196]
 PIN p_d[197]
  DIRECTION OUTPUT ;
  USE SIGNAL ;
  PORT
   LAYER M4 ;
   RECT 0.000 94.128 0.084 94.152 ;
  END
 END p_d[197]
 PIN p_d[198]
  DIRECTION OUTPUT ;
  USE SIGNAL ;
  PORT
   LAYER M4 ;
   RECT 0.000 94.320 0.084 94.344 ;
  END
 END p_d[198]
 PIN p_d[199]
  DIRECTION OUTPUT ;
  USE SIGNAL ;
  PORT
   LAYER M4 ;
   RECT 0.000 94.512 0.084 94.536 ;
  END
 END p_d[199]
 PIN p_d[200]
  DIRECTION OUTPUT ;
  USE SIGNAL ;
  PORT
   LAYER M4 ;
   RECT 0.000 94.704 0.084 94.728 ;
  END
 END p_d[200]
 PIN p_d[201]
  DIRECTION OUTPUT ;
  USE SIGNAL ;
  PORT
   LAYER M4 ;
   RECT 0.000 94.896 0.084 94.920 ;
  END
 END p_d[201]
 PIN p_d[202]
  DIRECTION OUTPUT ;
  USE SIGNAL ;
  PORT
   LAYER M4 ;
   RECT 0.000 95.088 0.084 95.112 ;
  END
 END p_d[202]
 PIN p_d[203]
  DIRECTION OUTPUT ;
  USE SIGNAL ;
  PORT
   LAYER M4 ;
   RECT 0.000 95.280 0.084 95.304 ;
  END
 END p_d[203]
 PIN p_d[204]
  DIRECTION OUTPUT ;
  USE SIGNAL ;
  PORT
   LAYER M4 ;
   RECT 0.000 95.472 0.084 95.496 ;
  END
 END p_d[204]
 PIN p_d[205]
  DIRECTION OUTPUT ;
  USE SIGNAL ;
  PORT
   LAYER M4 ;
   RECT 0.000 95.664 0.084 95.688 ;
  END
 END p_d[205]
 PIN p_d[206]
  DIRECTION OUTPUT ;
  USE SIGNAL ;
  PORT
   LAYER M4 ;
   RECT 0.000 95.856 0.084 95.880 ;
  END
 END p_d[206]
 PIN p_d[207]
  DIRECTION OUTPUT ;
  USE SIGNAL ;
  PORT
   LAYER M4 ;
   RECT 0.000 96.048 0.084 96.072 ;
  END
 END p_d[207]
 PIN p_d[208]
  DIRECTION OUTPUT ;
  USE SIGNAL ;
  PORT
   LAYER M4 ;
   RECT 0.000 96.240 0.084 96.264 ;
  END
 END p_d[208]
 PIN p_d[209]
  DIRECTION OUTPUT ;
  USE SIGNAL ;
  PORT
   LAYER M4 ;
   RECT 0.000 96.432 0.084 96.456 ;
  END
 END p_d[209]
 PIN p_d[210]
  DIRECTION OUTPUT ;
  USE SIGNAL ;
  PORT
   LAYER M4 ;
   RECT 0.000 96.624 0.084 96.648 ;
  END
 END p_d[210]
 PIN p_d[211]
  DIRECTION OUTPUT ;
  USE SIGNAL ;
  PORT
   LAYER M4 ;
   RECT 0.000 96.816 0.084 96.840 ;
  END
 END p_d[211]
 PIN p_d[212]
  DIRECTION OUTPUT ;
  USE SIGNAL ;
  PORT
   LAYER M4 ;
   RECT 0.000 97.008 0.084 97.032 ;
  END
 END p_d[212]
 PIN p_d[213]
  DIRECTION OUTPUT ;
  USE SIGNAL ;
  PORT
   LAYER M4 ;
   RECT 0.000 97.200 0.084 97.224 ;
  END
 END p_d[213]
 PIN p_d[214]
  DIRECTION OUTPUT ;
  USE SIGNAL ;
  PORT
   LAYER M4 ;
   RECT 0.000 97.392 0.084 97.416 ;
  END
 END p_d[214]
 PIN p_d[215]
  DIRECTION OUTPUT ;
  USE SIGNAL ;
  PORT
   LAYER M4 ;
   RECT 0.000 97.584 0.084 97.608 ;
  END
 END p_d[215]
 PIN p_d[216]
  DIRECTION OUTPUT ;
  USE SIGNAL ;
  PORT
   LAYER M4 ;
   RECT 0.000 97.776 0.084 97.800 ;
  END
 END p_d[216]
 PIN p_d[217]
  DIRECTION OUTPUT ;
  USE SIGNAL ;
  PORT
   LAYER M4 ;
   RECT 0.000 97.968 0.084 97.992 ;
  END
 END p_d[217]
 PIN p_d[218]
  DIRECTION OUTPUT ;
  USE SIGNAL ;
  PORT
   LAYER M4 ;
   RECT 0.000 98.160 0.084 98.184 ;
  END
 END p_d[218]
 PIN p_d[219]
  DIRECTION OUTPUT ;
  USE SIGNAL ;
  PORT
   LAYER M4 ;
   RECT 0.000 98.352 0.084 98.376 ;
  END
 END p_d[219]
 PIN p_d[220]
  DIRECTION OUTPUT ;
  USE SIGNAL ;
  PORT
   LAYER M4 ;
   RECT 0.000 98.544 0.084 98.568 ;
  END
 END p_d[220]
 PIN p_d[221]
  DIRECTION OUTPUT ;
  USE SIGNAL ;
  PORT
   LAYER M4 ;
   RECT 0.000 98.736 0.084 98.760 ;
  END
 END p_d[221]
 PIN p_d[222]
  DIRECTION OUTPUT ;
  USE SIGNAL ;
  PORT
   LAYER M4 ;
   RECT 0.000 98.928 0.084 98.952 ;
  END
 END p_d[222]
 PIN p_d[223]
  DIRECTION OUTPUT ;
  USE SIGNAL ;
  PORT
   LAYER M4 ;
   RECT 0.000 99.120 0.084 99.144 ;
  END
 END p_d[223]
 PIN p_d[224]
  DIRECTION OUTPUT ;
  USE SIGNAL ;
  PORT
   LAYER M4 ;
   RECT 0.000 99.312 0.084 99.336 ;
  END
 END p_d[224]
 PIN p_d[225]
  DIRECTION OUTPUT ;
  USE SIGNAL ;
  PORT
   LAYER M4 ;
   RECT 0.000 99.504 0.084 99.528 ;
  END
 END p_d[225]
 PIN p_d[226]
  DIRECTION OUTPUT ;
  USE SIGNAL ;
  PORT
   LAYER M4 ;
   RECT 0.000 99.696 0.084 99.720 ;
  END
 END p_d[226]
 PIN p_d[227]
  DIRECTION OUTPUT ;
  USE SIGNAL ;
  PORT
   LAYER M4 ;
   RECT 0.000 99.888 0.084 99.912 ;
  END
 END p_d[227]
 PIN p_d[228]
  DIRECTION OUTPUT ;
  USE SIGNAL ;
  PORT
   LAYER M4 ;
   RECT 0.000 100.080 0.084 100.104 ;
  END
 END p_d[228]
 PIN p_d[229]
  DIRECTION OUTPUT ;
  USE SIGNAL ;
  PORT
   LAYER M4 ;
   RECT 0.000 100.272 0.084 100.296 ;
  END
 END p_d[229]
 PIN p_d[230]
  DIRECTION OUTPUT ;
  USE SIGNAL ;
  PORT
   LAYER M4 ;
   RECT 0.000 100.464 0.084 100.488 ;
  END
 END p_d[230]
 PIN p_d[231]
  DIRECTION OUTPUT ;
  USE SIGNAL ;
  PORT
   LAYER M4 ;
   RECT 0.000 100.656 0.084 100.680 ;
  END
 END p_d[231]
 PIN p_d[232]
  DIRECTION OUTPUT ;
  USE SIGNAL ;
  PORT
   LAYER M4 ;
   RECT 0.000 100.848 0.084 100.872 ;
  END
 END p_d[232]
 PIN p_d[233]
  DIRECTION OUTPUT ;
  USE SIGNAL ;
  PORT
   LAYER M4 ;
   RECT 0.000 101.040 0.084 101.064 ;
  END
 END p_d[233]
 PIN p_d[234]
  DIRECTION OUTPUT ;
  USE SIGNAL ;
  PORT
   LAYER M4 ;
   RECT 0.000 101.232 0.084 101.256 ;
  END
 END p_d[234]
 PIN p_d[235]
  DIRECTION OUTPUT ;
  USE SIGNAL ;
  PORT
   LAYER M4 ;
   RECT 0.000 101.424 0.084 101.448 ;
  END
 END p_d[235]
 PIN p_d[236]
  DIRECTION OUTPUT ;
  USE SIGNAL ;
  PORT
   LAYER M4 ;
   RECT 0.000 101.616 0.084 101.640 ;
  END
 END p_d[236]
 PIN p_d[237]
  DIRECTION OUTPUT ;
  USE SIGNAL ;
  PORT
   LAYER M4 ;
   RECT 0.000 101.808 0.084 101.832 ;
  END
 END p_d[237]
 PIN p_d[238]
  DIRECTION OUTPUT ;
  USE SIGNAL ;
  PORT
   LAYER M4 ;
   RECT 0.000 102.000 0.084 102.024 ;
  END
 END p_d[238]
 PIN p_d[239]
  DIRECTION OUTPUT ;
  USE SIGNAL ;
  PORT
   LAYER M4 ;
   RECT 0.000 102.192 0.084 102.216 ;
  END
 END p_d[239]
 PIN p_d[240]
  DIRECTION OUTPUT ;
  USE SIGNAL ;
  PORT
   LAYER M4 ;
   RECT 0.000 102.384 0.084 102.408 ;
  END
 END p_d[240]
 PIN p_d[241]
  DIRECTION OUTPUT ;
  USE SIGNAL ;
  PORT
   LAYER M4 ;
   RECT 0.000 102.576 0.084 102.600 ;
  END
 END p_d[241]
 PIN p_d[242]
  DIRECTION OUTPUT ;
  USE SIGNAL ;
  PORT
   LAYER M4 ;
   RECT 0.000 102.768 0.084 102.792 ;
  END
 END p_d[242]
 PIN p_d[243]
  DIRECTION OUTPUT ;
  USE SIGNAL ;
  PORT
   LAYER M4 ;
   RECT 0.000 102.960 0.084 102.984 ;
  END
 END p_d[243]
 PIN p_d[244]
  DIRECTION OUTPUT ;
  USE SIGNAL ;
  PORT
   LAYER M4 ;
   RECT 0.000 103.152 0.084 103.176 ;
  END
 END p_d[244]
 PIN p_d[245]
  DIRECTION OUTPUT ;
  USE SIGNAL ;
  PORT
   LAYER M4 ;
   RECT 0.000 103.344 0.084 103.368 ;
  END
 END p_d[245]
 PIN p_d[246]
  DIRECTION OUTPUT ;
  USE SIGNAL ;
  PORT
   LAYER M4 ;
   RECT 0.000 103.536 0.084 103.560 ;
  END
 END p_d[246]
 PIN p_d[247]
  DIRECTION OUTPUT ;
  USE SIGNAL ;
  PORT
   LAYER M4 ;
   RECT 0.000 103.728 0.084 103.752 ;
  END
 END p_d[247]
 PIN p_d[248]
  DIRECTION OUTPUT ;
  USE SIGNAL ;
  PORT
   LAYER M4 ;
   RECT 0.000 103.920 0.084 103.944 ;
  END
 END p_d[248]
 PIN p_d[249]
  DIRECTION OUTPUT ;
  USE SIGNAL ;
  PORT
   LAYER M4 ;
   RECT 0.000 104.112 0.084 104.136 ;
  END
 END p_d[249]
 PIN p_d[250]
  DIRECTION OUTPUT ;
  USE SIGNAL ;
  PORT
   LAYER M4 ;
   RECT 0.000 104.304 0.084 104.328 ;
  END
 END p_d[250]
 PIN p_d[251]
  DIRECTION OUTPUT ;
  USE SIGNAL ;
  PORT
   LAYER M4 ;
   RECT 0.000 104.496 0.084 104.520 ;
  END
 END p_d[251]
 PIN p_d[252]
  DIRECTION OUTPUT ;
  USE SIGNAL ;
  PORT
   LAYER M4 ;
   RECT 0.000 104.688 0.084 104.712 ;
  END
 END p_d[252]
 PIN p_d[253]
  DIRECTION OUTPUT ;
  USE SIGNAL ;
  PORT
   LAYER M4 ;
   RECT 0.000 104.880 0.084 104.904 ;
  END
 END p_d[253]
 PIN p_d[254]
  DIRECTION OUTPUT ;
  USE SIGNAL ;
  PORT
   LAYER M4 ;
   RECT 0.000 105.072 0.084 105.096 ;
  END
 END p_d[254]
 PIN p_d[255]
  DIRECTION OUTPUT ;
  USE SIGNAL ;
  PORT
   LAYER M4 ;
   RECT 0.000 105.264 0.084 105.288 ;
  END
 END p_d[255]
 PIN p_d[256]
  DIRECTION OUTPUT ;
  USE SIGNAL ;
  PORT
   LAYER M4 ;
   RECT 0.000 105.456 0.084 105.480 ;
  END
 END p_d[256]
 PIN p_d[257]
  DIRECTION OUTPUT ;
  USE SIGNAL ;
  PORT
   LAYER M4 ;
   RECT 0.000 105.648 0.084 105.672 ;
  END
 END p_d[257]
 PIN p_d[258]
  DIRECTION OUTPUT ;
  USE SIGNAL ;
  PORT
   LAYER M4 ;
   RECT 0.000 105.840 0.084 105.864 ;
  END
 END p_d[258]
 PIN p_d[259]
  DIRECTION OUTPUT ;
  USE SIGNAL ;
  PORT
   LAYER M4 ;
   RECT 0.000 106.032 0.084 106.056 ;
  END
 END p_d[259]
 PIN p_d[260]
  DIRECTION OUTPUT ;
  USE SIGNAL ;
  PORT
   LAYER M4 ;
   RECT 0.000 106.224 0.084 106.248 ;
  END
 END p_d[260]
 PIN p_d[261]
  DIRECTION OUTPUT ;
  USE SIGNAL ;
  PORT
   LAYER M4 ;
   RECT 0.000 106.416 0.084 106.440 ;
  END
 END p_d[261]
 PIN p_d[262]
  DIRECTION OUTPUT ;
  USE SIGNAL ;
  PORT
   LAYER M4 ;
   RECT 0.000 106.608 0.084 106.632 ;
  END
 END p_d[262]
 PIN p_d[263]
  DIRECTION OUTPUT ;
  USE SIGNAL ;
  PORT
   LAYER M4 ;
   RECT 0.000 106.800 0.084 106.824 ;
  END
 END p_d[263]
 PIN p_d[264]
  DIRECTION OUTPUT ;
  USE SIGNAL ;
  PORT
   LAYER M4 ;
   RECT 0.000 106.992 0.084 107.016 ;
  END
 END p_d[264]
 PIN p_d[265]
  DIRECTION OUTPUT ;
  USE SIGNAL ;
  PORT
   LAYER M4 ;
   RECT 0.000 107.184 0.084 107.208 ;
  END
 END p_d[265]
 PIN p_d[266]
  DIRECTION OUTPUT ;
  USE SIGNAL ;
  PORT
   LAYER M4 ;
   RECT 0.000 107.376 0.084 107.400 ;
  END
 END p_d[266]
 PIN p_d[267]
  DIRECTION OUTPUT ;
  USE SIGNAL ;
  PORT
   LAYER M4 ;
   RECT 0.000 107.568 0.084 107.592 ;
  END
 END p_d[267]
 PIN p_d[268]
  DIRECTION OUTPUT ;
  USE SIGNAL ;
  PORT
   LAYER M4 ;
   RECT 0.000 107.760 0.084 107.784 ;
  END
 END p_d[268]
 PIN p_d[269]
  DIRECTION OUTPUT ;
  USE SIGNAL ;
  PORT
   LAYER M4 ;
   RECT 0.000 107.952 0.084 107.976 ;
  END
 END p_d[269]
 PIN p_d[270]
  DIRECTION OUTPUT ;
  USE SIGNAL ;
  PORT
   LAYER M4 ;
   RECT 0.000 108.144 0.084 108.168 ;
  END
 END p_d[270]
 PIN p_d[271]
  DIRECTION OUTPUT ;
  USE SIGNAL ;
  PORT
   LAYER M4 ;
   RECT 0.000 108.336 0.084 108.360 ;
  END
 END p_d[271]
 PIN p_d[272]
  DIRECTION OUTPUT ;
  USE SIGNAL ;
  PORT
   LAYER M4 ;
   RECT 0.000 108.528 0.084 108.552 ;
  END
 END p_d[272]
 PIN p_d[273]
  DIRECTION OUTPUT ;
  USE SIGNAL ;
  PORT
   LAYER M4 ;
   RECT 0.000 108.720 0.084 108.744 ;
  END
 END p_d[273]
 PIN p_d[274]
  DIRECTION OUTPUT ;
  USE SIGNAL ;
  PORT
   LAYER M4 ;
   RECT 0.000 108.912 0.084 108.936 ;
  END
 END p_d[274]
 PIN p_d[275]
  DIRECTION OUTPUT ;
  USE SIGNAL ;
  PORT
   LAYER M4 ;
   RECT 0.000 109.104 0.084 109.128 ;
  END
 END p_d[275]
 PIN p_d[276]
  DIRECTION OUTPUT ;
  USE SIGNAL ;
  PORT
   LAYER M4 ;
   RECT 0.000 109.296 0.084 109.320 ;
  END
 END p_d[276]
 PIN p_d[277]
  DIRECTION OUTPUT ;
  USE SIGNAL ;
  PORT
   LAYER M4 ;
   RECT 0.000 109.488 0.084 109.512 ;
  END
 END p_d[277]
 PIN p_d[278]
  DIRECTION OUTPUT ;
  USE SIGNAL ;
  PORT
   LAYER M4 ;
   RECT 0.000 109.680 0.084 109.704 ;
  END
 END p_d[278]
 PIN p_d[279]
  DIRECTION OUTPUT ;
  USE SIGNAL ;
  PORT
   LAYER M4 ;
   RECT 0.000 109.872 0.084 109.896 ;
  END
 END p_d[279]
 PIN p_d[280]
  DIRECTION OUTPUT ;
  USE SIGNAL ;
  PORT
   LAYER M4 ;
   RECT 0.000 110.064 0.084 110.088 ;
  END
 END p_d[280]
 PIN p_d[281]
  DIRECTION OUTPUT ;
  USE SIGNAL ;
  PORT
   LAYER M4 ;
   RECT 0.000 110.256 0.084 110.280 ;
  END
 END p_d[281]
 PIN p_d[282]
  DIRECTION OUTPUT ;
  USE SIGNAL ;
  PORT
   LAYER M4 ;
   RECT 0.000 110.448 0.084 110.472 ;
  END
 END p_d[282]
 PIN p_d[283]
  DIRECTION OUTPUT ;
  USE SIGNAL ;
  PORT
   LAYER M4 ;
   RECT 0.000 110.640 0.084 110.664 ;
  END
 END p_d[283]
 PIN p_d[284]
  DIRECTION OUTPUT ;
  USE SIGNAL ;
  PORT
   LAYER M4 ;
   RECT 0.000 110.832 0.084 110.856 ;
  END
 END p_d[284]
 PIN p_d[285]
  DIRECTION OUTPUT ;
  USE SIGNAL ;
  PORT
   LAYER M4 ;
   RECT 0.000 111.024 0.084 111.048 ;
  END
 END p_d[285]
 PIN p_d[286]
  DIRECTION OUTPUT ;
  USE SIGNAL ;
  PORT
   LAYER M4 ;
   RECT 0.000 111.216 0.084 111.240 ;
  END
 END p_d[286]
 PIN p_d[287]
  DIRECTION OUTPUT ;
  USE SIGNAL ;
  PORT
   LAYER M4 ;
   RECT 0.000 111.408 0.084 111.432 ;
  END
 END p_d[287]
 PIN p_d[288]
  DIRECTION OUTPUT ;
  USE SIGNAL ;
  PORT
   LAYER M4 ;
   RECT 0.000 111.600 0.084 111.624 ;
  END
 END p_d[288]
 PIN p_d[289]
  DIRECTION OUTPUT ;
  USE SIGNAL ;
  PORT
   LAYER M4 ;
   RECT 0.000 111.792 0.084 111.816 ;
  END
 END p_d[289]
 PIN p_d[290]
  DIRECTION OUTPUT ;
  USE SIGNAL ;
  PORT
   LAYER M4 ;
   RECT 0.000 111.984 0.084 112.008 ;
  END
 END p_d[290]
 PIN p_d[291]
  DIRECTION OUTPUT ;
  USE SIGNAL ;
  PORT
   LAYER M4 ;
   RECT 0.000 112.176 0.084 112.200 ;
  END
 END p_d[291]
 PIN p_d[292]
  DIRECTION OUTPUT ;
  USE SIGNAL ;
  PORT
   LAYER M4 ;
   RECT 0.000 112.368 0.084 112.392 ;
  END
 END p_d[292]
 PIN p_d[293]
  DIRECTION OUTPUT ;
  USE SIGNAL ;
  PORT
   LAYER M4 ;
   RECT 0.000 112.560 0.084 112.584 ;
  END
 END p_d[293]
 PIN p_d[294]
  DIRECTION OUTPUT ;
  USE SIGNAL ;
  PORT
   LAYER M4 ;
   RECT 0.000 112.752 0.084 112.776 ;
  END
 END p_d[294]
 PIN p_d[295]
  DIRECTION OUTPUT ;
  USE SIGNAL ;
  PORT
   LAYER M4 ;
   RECT 0.000 112.944 0.084 112.968 ;
  END
 END p_d[295]
 PIN p_d[296]
  DIRECTION OUTPUT ;
  USE SIGNAL ;
  PORT
   LAYER M4 ;
   RECT 0.000 113.136 0.084 113.160 ;
  END
 END p_d[296]
 PIN p_d[297]
  DIRECTION OUTPUT ;
  USE SIGNAL ;
  PORT
   LAYER M4 ;
   RECT 0.000 113.328 0.084 113.352 ;
  END
 END p_d[297]
 PIN p_d[298]
  DIRECTION OUTPUT ;
  USE SIGNAL ;
  PORT
   LAYER M4 ;
   RECT 0.000 113.520 0.084 113.544 ;
  END
 END p_d[298]
 PIN p_d[299]
  DIRECTION OUTPUT ;
  USE SIGNAL ;
  PORT
   LAYER M4 ;
   RECT 0.000 113.712 0.084 113.736 ;
  END
 END p_d[299]
 PIN p_d[300]
  DIRECTION OUTPUT ;
  USE SIGNAL ;
  PORT
   LAYER M4 ;
   RECT 0.000 113.904 0.084 113.928 ;
  END
 END p_d[300]
 PIN p_d[301]
  DIRECTION OUTPUT ;
  USE SIGNAL ;
  PORT
   LAYER M4 ;
   RECT 0.000 114.096 0.084 114.120 ;
  END
 END p_d[301]
 PIN p_d[302]
  DIRECTION OUTPUT ;
  USE SIGNAL ;
  PORT
   LAYER M4 ;
   RECT 0.000 114.288 0.084 114.312 ;
  END
 END p_d[302]
 PIN p_d[303]
  DIRECTION OUTPUT ;
  USE SIGNAL ;
  PORT
   LAYER M4 ;
   RECT 0.000 114.480 0.084 114.504 ;
  END
 END p_d[303]
 PIN p_d[304]
  DIRECTION OUTPUT ;
  USE SIGNAL ;
  PORT
   LAYER M4 ;
   RECT 0.000 114.672 0.084 114.696 ;
  END
 END p_d[304]
 PIN p_d[305]
  DIRECTION OUTPUT ;
  USE SIGNAL ;
  PORT
   LAYER M4 ;
   RECT 0.000 114.864 0.084 114.888 ;
  END
 END p_d[305]
 PIN p_d[306]
  DIRECTION OUTPUT ;
  USE SIGNAL ;
  PORT
   LAYER M4 ;
   RECT 0.000 115.056 0.084 115.080 ;
  END
 END p_d[306]
 PIN p_d[307]
  DIRECTION OUTPUT ;
  USE SIGNAL ;
  PORT
   LAYER M4 ;
   RECT 0.000 115.248 0.084 115.272 ;
  END
 END p_d[307]
 PIN p_d[308]
  DIRECTION OUTPUT ;
  USE SIGNAL ;
  PORT
   LAYER M4 ;
   RECT 0.000 115.440 0.084 115.464 ;
  END
 END p_d[308]
 PIN p_d[309]
  DIRECTION OUTPUT ;
  USE SIGNAL ;
  PORT
   LAYER M4 ;
   RECT 0.000 115.632 0.084 115.656 ;
  END
 END p_d[309]
 PIN p_d[310]
  DIRECTION OUTPUT ;
  USE SIGNAL ;
  PORT
   LAYER M4 ;
   RECT 0.000 115.824 0.084 115.848 ;
  END
 END p_d[310]
 PIN p_d[311]
  DIRECTION OUTPUT ;
  USE SIGNAL ;
  PORT
   LAYER M4 ;
   RECT 0.000 116.016 0.084 116.040 ;
  END
 END p_d[311]
 PIN p_d[312]
  DIRECTION OUTPUT ;
  USE SIGNAL ;
  PORT
   LAYER M4 ;
   RECT 0.000 116.208 0.084 116.232 ;
  END
 END p_d[312]
 PIN p_d[313]
  DIRECTION OUTPUT ;
  USE SIGNAL ;
  PORT
   LAYER M4 ;
   RECT 0.000 116.400 0.084 116.424 ;
  END
 END p_d[313]
 PIN p_d[314]
  DIRECTION OUTPUT ;
  USE SIGNAL ;
  PORT
   LAYER M4 ;
   RECT 0.000 116.592 0.084 116.616 ;
  END
 END p_d[314]
 PIN p_d[315]
  DIRECTION OUTPUT ;
  USE SIGNAL ;
  PORT
   LAYER M4 ;
   RECT 0.000 116.784 0.084 116.808 ;
  END
 END p_d[315]
 PIN p_d[316]
  DIRECTION OUTPUT ;
  USE SIGNAL ;
  PORT
   LAYER M4 ;
   RECT 0.000 116.976 0.084 117.000 ;
  END
 END p_d[316]
 PIN p_d[317]
  DIRECTION OUTPUT ;
  USE SIGNAL ;
  PORT
   LAYER M4 ;
   RECT 0.000 117.168 0.084 117.192 ;
  END
 END p_d[317]
 PIN p_d[318]
  DIRECTION OUTPUT ;
  USE SIGNAL ;
  PORT
   LAYER M4 ;
   RECT 0.000 117.360 0.084 117.384 ;
  END
 END p_d[318]
 PIN p_d[319]
  DIRECTION OUTPUT ;
  USE SIGNAL ;
  PORT
   LAYER M4 ;
   RECT 0.000 117.552 0.084 117.576 ;
  END
 END p_d[319]
 PIN p_d[320]
  DIRECTION OUTPUT ;
  USE SIGNAL ;
  PORT
   LAYER M4 ;
   RECT 0.000 117.744 0.084 117.768 ;
  END
 END p_d[320]
 PIN p_d[321]
  DIRECTION OUTPUT ;
  USE SIGNAL ;
  PORT
   LAYER M4 ;
   RECT 0.000 117.936 0.084 117.960 ;
  END
 END p_d[321]
 PIN p_d[322]
  DIRECTION OUTPUT ;
  USE SIGNAL ;
  PORT
   LAYER M4 ;
   RECT 0.000 118.128 0.084 118.152 ;
  END
 END p_d[322]
 PIN p_d[323]
  DIRECTION OUTPUT ;
  USE SIGNAL ;
  PORT
   LAYER M4 ;
   RECT 0.000 118.320 0.084 118.344 ;
  END
 END p_d[323]
 PIN p_d[324]
  DIRECTION OUTPUT ;
  USE SIGNAL ;
  PORT
   LAYER M4 ;
   RECT 0.000 118.512 0.084 118.536 ;
  END
 END p_d[324]
 PIN p_d[325]
  DIRECTION OUTPUT ;
  USE SIGNAL ;
  PORT
   LAYER M4 ;
   RECT 0.000 118.704 0.084 118.728 ;
  END
 END p_d[325]
 PIN p_d[326]
  DIRECTION OUTPUT ;
  USE SIGNAL ;
  PORT
   LAYER M4 ;
   RECT 0.000 118.896 0.084 118.920 ;
  END
 END p_d[326]
 PIN p_d[327]
  DIRECTION OUTPUT ;
  USE SIGNAL ;
  PORT
   LAYER M4 ;
   RECT 0.000 119.088 0.084 119.112 ;
  END
 END p_d[327]
 PIN p_d[328]
  DIRECTION OUTPUT ;
  USE SIGNAL ;
  PORT
   LAYER M4 ;
   RECT 0.000 119.280 0.084 119.304 ;
  END
 END p_d[328]
 PIN p_d[329]
  DIRECTION OUTPUT ;
  USE SIGNAL ;
  PORT
   LAYER M4 ;
   RECT 0.000 119.472 0.084 119.496 ;
  END
 END p_d[329]
 PIN p_d[330]
  DIRECTION OUTPUT ;
  USE SIGNAL ;
  PORT
   LAYER M4 ;
   RECT 0.000 119.664 0.084 119.688 ;
  END
 END p_d[330]
 PIN p_d[331]
  DIRECTION OUTPUT ;
  USE SIGNAL ;
  PORT
   LAYER M4 ;
   RECT 0.000 119.856 0.084 119.880 ;
  END
 END p_d[331]
 PIN p_d[332]
  DIRECTION OUTPUT ;
  USE SIGNAL ;
  PORT
   LAYER M4 ;
   RECT 0.000 120.048 0.084 120.072 ;
  END
 END p_d[332]
 PIN p_d[333]
  DIRECTION OUTPUT ;
  USE SIGNAL ;
  PORT
   LAYER M4 ;
   RECT 0.000 120.240 0.084 120.264 ;
  END
 END p_d[333]
 PIN p_d[334]
  DIRECTION OUTPUT ;
  USE SIGNAL ;
  PORT
   LAYER M4 ;
   RECT 0.000 120.432 0.084 120.456 ;
  END
 END p_d[334]
 PIN p_d[335]
  DIRECTION OUTPUT ;
  USE SIGNAL ;
  PORT
   LAYER M4 ;
   RECT 0.000 120.624 0.084 120.648 ;
  END
 END p_d[335]
 PIN p_d[336]
  DIRECTION OUTPUT ;
  USE SIGNAL ;
  PORT
   LAYER M4 ;
   RECT 0.000 120.816 0.084 120.840 ;
  END
 END p_d[336]
 PIN p_d[337]
  DIRECTION OUTPUT ;
  USE SIGNAL ;
  PORT
   LAYER M4 ;
   RECT 0.000 121.008 0.084 121.032 ;
  END
 END p_d[337]
 PIN p_d[338]
  DIRECTION OUTPUT ;
  USE SIGNAL ;
  PORT
   LAYER M4 ;
   RECT 0.000 121.200 0.084 121.224 ;
  END
 END p_d[338]
 PIN p_d[339]
  DIRECTION OUTPUT ;
  USE SIGNAL ;
  PORT
   LAYER M4 ;
   RECT 0.000 121.392 0.084 121.416 ;
  END
 END p_d[339]
 PIN p_d[340]
  DIRECTION OUTPUT ;
  USE SIGNAL ;
  PORT
   LAYER M4 ;
   RECT 0.000 121.584 0.084 121.608 ;
  END
 END p_d[340]
 PIN p_d[341]
  DIRECTION OUTPUT ;
  USE SIGNAL ;
  PORT
   LAYER M4 ;
   RECT 0.000 121.776 0.084 121.800 ;
  END
 END p_d[341]
 PIN p_d[342]
  DIRECTION OUTPUT ;
  USE SIGNAL ;
  PORT
   LAYER M4 ;
   RECT 0.000 121.968 0.084 121.992 ;
  END
 END p_d[342]
 PIN p_d[343]
  DIRECTION OUTPUT ;
  USE SIGNAL ;
  PORT
   LAYER M4 ;
   RECT 0.000 122.160 0.084 122.184 ;
  END
 END p_d[343]
 PIN p_d[344]
  DIRECTION OUTPUT ;
  USE SIGNAL ;
  PORT
   LAYER M4 ;
   RECT 0.000 122.352 0.084 122.376 ;
  END
 END p_d[344]
 PIN p_d[345]
  DIRECTION OUTPUT ;
  USE SIGNAL ;
  PORT
   LAYER M4 ;
   RECT 0.000 122.544 0.084 122.568 ;
  END
 END p_d[345]
 PIN p_d[346]
  DIRECTION OUTPUT ;
  USE SIGNAL ;
  PORT
   LAYER M4 ;
   RECT 0.000 122.736 0.084 122.760 ;
  END
 END p_d[346]
 PIN p_d[347]
  DIRECTION OUTPUT ;
  USE SIGNAL ;
  PORT
   LAYER M4 ;
   RECT 0.000 122.928 0.084 122.952 ;
  END
 END p_d[347]
 PIN p_d[348]
  DIRECTION OUTPUT ;
  USE SIGNAL ;
  PORT
   LAYER M4 ;
   RECT 0.000 123.120 0.084 123.144 ;
  END
 END p_d[348]
 PIN p_d[349]
  DIRECTION OUTPUT ;
  USE SIGNAL ;
  PORT
   LAYER M4 ;
   RECT 0.000 123.312 0.084 123.336 ;
  END
 END p_d[349]
 PIN p_d[350]
  DIRECTION OUTPUT ;
  USE SIGNAL ;
  PORT
   LAYER M4 ;
   RECT 0.000 123.504 0.084 123.528 ;
  END
 END p_d[350]
 PIN p_d[351]
  DIRECTION OUTPUT ;
  USE SIGNAL ;
  PORT
   LAYER M4 ;
   RECT 0.000 123.696 0.084 123.720 ;
  END
 END p_d[351]
 PIN p_d[352]
  DIRECTION OUTPUT ;
  USE SIGNAL ;
  PORT
   LAYER M4 ;
   RECT 0.000 123.888 0.084 123.912 ;
  END
 END p_d[352]
 PIN p_d[353]
  DIRECTION OUTPUT ;
  USE SIGNAL ;
  PORT
   LAYER M4 ;
   RECT 0.000 124.080 0.084 124.104 ;
  END
 END p_d[353]
 PIN p_d[354]
  DIRECTION OUTPUT ;
  USE SIGNAL ;
  PORT
   LAYER M4 ;
   RECT 0.000 124.272 0.084 124.296 ;
  END
 END p_d[354]
 PIN p_d[355]
  DIRECTION OUTPUT ;
  USE SIGNAL ;
  PORT
   LAYER M4 ;
   RECT 0.000 124.464 0.084 124.488 ;
  END
 END p_d[355]
 PIN p_d[356]
  DIRECTION OUTPUT ;
  USE SIGNAL ;
  PORT
   LAYER M4 ;
   RECT 0.000 124.656 0.084 124.680 ;
  END
 END p_d[356]
 PIN p_d[357]
  DIRECTION OUTPUT ;
  USE SIGNAL ;
  PORT
   LAYER M4 ;
   RECT 0.000 124.848 0.084 124.872 ;
  END
 END p_d[357]
 PIN p_d[358]
  DIRECTION OUTPUT ;
  USE SIGNAL ;
  PORT
   LAYER M4 ;
   RECT 0.000 125.040 0.084 125.064 ;
  END
 END p_d[358]
 PIN p_d[359]
  DIRECTION OUTPUT ;
  USE SIGNAL ;
  PORT
   LAYER M4 ;
   RECT 0.000 125.232 0.084 125.256 ;
  END
 END p_d[359]
 PIN p_d[360]
  DIRECTION OUTPUT ;
  USE SIGNAL ;
  PORT
   LAYER M4 ;
   RECT 0.000 125.424 0.084 125.448 ;
  END
 END p_d[360]
 PIN p_d[361]
  DIRECTION OUTPUT ;
  USE SIGNAL ;
  PORT
   LAYER M4 ;
   RECT 0.000 125.616 0.084 125.640 ;
  END
 END p_d[361]
 PIN p_d[362]
  DIRECTION OUTPUT ;
  USE SIGNAL ;
  PORT
   LAYER M4 ;
   RECT 0.000 125.808 0.084 125.832 ;
  END
 END p_d[362]
 PIN p_d[363]
  DIRECTION OUTPUT ;
  USE SIGNAL ;
  PORT
   LAYER M4 ;
   RECT 0.000 126.000 0.084 126.024 ;
  END
 END p_d[363]
 PIN p_d[364]
  DIRECTION OUTPUT ;
  USE SIGNAL ;
  PORT
   LAYER M4 ;
   RECT 0.000 126.192 0.084 126.216 ;
  END
 END p_d[364]
 PIN p_d[365]
  DIRECTION OUTPUT ;
  USE SIGNAL ;
  PORT
   LAYER M4 ;
   RECT 0.000 126.384 0.084 126.408 ;
  END
 END p_d[365]
 PIN p_d[366]
  DIRECTION OUTPUT ;
  USE SIGNAL ;
  PORT
   LAYER M4 ;
   RECT 0.000 126.576 0.084 126.600 ;
  END
 END p_d[366]
 PIN p_d[367]
  DIRECTION OUTPUT ;
  USE SIGNAL ;
  PORT
   LAYER M4 ;
   RECT 0.000 126.768 0.084 126.792 ;
  END
 END p_d[367]
 PIN p_d[368]
  DIRECTION OUTPUT ;
  USE SIGNAL ;
  PORT
   LAYER M4 ;
   RECT 0.000 126.960 0.084 126.984 ;
  END
 END p_d[368]
 PIN p_d[369]
  DIRECTION OUTPUT ;
  USE SIGNAL ;
  PORT
   LAYER M4 ;
   RECT 0.000 127.152 0.084 127.176 ;
  END
 END p_d[369]
 PIN p_d[370]
  DIRECTION OUTPUT ;
  USE SIGNAL ;
  PORT
   LAYER M4 ;
   RECT 0.000 127.344 0.084 127.368 ;
  END
 END p_d[370]
 PIN p_d[371]
  DIRECTION OUTPUT ;
  USE SIGNAL ;
  PORT
   LAYER M4 ;
   RECT 0.000 127.536 0.084 127.560 ;
  END
 END p_d[371]
 PIN p_d[372]
  DIRECTION OUTPUT ;
  USE SIGNAL ;
  PORT
   LAYER M4 ;
   RECT 0.000 127.728 0.084 127.752 ;
  END
 END p_d[372]
 PIN p_d[373]
  DIRECTION OUTPUT ;
  USE SIGNAL ;
  PORT
   LAYER M4 ;
   RECT 0.000 127.920 0.084 127.944 ;
  END
 END p_d[373]
 PIN p_d[374]
  DIRECTION OUTPUT ;
  USE SIGNAL ;
  PORT
   LAYER M4 ;
   RECT 0.000 128.112 0.084 128.136 ;
  END
 END p_d[374]
 PIN p_d[375]
  DIRECTION OUTPUT ;
  USE SIGNAL ;
  PORT
   LAYER M4 ;
   RECT 0.000 128.304 0.084 128.328 ;
  END
 END p_d[375]
 PIN p_d[376]
  DIRECTION OUTPUT ;
  USE SIGNAL ;
  PORT
   LAYER M4 ;
   RECT 0.000 128.496 0.084 128.520 ;
  END
 END p_d[376]
 PIN p_d[377]
  DIRECTION OUTPUT ;
  USE SIGNAL ;
  PORT
   LAYER M4 ;
   RECT 0.000 128.688 0.084 128.712 ;
  END
 END p_d[377]
 PIN p_d[378]
  DIRECTION OUTPUT ;
  USE SIGNAL ;
  PORT
   LAYER M4 ;
   RECT 0.000 128.880 0.084 128.904 ;
  END
 END p_d[378]
 PIN p_d[379]
  DIRECTION OUTPUT ;
  USE SIGNAL ;
  PORT
   LAYER M4 ;
   RECT 0.000 129.072 0.084 129.096 ;
  END
 END p_d[379]
 PIN p_d[380]
  DIRECTION OUTPUT ;
  USE SIGNAL ;
  PORT
   LAYER M4 ;
   RECT 0.000 129.264 0.084 129.288 ;
  END
 END p_d[380]
 PIN p_d[381]
  DIRECTION OUTPUT ;
  USE SIGNAL ;
  PORT
   LAYER M4 ;
   RECT 0.000 129.456 0.084 129.480 ;
  END
 END p_d[381]
 PIN p_d[382]
  DIRECTION OUTPUT ;
  USE SIGNAL ;
  PORT
   LAYER M4 ;
   RECT 0.000 129.648 0.084 129.672 ;
  END
 END p_d[382]
 PIN p_d[383]
  DIRECTION OUTPUT ;
  USE SIGNAL ;
  PORT
   LAYER M4 ;
   RECT 0.000 129.840 0.084 129.864 ;
  END
 END p_d[383]
 PIN p_d[384]
  DIRECTION OUTPUT ;
  USE SIGNAL ;
  PORT
   LAYER M4 ;
   RECT 0.000 130.032 0.084 130.056 ;
  END
 END p_d[384]
 PIN p_d[385]
  DIRECTION OUTPUT ;
  USE SIGNAL ;
  PORT
   LAYER M4 ;
   RECT 0.000 130.224 0.084 130.248 ;
  END
 END p_d[385]
 PIN p_d[386]
  DIRECTION OUTPUT ;
  USE SIGNAL ;
  PORT
   LAYER M4 ;
   RECT 0.000 130.416 0.084 130.440 ;
  END
 END p_d[386]
 PIN p_d[387]
  DIRECTION OUTPUT ;
  USE SIGNAL ;
  PORT
   LAYER M4 ;
   RECT 0.000 130.608 0.084 130.632 ;
  END
 END p_d[387]
 PIN p_d[388]
  DIRECTION OUTPUT ;
  USE SIGNAL ;
  PORT
   LAYER M4 ;
   RECT 0.000 130.800 0.084 130.824 ;
  END
 END p_d[388]
 PIN p_d[389]
  DIRECTION OUTPUT ;
  USE SIGNAL ;
  PORT
   LAYER M4 ;
   RECT 0.000 130.992 0.084 131.016 ;
  END
 END p_d[389]
 PIN p_d[390]
  DIRECTION OUTPUT ;
  USE SIGNAL ;
  PORT
   LAYER M4 ;
   RECT 0.000 131.184 0.084 131.208 ;
  END
 END p_d[390]
 PIN p_d[391]
  DIRECTION OUTPUT ;
  USE SIGNAL ;
  PORT
   LAYER M4 ;
   RECT 0.000 131.376 0.084 131.400 ;
  END
 END p_d[391]
 PIN p_d[392]
  DIRECTION OUTPUT ;
  USE SIGNAL ;
  PORT
   LAYER M4 ;
   RECT 0.000 131.568 0.084 131.592 ;
  END
 END p_d[392]
 PIN p_d[393]
  DIRECTION OUTPUT ;
  USE SIGNAL ;
  PORT
   LAYER M4 ;
   RECT 0.000 131.760 0.084 131.784 ;
  END
 END p_d[393]
 PIN p_d[394]
  DIRECTION OUTPUT ;
  USE SIGNAL ;
  PORT
   LAYER M4 ;
   RECT 0.000 131.952 0.084 131.976 ;
  END
 END p_d[394]
 PIN p_d[395]
  DIRECTION OUTPUT ;
  USE SIGNAL ;
  PORT
   LAYER M4 ;
   RECT 0.000 132.144 0.084 132.168 ;
  END
 END p_d[395]
 PIN p_d[396]
  DIRECTION OUTPUT ;
  USE SIGNAL ;
  PORT
   LAYER M4 ;
   RECT 0.000 132.336 0.084 132.360 ;
  END
 END p_d[396]
 PIN p_d[397]
  DIRECTION OUTPUT ;
  USE SIGNAL ;
  PORT
   LAYER M4 ;
   RECT 0.000 132.528 0.084 132.552 ;
  END
 END p_d[397]
 PIN p_d[398]
  DIRECTION OUTPUT ;
  USE SIGNAL ;
  PORT
   LAYER M4 ;
   RECT 0.000 132.720 0.084 132.744 ;
  END
 END p_d[398]
 PIN p_d[399]
  DIRECTION OUTPUT ;
  USE SIGNAL ;
  PORT
   LAYER M4 ;
   RECT 0.000 132.912 0.084 132.936 ;
  END
 END p_d[399]
 PIN p_d[400]
  DIRECTION OUTPUT ;
  USE SIGNAL ;
  PORT
   LAYER M4 ;
   RECT 0.000 133.104 0.084 133.128 ;
  END
 END p_d[400]
 PIN p_d[401]
  DIRECTION OUTPUT ;
  USE SIGNAL ;
  PORT
   LAYER M4 ;
   RECT 0.000 133.296 0.084 133.320 ;
  END
 END p_d[401]
 PIN p_d[402]
  DIRECTION OUTPUT ;
  USE SIGNAL ;
  PORT
   LAYER M4 ;
   RECT 0.000 133.488 0.084 133.512 ;
  END
 END p_d[402]
 PIN p_d[403]
  DIRECTION OUTPUT ;
  USE SIGNAL ;
  PORT
   LAYER M4 ;
   RECT 0.000 133.680 0.084 133.704 ;
  END
 END p_d[403]
 PIN p_d[404]
  DIRECTION OUTPUT ;
  USE SIGNAL ;
  PORT
   LAYER M4 ;
   RECT 0.000 133.872 0.084 133.896 ;
  END
 END p_d[404]
 PIN p_d[405]
  DIRECTION OUTPUT ;
  USE SIGNAL ;
  PORT
   LAYER M4 ;
   RECT 0.000 134.064 0.084 134.088 ;
  END
 END p_d[405]
 PIN p_d[406]
  DIRECTION OUTPUT ;
  USE SIGNAL ;
  PORT
   LAYER M4 ;
   RECT 0.000 134.256 0.084 134.280 ;
  END
 END p_d[406]
 PIN p_d[407]
  DIRECTION OUTPUT ;
  USE SIGNAL ;
  PORT
   LAYER M4 ;
   RECT 0.000 134.448 0.084 134.472 ;
  END
 END p_d[407]
 PIN p_d[408]
  DIRECTION OUTPUT ;
  USE SIGNAL ;
  PORT
   LAYER M4 ;
   RECT 0.000 134.640 0.084 134.664 ;
  END
 END p_d[408]
 PIN p_d[409]
  DIRECTION OUTPUT ;
  USE SIGNAL ;
  PORT
   LAYER M4 ;
   RECT 0.000 134.832 0.084 134.856 ;
  END
 END p_d[409]
 PIN p_d[410]
  DIRECTION OUTPUT ;
  USE SIGNAL ;
  PORT
   LAYER M4 ;
   RECT 0.000 135.024 0.084 135.048 ;
  END
 END p_d[410]
 PIN p_d[411]
  DIRECTION OUTPUT ;
  USE SIGNAL ;
  PORT
   LAYER M4 ;
   RECT 0.000 135.216 0.084 135.240 ;
  END
 END p_d[411]
 PIN p_d[412]
  DIRECTION OUTPUT ;
  USE SIGNAL ;
  PORT
   LAYER M4 ;
   RECT 0.000 135.408 0.084 135.432 ;
  END
 END p_d[412]
 PIN p_d[413]
  DIRECTION OUTPUT ;
  USE SIGNAL ;
  PORT
   LAYER M4 ;
   RECT 0.000 135.600 0.084 135.624 ;
  END
 END p_d[413]
 PIN p_d[414]
  DIRECTION OUTPUT ;
  USE SIGNAL ;
  PORT
   LAYER M4 ;
   RECT 0.000 135.792 0.084 135.816 ;
  END
 END p_d[414]
 PIN p_d[415]
  DIRECTION OUTPUT ;
  USE SIGNAL ;
  PORT
   LAYER M4 ;
   RECT 0.000 135.984 0.084 136.008 ;
  END
 END p_d[415]
 PIN p_d[416]
  DIRECTION OUTPUT ;
  USE SIGNAL ;
  PORT
   LAYER M4 ;
   RECT 0.000 136.176 0.084 136.200 ;
  END
 END p_d[416]
 PIN p_d[417]
  DIRECTION OUTPUT ;
  USE SIGNAL ;
  PORT
   LAYER M4 ;
   RECT 0.000 136.368 0.084 136.392 ;
  END
 END p_d[417]
 PIN p_d[418]
  DIRECTION OUTPUT ;
  USE SIGNAL ;
  PORT
   LAYER M4 ;
   RECT 0.000 136.560 0.084 136.584 ;
  END
 END p_d[418]
 PIN p_d[419]
  DIRECTION OUTPUT ;
  USE SIGNAL ;
  PORT
   LAYER M4 ;
   RECT 0.000 136.752 0.084 136.776 ;
  END
 END p_d[419]
 PIN p_d[420]
  DIRECTION OUTPUT ;
  USE SIGNAL ;
  PORT
   LAYER M4 ;
   RECT 0.000 136.944 0.084 136.968 ;
  END
 END p_d[420]
 PIN p_d[421]
  DIRECTION OUTPUT ;
  USE SIGNAL ;
  PORT
   LAYER M4 ;
   RECT 0.000 137.136 0.084 137.160 ;
  END
 END p_d[421]
 PIN p_d[422]
  DIRECTION OUTPUT ;
  USE SIGNAL ;
  PORT
   LAYER M4 ;
   RECT 0.000 137.328 0.084 137.352 ;
  END
 END p_d[422]
 PIN p_d[423]
  DIRECTION OUTPUT ;
  USE SIGNAL ;
  PORT
   LAYER M4 ;
   RECT 0.000 137.520 0.084 137.544 ;
  END
 END p_d[423]
 PIN p_d[424]
  DIRECTION OUTPUT ;
  USE SIGNAL ;
  PORT
   LAYER M4 ;
   RECT 0.000 137.712 0.084 137.736 ;
  END
 END p_d[424]
 PIN p_d[425]
  DIRECTION OUTPUT ;
  USE SIGNAL ;
  PORT
   LAYER M4 ;
   RECT 0.000 137.904 0.084 137.928 ;
  END
 END p_d[425]
 PIN p_d[426]
  DIRECTION OUTPUT ;
  USE SIGNAL ;
  PORT
   LAYER M4 ;
   RECT 0.000 138.096 0.084 138.120 ;
  END
 END p_d[426]
 PIN p_d[427]
  DIRECTION OUTPUT ;
  USE SIGNAL ;
  PORT
   LAYER M4 ;
   RECT 0.000 138.288 0.084 138.312 ;
  END
 END p_d[427]
 PIN p_d[428]
  DIRECTION OUTPUT ;
  USE SIGNAL ;
  PORT
   LAYER M4 ;
   RECT 0.000 138.480 0.084 138.504 ;
  END
 END p_d[428]
 PIN p_d[429]
  DIRECTION OUTPUT ;
  USE SIGNAL ;
  PORT
   LAYER M4 ;
   RECT 0.000 138.672 0.084 138.696 ;
  END
 END p_d[429]
 PIN p_d[430]
  DIRECTION OUTPUT ;
  USE SIGNAL ;
  PORT
   LAYER M4 ;
   RECT 0.000 138.864 0.084 138.888 ;
  END
 END p_d[430]
 PIN p_d[431]
  DIRECTION OUTPUT ;
  USE SIGNAL ;
  PORT
   LAYER M4 ;
   RECT 0.000 139.056 0.084 139.080 ;
  END
 END p_d[431]
 PIN p_d[432]
  DIRECTION OUTPUT ;
  USE SIGNAL ;
  PORT
   LAYER M4 ;
   RECT 0.000 139.248 0.084 139.272 ;
  END
 END p_d[432]
 PIN p_d[433]
  DIRECTION OUTPUT ;
  USE SIGNAL ;
  PORT
   LAYER M4 ;
   RECT 0.000 139.440 0.084 139.464 ;
  END
 END p_d[433]
 PIN p_d[434]
  DIRECTION OUTPUT ;
  USE SIGNAL ;
  PORT
   LAYER M4 ;
   RECT 0.000 139.632 0.084 139.656 ;
  END
 END p_d[434]
 PIN p_d[435]
  DIRECTION OUTPUT ;
  USE SIGNAL ;
  PORT
   LAYER M4 ;
   RECT 0.000 139.824 0.084 139.848 ;
  END
 END p_d[435]
 PIN p_d[436]
  DIRECTION OUTPUT ;
  USE SIGNAL ;
  PORT
   LAYER M4 ;
   RECT 0.000 140.016 0.084 140.040 ;
  END
 END p_d[436]
 PIN p_d[437]
  DIRECTION OUTPUT ;
  USE SIGNAL ;
  PORT
   LAYER M4 ;
   RECT 0.000 140.208 0.084 140.232 ;
  END
 END p_d[437]
 PIN p_d[438]
  DIRECTION OUTPUT ;
  USE SIGNAL ;
  PORT
   LAYER M4 ;
   RECT 0.000 140.400 0.084 140.424 ;
  END
 END p_d[438]
 PIN p_d[439]
  DIRECTION OUTPUT ;
  USE SIGNAL ;
  PORT
   LAYER M4 ;
   RECT 0.000 140.592 0.084 140.616 ;
  END
 END p_d[439]
 PIN p_d[440]
  DIRECTION OUTPUT ;
  USE SIGNAL ;
  PORT
   LAYER M4 ;
   RECT 0.000 140.784 0.084 140.808 ;
  END
 END p_d[440]
 PIN p_d[441]
  DIRECTION OUTPUT ;
  USE SIGNAL ;
  PORT
   LAYER M4 ;
   RECT 0.000 140.976 0.084 141.000 ;
  END
 END p_d[441]
 PIN p_d[442]
  DIRECTION OUTPUT ;
  USE SIGNAL ;
  PORT
   LAYER M4 ;
   RECT 0.000 141.168 0.084 141.192 ;
  END
 END p_d[442]
 PIN p_d[443]
  DIRECTION OUTPUT ;
  USE SIGNAL ;
  PORT
   LAYER M4 ;
   RECT 0.000 141.360 0.084 141.384 ;
  END
 END p_d[443]
 PIN p_d[444]
  DIRECTION OUTPUT ;
  USE SIGNAL ;
  PORT
   LAYER M4 ;
   RECT 0.000 141.552 0.084 141.576 ;
  END
 END p_d[444]
 PIN p_d[445]
  DIRECTION OUTPUT ;
  USE SIGNAL ;
  PORT
   LAYER M4 ;
   RECT 0.000 141.744 0.084 141.768 ;
  END
 END p_d[445]
 PIN p_d[446]
  DIRECTION OUTPUT ;
  USE SIGNAL ;
  PORT
   LAYER M4 ;
   RECT 0.000 141.936 0.084 141.960 ;
  END
 END p_d[446]
 PIN p_d[447]
  DIRECTION OUTPUT ;
  USE SIGNAL ;
  PORT
   LAYER M4 ;
   RECT 0.000 142.128 0.084 142.152 ;
  END
 END p_d[447]
 PIN p_d[448]
  DIRECTION OUTPUT ;
  USE SIGNAL ;
  PORT
   LAYER M4 ;
   RECT 0.000 142.320 0.084 142.344 ;
  END
 END p_d[448]
 PIN p_d[449]
  DIRECTION OUTPUT ;
  USE SIGNAL ;
  PORT
   LAYER M4 ;
   RECT 0.000 142.512 0.084 142.536 ;
  END
 END p_d[449]
 PIN p_d[450]
  DIRECTION OUTPUT ;
  USE SIGNAL ;
  PORT
   LAYER M4 ;
   RECT 0.000 142.704 0.084 142.728 ;
  END
 END p_d[450]
 PIN p_d[451]
  DIRECTION OUTPUT ;
  USE SIGNAL ;
  PORT
   LAYER M4 ;
   RECT 0.000 142.896 0.084 142.920 ;
  END
 END p_d[451]
 PIN p_d[452]
  DIRECTION OUTPUT ;
  USE SIGNAL ;
  PORT
   LAYER M4 ;
   RECT 0.000 143.088 0.084 143.112 ;
  END
 END p_d[452]
 PIN p_d[453]
  DIRECTION OUTPUT ;
  USE SIGNAL ;
  PORT
   LAYER M4 ;
   RECT 0.000 143.280 0.084 143.304 ;
  END
 END p_d[453]
 PIN p_d[454]
  DIRECTION OUTPUT ;
  USE SIGNAL ;
  PORT
   LAYER M4 ;
   RECT 0.000 143.472 0.084 143.496 ;
  END
 END p_d[454]
 PIN p_d[455]
  DIRECTION OUTPUT ;
  USE SIGNAL ;
  PORT
   LAYER M4 ;
   RECT 0.000 143.664 0.084 143.688 ;
  END
 END p_d[455]
 PIN p_d[456]
  DIRECTION OUTPUT ;
  USE SIGNAL ;
  PORT
   LAYER M4 ;
   RECT 0.000 143.856 0.084 143.880 ;
  END
 END p_d[456]
 PIN p_d[457]
  DIRECTION OUTPUT ;
  USE SIGNAL ;
  PORT
   LAYER M4 ;
   RECT 0.000 144.048 0.084 144.072 ;
  END
 END p_d[457]
 PIN p_d[458]
  DIRECTION OUTPUT ;
  USE SIGNAL ;
  PORT
   LAYER M4 ;
   RECT 0.000 144.240 0.084 144.264 ;
  END
 END p_d[458]
 PIN p_d[459]
  DIRECTION OUTPUT ;
  USE SIGNAL ;
  PORT
   LAYER M4 ;
   RECT 0.000 144.432 0.084 144.456 ;
  END
 END p_d[459]
 PIN p_d[460]
  DIRECTION OUTPUT ;
  USE SIGNAL ;
  PORT
   LAYER M4 ;
   RECT 0.000 144.624 0.084 144.648 ;
  END
 END p_d[460]
 PIN p_d[461]
  DIRECTION OUTPUT ;
  USE SIGNAL ;
  PORT
   LAYER M4 ;
   RECT 0.000 144.816 0.084 144.840 ;
  END
 END p_d[461]
 PIN p_d[462]
  DIRECTION OUTPUT ;
  USE SIGNAL ;
  PORT
   LAYER M4 ;
   RECT 0.000 145.008 0.084 145.032 ;
  END
 END p_d[462]
 PIN p_d[463]
  DIRECTION OUTPUT ;
  USE SIGNAL ;
  PORT
   LAYER M4 ;
   RECT 0.000 145.200 0.084 145.224 ;
  END
 END p_d[463]
 PIN p_d[464]
  DIRECTION OUTPUT ;
  USE SIGNAL ;
  PORT
   LAYER M4 ;
   RECT 0.000 145.392 0.084 145.416 ;
  END
 END p_d[464]
 PIN p_d[465]
  DIRECTION OUTPUT ;
  USE SIGNAL ;
  PORT
   LAYER M4 ;
   RECT 0.000 145.584 0.084 145.608 ;
  END
 END p_d[465]
 PIN p_d[466]
  DIRECTION OUTPUT ;
  USE SIGNAL ;
  PORT
   LAYER M4 ;
   RECT 0.000 145.776 0.084 145.800 ;
  END
 END p_d[466]
 PIN p_d[467]
  DIRECTION OUTPUT ;
  USE SIGNAL ;
  PORT
   LAYER M4 ;
   RECT 0.000 145.968 0.084 145.992 ;
  END
 END p_d[467]
 PIN p_d[468]
  DIRECTION OUTPUT ;
  USE SIGNAL ;
  PORT
   LAYER M4 ;
   RECT 0.000 146.160 0.084 146.184 ;
  END
 END p_d[468]
 PIN p_d[469]
  DIRECTION OUTPUT ;
  USE SIGNAL ;
  PORT
   LAYER M4 ;
   RECT 0.000 146.352 0.084 146.376 ;
  END
 END p_d[469]
 PIN p_d[470]
  DIRECTION OUTPUT ;
  USE SIGNAL ;
  PORT
   LAYER M4 ;
   RECT 0.000 146.544 0.084 146.568 ;
  END
 END p_d[470]
 PIN p_d[471]
  DIRECTION OUTPUT ;
  USE SIGNAL ;
  PORT
   LAYER M4 ;
   RECT 0.000 146.736 0.084 146.760 ;
  END
 END p_d[471]
 PIN p_d[472]
  DIRECTION OUTPUT ;
  USE SIGNAL ;
  PORT
   LAYER M4 ;
   RECT 0.000 146.928 0.084 146.952 ;
  END
 END p_d[472]
 PIN p_d[473]
  DIRECTION OUTPUT ;
  USE SIGNAL ;
  PORT
   LAYER M4 ;
   RECT 0.000 147.120 0.084 147.144 ;
  END
 END p_d[473]
 PIN p_d[474]
  DIRECTION OUTPUT ;
  USE SIGNAL ;
  PORT
   LAYER M4 ;
   RECT 0.000 147.312 0.084 147.336 ;
  END
 END p_d[474]
 PIN p_d[475]
  DIRECTION OUTPUT ;
  USE SIGNAL ;
  PORT
   LAYER M4 ;
   RECT 0.000 147.504 0.084 147.528 ;
  END
 END p_d[475]
 PIN p_d[476]
  DIRECTION OUTPUT ;
  USE SIGNAL ;
  PORT
   LAYER M4 ;
   RECT 0.000 147.696 0.084 147.720 ;
  END
 END p_d[476]
 PIN p_d[477]
  DIRECTION OUTPUT ;
  USE SIGNAL ;
  PORT
   LAYER M4 ;
   RECT 0.000 147.888 0.084 147.912 ;
  END
 END p_d[477]
 PIN p_d[478]
  DIRECTION OUTPUT ;
  USE SIGNAL ;
  PORT
   LAYER M4 ;
   RECT 0.000 148.080 0.084 148.104 ;
  END
 END p_d[478]
 PIN p_d[479]
  DIRECTION OUTPUT ;
  USE SIGNAL ;
  PORT
   LAYER M4 ;
   RECT 0.000 148.272 0.084 148.296 ;
  END
 END p_d[479]
 PIN p_d[480]
  DIRECTION OUTPUT ;
  USE SIGNAL ;
  PORT
   LAYER M4 ;
   RECT 0.000 148.464 0.084 148.488 ;
  END
 END p_d[480]
 PIN p_d[481]
  DIRECTION OUTPUT ;
  USE SIGNAL ;
  PORT
   LAYER M4 ;
   RECT 0.000 148.656 0.084 148.680 ;
  END
 END p_d[481]
 PIN p_d[482]
  DIRECTION OUTPUT ;
  USE SIGNAL ;
  PORT
   LAYER M4 ;
   RECT 0.000 148.848 0.084 148.872 ;
  END
 END p_d[482]
 PIN p_d[483]
  DIRECTION OUTPUT ;
  USE SIGNAL ;
  PORT
   LAYER M4 ;
   RECT 0.000 149.040 0.084 149.064 ;
  END
 END p_d[483]
 PIN p_d[484]
  DIRECTION OUTPUT ;
  USE SIGNAL ;
  PORT
   LAYER M4 ;
   RECT 0.000 149.232 0.084 149.256 ;
  END
 END p_d[484]
 PIN p_d[485]
  DIRECTION OUTPUT ;
  USE SIGNAL ;
  PORT
   LAYER M4 ;
   RECT 0.000 149.424 0.084 149.448 ;
  END
 END p_d[485]
 PIN p_d[486]
  DIRECTION OUTPUT ;
  USE SIGNAL ;
  PORT
   LAYER M4 ;
   RECT 0.000 149.616 0.084 149.640 ;
  END
 END p_d[486]
 PIN p_d[487]
  DIRECTION OUTPUT ;
  USE SIGNAL ;
  PORT
   LAYER M4 ;
   RECT 0.000 149.808 0.084 149.832 ;
  END
 END p_d[487]
 PIN p_d[488]
  DIRECTION OUTPUT ;
  USE SIGNAL ;
  PORT
   LAYER M4 ;
   RECT 0.000 150.000 0.084 150.024 ;
  END
 END p_d[488]
 PIN p_d[489]
  DIRECTION OUTPUT ;
  USE SIGNAL ;
  PORT
   LAYER M4 ;
   RECT 0.000 150.192 0.084 150.216 ;
  END
 END p_d[489]
 PIN p_d[490]
  DIRECTION OUTPUT ;
  USE SIGNAL ;
  PORT
   LAYER M4 ;
   RECT 0.000 150.384 0.084 150.408 ;
  END
 END p_d[490]
 PIN p_d[491]
  DIRECTION OUTPUT ;
  USE SIGNAL ;
  PORT
   LAYER M4 ;
   RECT 0.000 150.576 0.084 150.600 ;
  END
 END p_d[491]
 PIN p_d[492]
  DIRECTION OUTPUT ;
  USE SIGNAL ;
  PORT
   LAYER M4 ;
   RECT 0.000 150.768 0.084 150.792 ;
  END
 END p_d[492]
 PIN p_d[493]
  DIRECTION OUTPUT ;
  USE SIGNAL ;
  PORT
   LAYER M4 ;
   RECT 0.000 150.960 0.084 150.984 ;
  END
 END p_d[493]
 PIN p_d[494]
  DIRECTION OUTPUT ;
  USE SIGNAL ;
  PORT
   LAYER M4 ;
   RECT 0.000 151.152 0.084 151.176 ;
  END
 END p_d[494]
 PIN p_d[495]
  DIRECTION OUTPUT ;
  USE SIGNAL ;
  PORT
   LAYER M4 ;
   RECT 0.000 151.344 0.084 151.368 ;
  END
 END p_d[495]
 PIN p_d[496]
  DIRECTION OUTPUT ;
  USE SIGNAL ;
  PORT
   LAYER M4 ;
   RECT 0.000 151.536 0.084 151.560 ;
  END
 END p_d[496]
 PIN p_d[497]
  DIRECTION OUTPUT ;
  USE SIGNAL ;
  PORT
   LAYER M4 ;
   RECT 0.000 151.728 0.084 151.752 ;
  END
 END p_d[497]
 PIN p_d[498]
  DIRECTION OUTPUT ;
  USE SIGNAL ;
  PORT
   LAYER M4 ;
   RECT 0.000 151.920 0.084 151.944 ;
  END
 END p_d[498]
 PIN p_d[499]
  DIRECTION OUTPUT ;
  USE SIGNAL ;
  PORT
   LAYER M4 ;
   RECT 0.000 152.112 0.084 152.136 ;
  END
 END p_d[499]
 PIN p_d[500]
  DIRECTION OUTPUT ;
  USE SIGNAL ;
  PORT
   LAYER M4 ;
   RECT 0.000 152.304 0.084 152.328 ;
  END
 END p_d[500]
 PIN p_d[501]
  DIRECTION OUTPUT ;
  USE SIGNAL ;
  PORT
   LAYER M4 ;
   RECT 0.000 152.496 0.084 152.520 ;
  END
 END p_d[501]
 PIN p_d[502]
  DIRECTION OUTPUT ;
  USE SIGNAL ;
  PORT
   LAYER M4 ;
   RECT 0.000 152.688 0.084 152.712 ;
  END
 END p_d[502]
 PIN p_d[503]
  DIRECTION OUTPUT ;
  USE SIGNAL ;
  PORT
   LAYER M4 ;
   RECT 0.000 152.880 0.084 152.904 ;
  END
 END p_d[503]
 PIN p_d[504]
  DIRECTION OUTPUT ;
  USE SIGNAL ;
  PORT
   LAYER M4 ;
   RECT 0.000 153.072 0.084 153.096 ;
  END
 END p_d[504]
 PIN p_d[505]
  DIRECTION OUTPUT ;
  USE SIGNAL ;
  PORT
   LAYER M4 ;
   RECT 0.000 153.264 0.084 153.288 ;
  END
 END p_d[505]
 PIN p_d[506]
  DIRECTION OUTPUT ;
  USE SIGNAL ;
  PORT
   LAYER M4 ;
   RECT 0.000 153.456 0.084 153.480 ;
  END
 END p_d[506]
 PIN p_d[507]
  DIRECTION OUTPUT ;
  USE SIGNAL ;
  PORT
   LAYER M4 ;
   RECT 0.000 153.648 0.084 153.672 ;
  END
 END p_d[507]
 PIN p_d[508]
  DIRECTION OUTPUT ;
  USE SIGNAL ;
  PORT
   LAYER M4 ;
   RECT 0.000 153.840 0.084 153.864 ;
  END
 END p_d[508]
 PIN p_d[509]
  DIRECTION OUTPUT ;
  USE SIGNAL ;
  PORT
   LAYER M4 ;
   RECT 0.000 154.032 0.084 154.056 ;
  END
 END p_d[509]
 PIN p_d[510]
  DIRECTION OUTPUT ;
  USE SIGNAL ;
  PORT
   LAYER M4 ;
   RECT 0.000 154.224 0.084 154.248 ;
  END
 END p_d[510]
 PIN p_d[511]
  DIRECTION OUTPUT ;
  USE SIGNAL ;
  PORT
   LAYER M4 ;
   RECT 0.000 154.416 0.084 154.440 ;
  END
 END p_d[511]
 PIN p_d[512]
  DIRECTION OUTPUT ;
  USE SIGNAL ;
  PORT
   LAYER M4 ;
   RECT 0.000 154.608 0.084 154.632 ;
  END
 END p_d[512]
 PIN p_d[513]
  DIRECTION OUTPUT ;
  USE SIGNAL ;
  PORT
   LAYER M4 ;
   RECT 0.000 154.800 0.084 154.824 ;
  END
 END p_d[513]
 PIN p_d[514]
  DIRECTION OUTPUT ;
  USE SIGNAL ;
  PORT
   LAYER M4 ;
   RECT 0.000 154.992 0.084 155.016 ;
  END
 END p_d[514]
 PIN p_d[515]
  DIRECTION OUTPUT ;
  USE SIGNAL ;
  PORT
   LAYER M4 ;
   RECT 0.000 155.184 0.084 155.208 ;
  END
 END p_d[515]
 PIN p_d[516]
  DIRECTION OUTPUT ;
  USE SIGNAL ;
  PORT
   LAYER M4 ;
   RECT 0.000 155.376 0.084 155.400 ;
  END
 END p_d[516]
 PIN p_d[517]
  DIRECTION OUTPUT ;
  USE SIGNAL ;
  PORT
   LAYER M4 ;
   RECT 0.000 155.568 0.084 155.592 ;
  END
 END p_d[517]
 PIN p_d[518]
  DIRECTION OUTPUT ;
  USE SIGNAL ;
  PORT
   LAYER M4 ;
   RECT 0.000 155.760 0.084 155.784 ;
  END
 END p_d[518]
 PIN p_d[519]
  DIRECTION OUTPUT ;
  USE SIGNAL ;
  PORT
   LAYER M4 ;
   RECT 0.000 155.952 0.084 155.976 ;
  END
 END p_d[519]
 PIN p_d[520]
  DIRECTION OUTPUT ;
  USE SIGNAL ;
  PORT
   LAYER M4 ;
   RECT 0.000 156.144 0.084 156.168 ;
  END
 END p_d[520]
 PIN p_d[521]
  DIRECTION OUTPUT ;
  USE SIGNAL ;
  PORT
   LAYER M4 ;
   RECT 0.000 156.336 0.084 156.360 ;
  END
 END p_d[521]
 PIN p_d[522]
  DIRECTION OUTPUT ;
  USE SIGNAL ;
  PORT
   LAYER M4 ;
   RECT 0.000 156.528 0.084 156.552 ;
  END
 END p_d[522]
 PIN p_d[523]
  DIRECTION OUTPUT ;
  USE SIGNAL ;
  PORT
   LAYER M4 ;
   RECT 0.000 156.720 0.084 156.744 ;
  END
 END p_d[523]
 PIN p_d[524]
  DIRECTION OUTPUT ;
  USE SIGNAL ;
  PORT
   LAYER M4 ;
   RECT 0.000 156.912 0.084 156.936 ;
  END
 END p_d[524]
 PIN p_d[525]
  DIRECTION OUTPUT ;
  USE SIGNAL ;
  PORT
   LAYER M4 ;
   RECT 0.000 157.104 0.084 157.128 ;
  END
 END p_d[525]
 PIN p_d[526]
  DIRECTION OUTPUT ;
  USE SIGNAL ;
  PORT
   LAYER M4 ;
   RECT 0.000 157.296 0.084 157.320 ;
  END
 END p_d[526]
 PIN p_d[527]
  DIRECTION OUTPUT ;
  USE SIGNAL ;
  PORT
   LAYER M4 ;
   RECT 0.000 157.488 0.084 157.512 ;
  END
 END p_d[527]
 PIN p_d[528]
  DIRECTION OUTPUT ;
  USE SIGNAL ;
  PORT
   LAYER M4 ;
   RECT 0.000 157.680 0.084 157.704 ;
  END
 END p_d[528]
 PIN p_d[529]
  DIRECTION OUTPUT ;
  USE SIGNAL ;
  PORT
   LAYER M4 ;
   RECT 0.000 157.872 0.084 157.896 ;
  END
 END p_d[529]
 PIN p_d[530]
  DIRECTION OUTPUT ;
  USE SIGNAL ;
  PORT
   LAYER M4 ;
   RECT 0.000 158.064 0.084 158.088 ;
  END
 END p_d[530]
 PIN p_d[531]
  DIRECTION OUTPUT ;
  USE SIGNAL ;
  PORT
   LAYER M4 ;
   RECT 0.000 158.256 0.084 158.280 ;
  END
 END p_d[531]
 PIN p_d[532]
  DIRECTION OUTPUT ;
  USE SIGNAL ;
  PORT
   LAYER M4 ;
   RECT 0.000 158.448 0.084 158.472 ;
  END
 END p_d[532]
 PIN p_d[533]
  DIRECTION OUTPUT ;
  USE SIGNAL ;
  PORT
   LAYER M4 ;
   RECT 0.000 158.640 0.084 158.664 ;
  END
 END p_d[533]
 PIN p_d[534]
  DIRECTION OUTPUT ;
  USE SIGNAL ;
  PORT
   LAYER M4 ;
   RECT 0.000 158.832 0.084 158.856 ;
  END
 END p_d[534]
 PIN p_d[535]
  DIRECTION OUTPUT ;
  USE SIGNAL ;
  PORT
   LAYER M4 ;
   RECT 0.000 159.024 0.084 159.048 ;
  END
 END p_d[535]
 PIN p_d[536]
  DIRECTION OUTPUT ;
  USE SIGNAL ;
  PORT
   LAYER M4 ;
   RECT 0.000 159.216 0.084 159.240 ;
  END
 END p_d[536]
 PIN p_d[537]
  DIRECTION OUTPUT ;
  USE SIGNAL ;
  PORT
   LAYER M4 ;
   RECT 0.000 159.408 0.084 159.432 ;
  END
 END p_d[537]
 PIN p_d[538]
  DIRECTION OUTPUT ;
  USE SIGNAL ;
  PORT
   LAYER M4 ;
   RECT 0.000 159.600 0.084 159.624 ;
  END
 END p_d[538]
 PIN p_d[539]
  DIRECTION OUTPUT ;
  USE SIGNAL ;
  PORT
   LAYER M4 ;
   RECT 0.000 159.792 0.084 159.816 ;
  END
 END p_d[539]
 PIN p_d[540]
  DIRECTION OUTPUT ;
  USE SIGNAL ;
  PORT
   LAYER M4 ;
   RECT 0.000 159.984 0.084 160.008 ;
  END
 END p_d[540]
 PIN p_d[541]
  DIRECTION OUTPUT ;
  USE SIGNAL ;
  PORT
   LAYER M4 ;
   RECT 0.000 160.176 0.084 160.200 ;
  END
 END p_d[541]
 PIN p_d[542]
  DIRECTION OUTPUT ;
  USE SIGNAL ;
  PORT
   LAYER M4 ;
   RECT 0.000 160.368 0.084 160.392 ;
  END
 END p_d[542]
 PIN p_d[543]
  DIRECTION OUTPUT ;
  USE SIGNAL ;
  PORT
   LAYER M4 ;
   RECT 0.000 160.560 0.084 160.584 ;
  END
 END p_d[543]
 PIN fault
  DIRECTION OUTPUT ;
  USE SIGNAL ;
  PORT
   LAYER M4 ;
   RECT 0.000 160.752 0.084 160.776 ;
  END
 END fault
 PIN clk
  DIRECTION INPUT ;
  USE CLOCK ;
  PORT
   LAYER M5 ;
   RECT 108.000 215.916 108.024 216.000 ;
  END
 END clk
END ot_s81_rck_tx
END LIBRARY
